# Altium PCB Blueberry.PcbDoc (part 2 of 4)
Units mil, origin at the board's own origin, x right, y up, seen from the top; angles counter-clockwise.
Board outline 2559.06 x 2204.72 mil, 6 copper layers (Top Layer, Mid-Layer 1, Mid-Layer 2, Mid-Layer 3, Mid-Layer 4, Bottom Layer); 211 components, 214 nets, 1171 pads, 598 vias.

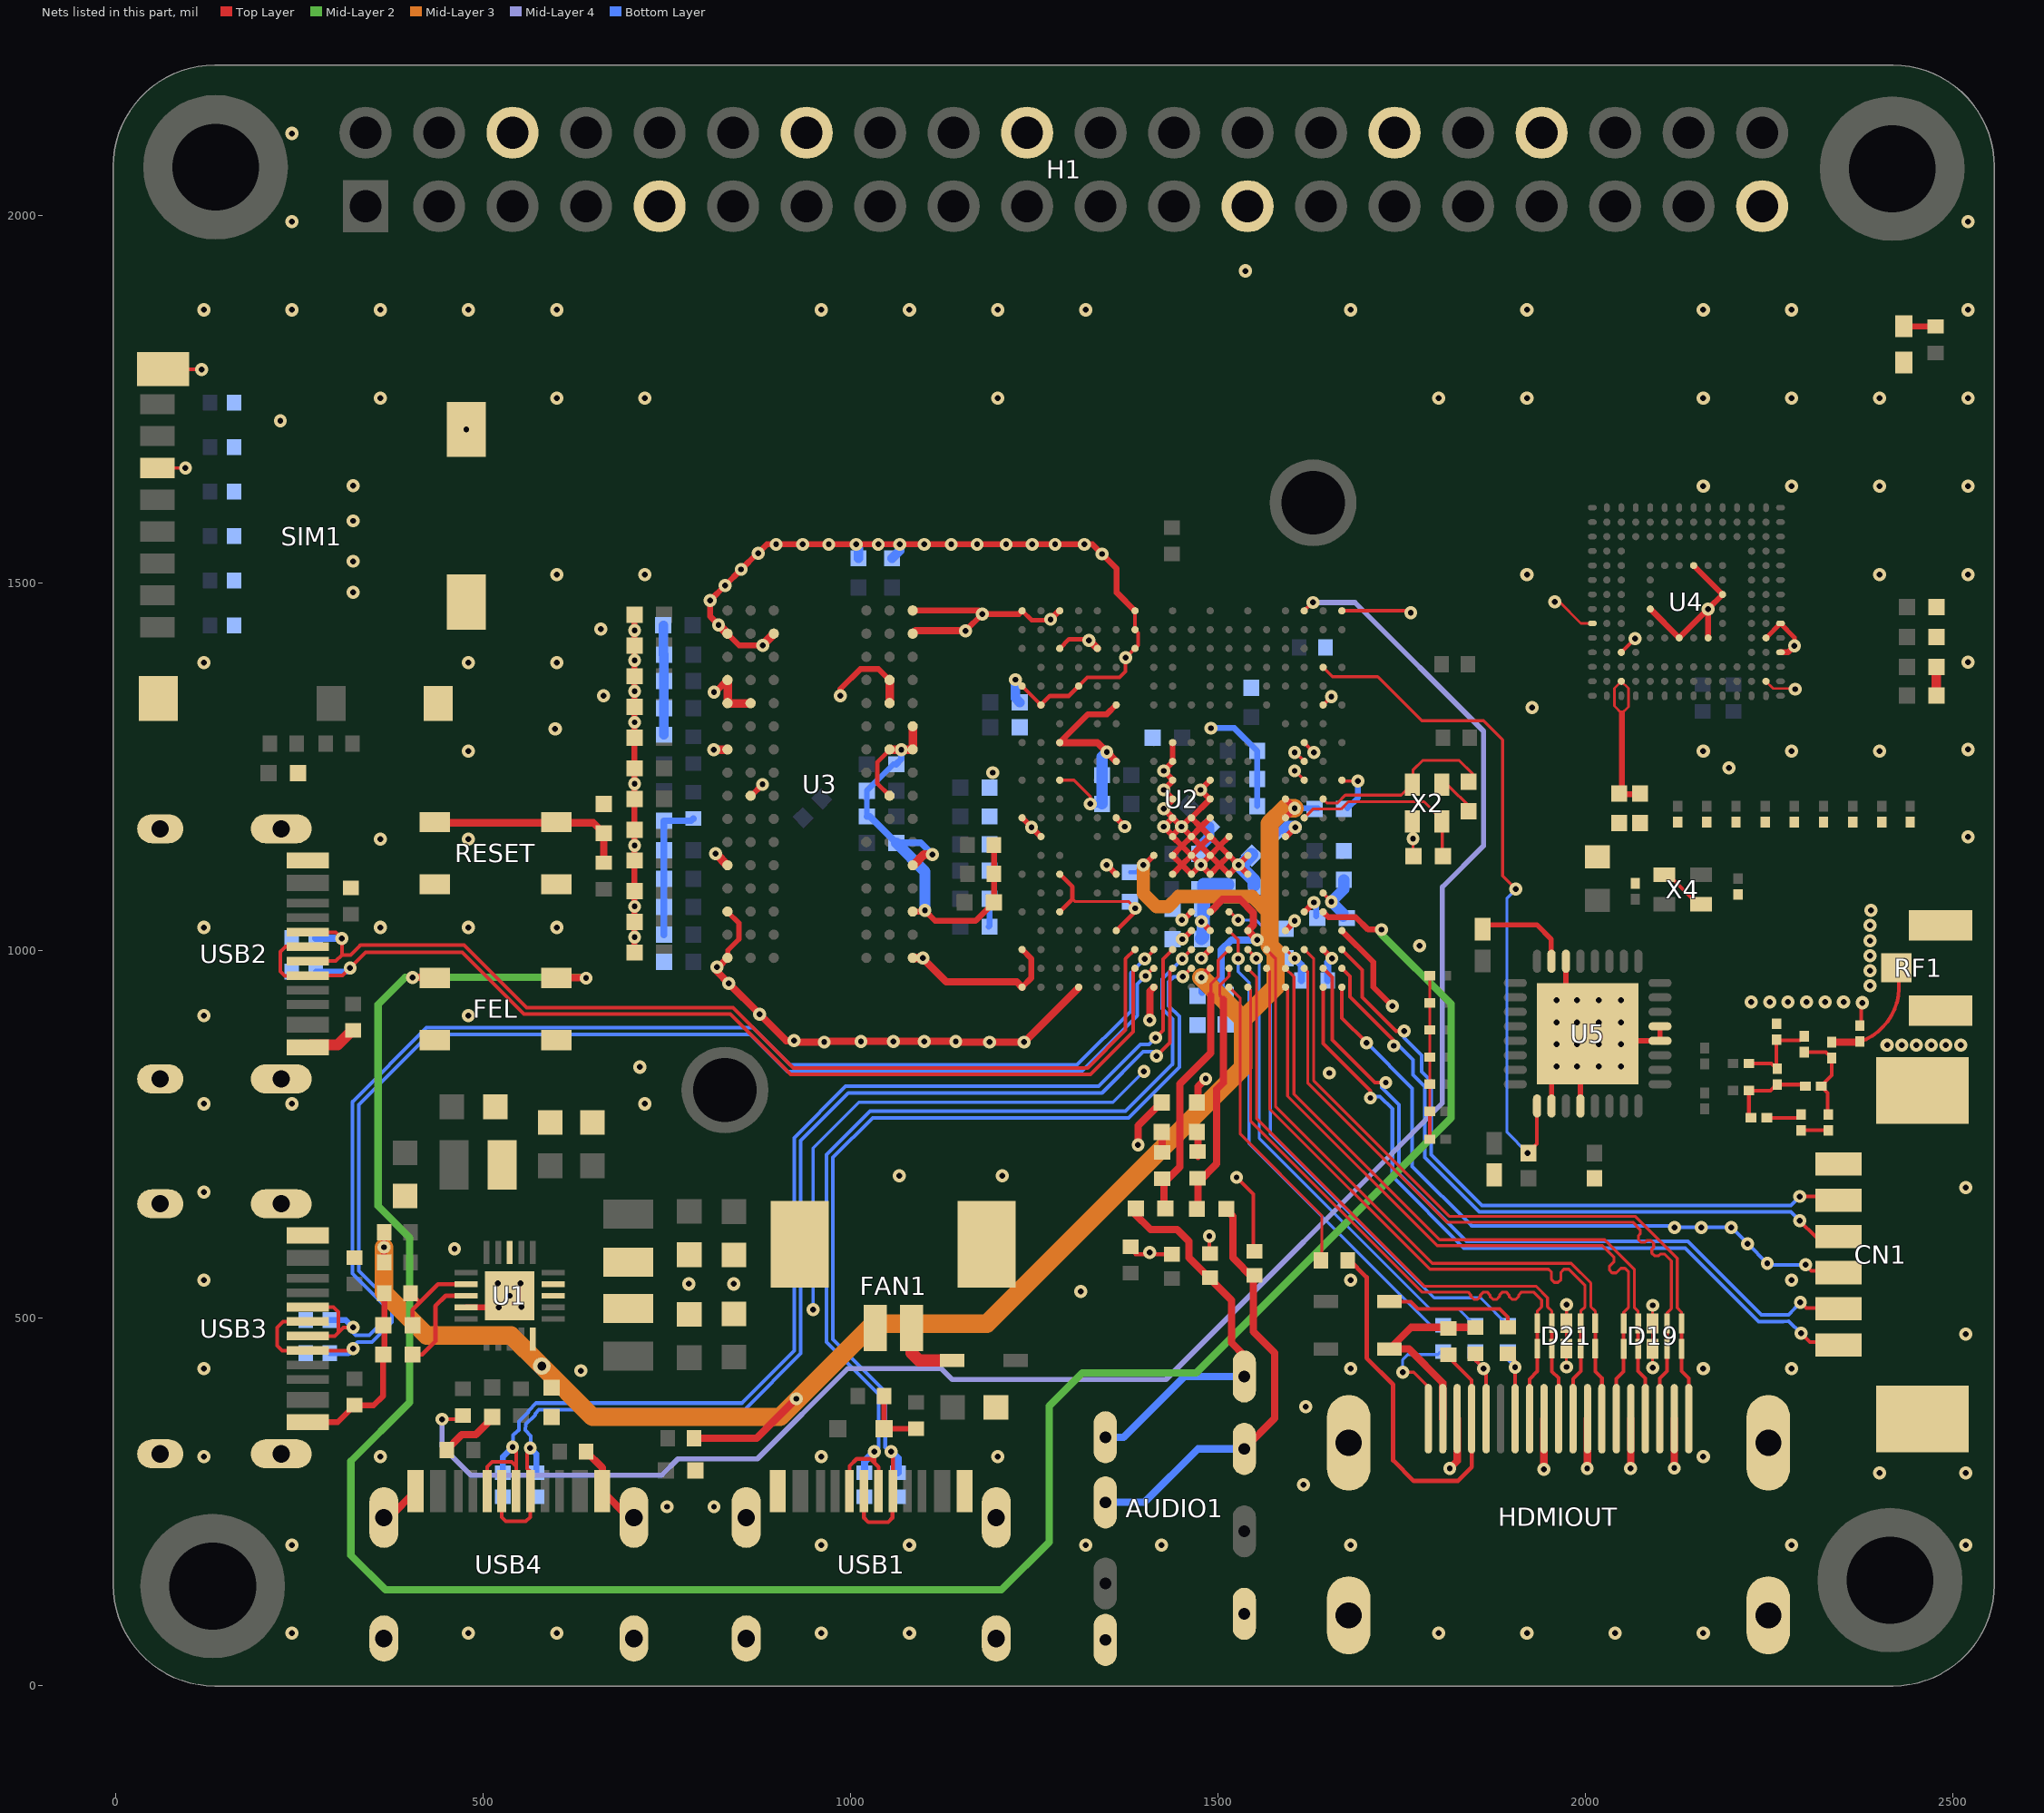
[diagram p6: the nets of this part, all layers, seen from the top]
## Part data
AUDIO1: Current Rating (Max)=500mA, JLCPCB Part Class="Extended Part", LCSC Part Name=3.5mm耳机座, Manufacturer=韩国韩荣, Voltage Rating (Max)=30V
C66 C67 C68 C69 C70 C71 C104 C105 C106 C107 C108 C117 C120: JLCPCB Part Class="Extended Part", LCSC Part Name="100nF ±10% 16V", Manufacturer=SAMSUNG(三星), Temperature Coefficient=X5R, Tolerance=±10%, Voltage Rated=16V
C87: JLCPCB Part Class="Extended Part", LCSC Part Name="100nF ±10% 25V", Manufacturer=PSA(信昌电陶), Temperature Coefficient=X7R, Tolerance=±10%, Voltage Rated=25V
C102: JLCPCB Part Class="Extended Part", LCSC Part Name="100pF ±5% 50V", Manufacturer=FH(风华), Temperature Coefficient=C0G, Tolerance=±5%, Voltage Rated=50V
C109 C123: JLCPCB Part Class="Extended Part", LCSC Part Name="7pF 25V ±0.25pF", Manufacturer=FH(风华), Temperature Coefficient=C0G, Voltage Rated=25V
C110 C113 C114 C115: JLCPCB Part Class=扩展库, LCSC Part Name="1pF 50V ±0.05pF", Manufacturer=muRata(村田), Temperature Coefficient=C0G, Voltage Rated=50V
C112 C119: JLCPCB Part Class=扩展库, LCSC Part Name="1.2pF 50V ±0.1pF", Manufacturer=FH(风华), Temperature Coefficient=C0G, Voltage Rated=50V
C116 C124: JLCPCB Part Class="Extended Part", LCSC Part Name="4.7uF ±20% 6.3V", Manufacturer=muRata(村田), Temperature Coefficient=X5R, Tolerance=±20%, Voltage Rated=6.3V
C118: JLCPCB Part Class=基础库, LCSC Part Name="10uF ±20% 6.3V", Manufacturer=SAMSUNG(三星), Temperature Coefficient=X5R, Tolerance=±20%, Voltage Rated=6.3V
C121 C122: JLCPCB Part Class="Extended Part", LCSC Part Name="22pF ±5% 50V", Manufacturer=YAGEO(国巨), Temperature Coefficient=NP0, Tolerance=±5%, Voltage Rated=50V
CN1: JLCPCB Part Class="Extended Part", Manufacturer=MOLEX
D1 D22 D23: Average Rectified Current (Io)=1A, Forward Voltage (Vf@If)=600mV@1A, JLCPCB Part Class="Extended Part", LCSC Part Name="40V 1A 600mV@1A", Manufacturer=CJ（江苏长电/长晶）, Reverse Voltage (Vr)=40V
D2 D3 D4 D5 D6 D7 D8 D9 D10 D11 D12 D13 D14 D15 D16 D17 D18: Current - Peak Pulse (10/1000μs)=-, JLCPCB Part Class="Extended Part", Manufacturer=BORN伯恩半导体, Voltage - Clamping (Max) @ Ipp=50V, Voltage - Reverse Standoff (Typ)=5V
D19 D21: JLCPCB Part Class="Extended Part", Manufacturer=SEMTECH
D20: JLCPCB Part Class="Extended Part"
FAN1: Current Rating (Max)=-, JLCPCB Part Class="Extended Part", LCSC Part Name=线至板连接器,2触点,针座,1.25mm,贴装,1排, Manufacturer=MOLEX
FEL RESET: Contact Current=50mA, JLCPCB Part Class="Extended Part", LCSC Part Name="4.2*3.2*2.5mm 立贴 轻触开关", Manufacturer=C&K, Operating Force=160gf, Operating Temperature=-40℃~+85℃, Voltage Rating (DC)=16V
H1: Color=黑色, Current Rating (Max)=-, JLCPCB Part Class="Extended Part", LCSC Part Name="2.54mm 2x20P 直插", Manufacturer=Ckmtw(灿科盟), Operating Temperature Range=-40℃~+105℃
HDMIOUT: Current Rating (Max)=500mA, JLCPCB Part Class="Extended Part", LCSC Part Name="HDMI 母 P数:19", Manufacturer=SOFNG(硕方), Operating Temperature Range=-25~+75
L1 L2 L3: DC Resistance (DCR)=264mΩ, JLCPCB On Sale=1, JLCPCB Part Class="Extended Part", LCSC Part Name="2.2uH ±20% 1.1A 264mΩ", Manufacturer=CENKER(岑科), Manufacturer Part=CKCS201610-2.2uH/M, Rated Current=1.1A, Tolerance=±20%
L4 L5: DC Resistance (DCR)=700mΩ, Frequency - Self Resonant=3.2GHz, JLCPCB Part Class=扩展库, LCSC Part Name="10nH ±3%", Manufacturer=muRata(村田), Q @ Freq=14@500MHz, Rated Current=250mA, Ratings=-, Tolerance=±3%
L6 L7 L8: DC Resistance (DCR)=200mΩ, Frequency - Self Resonant=500MHz, JLCPCB Part Class=扩展库, LCSC Part Name="2.7nH ±0.1nH", Manufacturer=Sunlord(顺络), Q @ Freq=13@500MHz, Rated Current=500mA, Ratings=-
L9: DC Resistance (DCR)=-, JLCPCB Part Class=扩展库, LCSC Part Name="4.7uH ±20%", Manufacturer=TDK, Tolerance=±20%
LED1: Color Temperature=6000K~7000K, Emitted Color=红灯, Forward Current=25mA, JLCPCB Part Class="Extended Part", LCSC Part Name="红灯 正贴 色温6000K~7000K", Lens Color=无色透明, Manufacturer=XINGLIGHT(成兴光), Operating Temperature=-30℃~+85℃, Power Dissipation=55mW
R28: JLCPCB Part Class="Extended Part", LCSC Part Name="10kΩ ±0.5%", Manufacturer="EVER OHMS(天二科技)", Operating Temperature Range=-55~+155, Overload Voltage (Max)=25V, Power(Watts)=63mW, Temperature Coefficient=±25ppm/, Tolerance=±0.5%
R53: JLCPCB Part Class="Basic Part", LCSC Part Name="1MΩ ±1% 100mW", Manufacturer=UNI-ROYAL(厚声), Operating Temperature Range=-55℃~+155℃, Overload Voltage (Max)=75V, Power(Watts)=100mW, Temperature Coefficient=±100ppm/℃, Tolerance=±1%
R54: JLCPCB Part Class="Extended Part", LCSC Part Name="100kΩ ±1% 62.5mW", Manufacturer=YAGEO(国巨), Operating Temperature Range=-55℃~+155℃, Overload Voltage (Max)=50V, Power(Watts)=62.5mW, Temperature Coefficient=±100ppm/℃, Tolerance=±1%
R56: JLCPCB Part Class="Extended Part", LCSC Part Name="10kΩ ±1% 62.5mW", Manufacturer=YAGEO(国巨), Operating Temperature Range=-55℃~+155℃, Overload Voltage (Max)=50V, Power(Watts)=62.5mW, Temperature Coefficient=±100ppm/℃, Tolerance=±1%
RF1: Frequency-Max=6GHz, JLCPCB Part Class=ExtendedPart, LCSC Part Name=IPEX内针IPEX内针天线座IPEX-1IPEX11代, Manufacturer=BATWIRELESS(蝙蝠无线), Operating Temperature Range=-
SIM1: JLCPCB Part Class="Extended Part", LCSC Part Name="拔插式 MicroSD卡(TF卡) 卡座", Manufacturer=MOLEX, Operating Temperature Range=-
U3: JLCPCB Part Class="Extended Part", Manufacturer=HYNIX(海力士)
U4: Manufacturer=Kingston(金士顿), Manufacturer Part=EMMC04G-M627-A01
U5: JLCPCB Part Class=扩展库, Manufacturer=REALTEK(瑞昱)
USB1 USB2 USB3 USB4: JLCPCB Part Class="Extended Part", Manufacturer=XUNPU
X2 X4: library part SX32Y024000BC1T, Frequency Stability=-, JLCPCB Part Class="Extended Part", LCSC Part Name="3225 24M 12PF  10ppm  -20 -75", Manufacturer=TKD(泰晶)

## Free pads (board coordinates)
  round 196.85 hole 118.11: 1(132.19,135.58) 1(136.19,2065.58) 1(2414.19,143.58) 1(2417.19,2063.58)
  round 118.11 hole 86.61: 1(829.13,810.39) 1(1629.31,1609.17)

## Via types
v1: diameter 17.7, hole 7.9, Top Layer to Bottom Layer, 439 vias
v2: diameter 18, hole 8, Top Layer to Bottom Layer, 138 vias
v3: diameter 24, hole 15, Top Layer to Bottom Layer, 19 vias
v4: diameter 24, hole 12, Top Layer to Bottom Layer, 2 vias

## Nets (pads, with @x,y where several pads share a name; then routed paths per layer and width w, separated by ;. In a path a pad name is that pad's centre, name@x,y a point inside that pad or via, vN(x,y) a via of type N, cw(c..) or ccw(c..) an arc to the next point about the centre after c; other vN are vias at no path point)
1V8: C1.2 C14.2 C15.2 C16.2 C98.1 R2.1 R3.1 R49.2 U1.15 U2.D11 U2.D12 U2.F18 U2.H17 U2.H20 U2.L14 | length 2795.3
  Top Layer w8: R3.1@365.63,575.86 365.19,576.3 v1(365.19,596.58) 365.19,616.42 R2.1@365.63,616.86 ; v1(1398.19,1116.58) 1399.66,1116.58 U2.L14@1412.57,1129.49 ; v1(1477.19,963.58) 1477.19,963.79 U2.H20@1489.35,975.95 ; U2.D12@1591.71,1180.67 1604.19,1193.15 v1(1604.19,1193.58) 1604.19,1193.77 U2.D11@1591.71,1206.26
  Top Layer w10: R49.2@787.19,336.58 872.19,336.58 v1(926.07,390.46) ; U2.H17@1489.35,1052.72 1506.21,1069.58 1530.19,1069.58 1548.19,1051.58 1548.19,1034.79 U2.F18@1540.53,1027.13 1553.07,1014.58 v1(1553.19,1014.58)
  Mid-Layer 3 w18: v1(1398.19,1116.58) 1398.19,1077.58 1416.19,1059.58 1432.19,1059.58 1446.19,1073.58 1546.66,1073.58 1570.19,1050.05
  Mid-Layer 3 w25: v1(365.19,596.58) 365.19,534.58 423.19,476.58 538.19,476.58 v4(579.91,434.86) 649.19,365.58 904.19,365.58 1031.19,492.58 1185.33,492.58 1534.19,841.44 1534.19,906.58 ; v1(1477.19,963.58) 1534.19,906.58 ; v1(1604.19,1193.58) 1591.19,1193.58 1570.19,1172.58 1570.19,1050.05 1570.19,1006.72 1578.19,998.72 1578.19,950.58 1534.19,906.58
  Bottom Layer w5: C16.2@1380.19,1106.59 1388.2,1106.59 v1(1398.19,1116.58)
  Bottom Layer w8: v1(1604.19,1193.58) C98.1@1636.2,1193.58
  Bottom Layer w10: v1(1477.19,963.58) 1478.19,962.58 C15.2@1478.19,943.59 ; C14.2@1510.19,939.59 1504.19,945.59 1504.19,1000.58 1518.19,1014.58 v1(1553.19,1014.58)
AGND: C92.1 C93.1 R31.1 R32.2 U2.H18 | length 129.9
  Top Layer w8: v1(1477.19,1039.58) 1489.35,1027.42 U2.H18@1489.35,1027.13
  Bottom Layer w8: C92.1@1477.19,1016.57 C92.1@1479.18,1014.58
  Bottom Layer w18: C92.1@1477.19,1016.57 1479.18,1018.57 C93.1@1480.4,1054.58 ; C93.1@1480.4,1051.67 C93.1@1480.4,1054.58 ; R32.2@1513.19,1089.58 1480.4,1089.58 C93.1@1480.4,1054.58
ANT: C115.2 L8.1 RF1.1 | length 164.1
  Top Layer w5: C115.2@2372.62,875.75 ccw(c2347.48,950.5) RF1.1@2421.9,976.58
  Top Layer w10: L8.1@2334.84,875.43 2372.3,875.43 C115.2@2372.62,875.75 ; C115.2@2372.19,875.58 ccw(c2341.7,953.31) C115.2@2372.62,875.75 ; C115.2@2373.19,876.32 C115.2@2372.62,875.75
AP_REG_ON: U2.C9 | length 18.1
  Top Layer w4.5: v1(1604.19,1269.58) 1605.15,1269.58 U2.C9@1617.3,1257.44
BT_RSTN: U2.C10 | length 18.4
  Top Layer w4: v1(1604.19,1244.58) 1604.56,1244.58 U2.C10@1617.3,1231.85
CS: R54.1 U2.B4 U5.25 | length 940.8
  Top Layer w4: U2.B4@1642.89,1385.39 1655.69,1372.58 1717.19,1372.58 1777.19,1312.58 1861.19,1312.58 1887.19,1286.58 1887.19,1101.58 v1(1905.19,1083.58)
  Top Layer w5: v1(1921.19,724.58) 1933.95,737.34 U5.25@1933.95,788.69
  Bottom Layer w4: v1(1905.19,1083.58) 1893.04,1071.43 1893.04,752.73 v1(1921.19,724.58)
D0+: D11.1 U2.J20 USB1.A6 USB1.B6 | length 1319.9
  Top Layer w5: v1(1055.19,318.58) 1057.69,316.08 USB1.B6@1057.69,264.88 ; v1(1452.19,964.58) 1452.39,964.58 U2.J20@1463.76,975.95
  Top Layer w5.4: USB1.A6@1018.39,264.88 1018.39,228.38 1024.19,222.58 1051.19,222.58 1057.19,228.58 1057.19,264.38 USB1.B6@1057.69,264.88
  Bottom Layer w5: v1(1055.19,318.58) 1053.19,318.58 1047.19,324.58 1047.19,400.31 976.19,471.31 976.19,718.58 1030.19,772.58 1378.19,772.58 1447.19,841.58 1447.19,910.58 1432.83,924.94 1432.83,957.49 1439.38,964.05 v1(1452.19,964.58)
  Bottom Layer w10: v1(1055.19,318.58) 1064.42,309.35 D11.1@1064.42,289.95
D0-: D9.1 U2.J19 USB1.A7 USB1.B7 | length 1300.2
  Top Layer w5: v1(1451.19,988.58) 1463.76,1001.15 U2.J19@1463.76,1001.54
  Top Layer w5.4: USB1.B7@998.69,264.88 998.69,299.08 1008.19,308.58 1027.19,308.58 1032.19,303.58 ; v1(1032.19,318.58) 1032.19,303.58 ; USB1.A7@1037.99,264.88 1038.19,265.08 1038.19,297.58 1032.19,303.58
  Bottom Layer w5: v1(1032.19,318.58) 1038.19,324.58 1038.19,396.58 967.19,467.58 967.19,722.31 1026.46,781.58 1374.19,781.58 1438.19,845.58 1438.19,906.85 1423.83,921.22 1423.83,961.22 v1(1451.19,988.58)
  Bottom Layer w10: D9.1@1019.05,289.95 1019.05,305.44 v1(1032.19,318.58)
D1+: D14.1 U2.M20 USB2.A6 USB2.B6 | length 1471.8
  Top Layer w5: USB2.A6@261.49,1005.38 230.99,1005.38 224.19,998.58 224.19,971.58 230.19,965.58 260.99,965.58 USB2.B6@261.49,966.08 308.69,966.08 v1(319.19,976.58) 340.19,997.58 471.46,997.58 555.46,913.58 836.46,913.58 918.46,831.58 1326.19,831.58 1384.19,889.58 1384.19,973.16 U2.M20@1386.98,975.95
  Bottom Layer w8: D14.1@272.58,971.68 314.29,971.68 v1(319.19,976.58)
D1-: D13.1 U2.M19 USB2.A7 USB2.B7 | length 1434.8
  Top Layer w5: USB2.A7@261.49,985.78 299.51,985.78 307.95,994.22 ; USB2.B7@261.49,1025.08 299.51,1025.08 v1(307.95,1016.64) 307.95,994.22 ; U2.M19@1386.98,1001.54 1374.19,988.75 1374.19,892.31 1322.46,840.58 922.19,840.58 840.19,922.58 559.19,922.58 474.19,1007.58 333.19,1007.58 319.83,994.22 307.95,994.22
  Bottom Layer w10: D13.1@272.58,1017.05 307.54,1017.05 v1(307.95,1016.64)
D2+: D18.1 U2.L20 USB3.A6 USB3.B6 | length 1819.5
  Top Layer w5: USB3.A6@261.49,495.38 227.99,495.38 220.19,487.58 220.19,462.58 226.69,456.08 USB3.B6@261.49,456.08 320.69,456.08 v1(323.19,458.58) ; v1(1401.19,965.58) 1411.56,975.95 U2.L20@1412.57,975.95
  Bottom Layer w5: v1(323.19,458.58) 323.19,461.33 329.44,467.58 348.92,467.58 375.83,494.49 375.83,519.94 331.19,564.58 331.19,790.58 426.83,886.22 863.83,886.22 914.46,835.58 1314.19,835.58 1390.19,911.58 1390.19,954.58 v1(1401.19,965.58)
  Bottom Layer w8: D18.1@291.58,452.2 316.81,452.2 v1(323.19,458.58)
D2-: D17.1 U2.L19 USB3.A7 USB3.B7 | length 1799.8
  Top Layer w5: USB3.A7@261.49,475.78 261.69,475.58 298.19,475.58 303.19,480.58 ; USB3.B7@261.49,515.08 296.69,515.08 303.19,508.58 303.19,480.58 ; v1(323.19,487.58) 310.19,487.58 303.19,480.58 ; v1(1400.19,988.58) 1412.57,1000.96 U2.L19@1412.57,1001.54
  Bottom Layer w5: v1(323.19,487.58) 323.19,480.33 326.94,476.58 345.19,476.58 366.83,498.22 366.83,516.22 322.19,560.85 322.19,794.31 423.1,895.22 867.55,895.22 918.19,844.58 1308.19,844.58 1381.19,917.58 1381.19,969.58 v1(1400.19,988.58)
  Bottom Layer w8: D17.1@291.58,497.57 313.2,497.57 v1(323.19,487.58)
D3+: D16.1 U2.K20 USB4.A6 USB4.B6 | length 1618.7
  Top Layer w5: USB4.A6@525.39,264.88 525.39,229.38 531.19,223.58 558.19,223.58 564.19,229.58 564.19,264.38 USB4.B6@564.69,264.88 564.69,291.08 560.19,295.58 560.19,319.58 v1(564.19,323.58) ; v1(1416.19,856.58) 1434.19,874.58 1434.19,971.98 U2.K20@1438.16,975.95
  Bottom Layer w5: v1(564.19,323.58) 564.87,339.92 557.68,347.73 558,355.41 558,355.6 570.89,368.49 570.89,370.28 576.19,375.58 855.92,375.58 932.19,451.85 932.19,741.58 997.19,806.58 1342.19,806.58 1398.19,862.58 1410.19,862.58 v1(1416.19,856.58)
  Bottom Layer w8: v1(564.19,323.58) 572.42,315.35 572.42,295.47 D16.1@572.42,289.95
D3-: D15.1 U2.K19 USB4.A7 USB4.B7 | length 1600.8
  Top Layer w5: USB4.B7@505.69,264.88 505.69,298.08 512.19,304.58 539.19,304.58 545.19,298.58 ; v1(540.19,324.58) 545.19,319.58 545.19,298.58 ; USB4.A7@544.99,264.88 545.19,265.08 545.19,298.58 ; v1(1415.19,881.58) 1425.19,891.58 1425.19,988.57 U2.K19@1438.16,1001.54
  Bottom Layer w5: v1(540.19,324.58) 540.87,340.92 548.69,348.11 549,355.6 549,359.33 561.89,372.22 561.89,374 572.46,384.58 852.19,384.58 923.19,455.58 923.19,745.31 993.46,815.58 1337.46,815.58 1394.46,872.58 1406.19,872.58 v1(1415.19,881.58)
  Bottom Layer w8: D15.1@527.05,289.95 527.05,295.47 527.05,311.44 v1(540.19,324.58)
EPHY_RTX: R26.1 U2.B19 | length 49.6
  Top Layer w8: U2.B19@1642.89,1001.54 v1(1654.84,989.58) v1@1655.19,989.58
  Bottom Layer w10: R26.1@1649.19,959.58 1649.19,983.92 v1(1654.84,989.58)
EPHY_RXN: CN1.6 U2.B21 | length 1008.8
  Top Layer w5: U2.B21@1642.89,950.35 1642.89,873.88 1707.19,809.58 v1(1707.19,799.58) ; v1(2293.19,479.58) 2305.19,467.58 2340.07,467.58 CN1.6@2344.07,463.58
  Bottom Layer w5: v1(1707.19,799.58) 1709.26,801.65 1720.12,801.65 1737.19,784.58 1737.19,692.85 1834.46,595.58 2135.46,595.58 2235.53,495.51 2268.69,495.51 2276.3,495.69 v1(2293.19,479.58)
EPHY_RXP: CN1.5 U2.B20 | length 1027.6
  Top Layer w5: U2.B20@1642.89,975.95 1655.19,963.64 1655.19,878.58 1713.19,820.58 v1(1728.19,820.58) ; v1(2292.19,521.58) 2300.19,513.58 2347.29,513.58 CN1.5@2348.09,512.78
  Bottom Layer w5: v1(1728.19,820.58) 1722.94,815.33 1722.94,813.83 1746.19,790.58 1746.19,696.58 1838.19,604.58 2139.19,604.58 2239.26,504.51 2268.58,504.51 2276.08,504.69 v1(2292.19,521.58)
EPHY_TXN: CN1.3 U2.A20 | length 915.9
  Top Layer w5: U2.A20@1668.48,975.95 1679.48,964.95 1679.48,937.29 1739.19,877.58 v1(1739.19,870.58) ; v1(2291.19,632.58) 2313.19,610.58 2343.47,610.58 CN1.3@2344.07,611.18
  Bottom Layer w5: v1(1739.19,870.58) 1746.19,870.58 1765.19,851.58 1765.19,830.89 1781.19,814.89 1781.19,718.85 1855.46,644.58 2279.19,644.58 v1(2291.19,632.58)
EPHY_TXP: CN1.2 U2.A19 | length 930.8
  Top Layer w5: U2.A19@1668.48,1001.54 1696.19,973.82 1696.19,936.58 1742.19,890.58 v1(1753.19,890.58) ; v1(2291.19,665.58) 2345.29,665.58 2348.09,662.78 CN1.2@2348.09,660.38
  Bottom Layer w5: v1(1753.19,890.58) 1753.19,881.58 1777.19,857.58 1777.19,835.58 1790.19,822.58 1790.19,722.58 1859.19,653.58 2279.19,653.58 v1(2291.19,665.58)
FEL: FEL.1 FEL.2 U2.B17 | length 3453.7
  Top Layer w8: U2.B17@1642.89,1052.72 1650.02,1045.58 1687.19,1045.58 1704.19,1028.58 v1(1722.19,1028.58)
  Top Layer w10: v1(404.19,963.58) 438.79,963.58 438.09,962.88 FEL.1@434.51,962.9 ; FEL.2@599.87,962.9 639.89,962.88 v1(640.19,962.58)
  Mid-Layer 2 w10: v1(640.19,962.58) 639.19,963.58 v1(404.19,963.58) 394.19,963.58 357.19,926.58 357.19,652.58 400.19,609.58 400.19,385.58 320.19,305.58 320.19,177.58 367.19,130.58 1205.19,130.58 1270.19,195.58 1270.19,380.58 1315.19,425.58 1470.19,425.58 1817.19,772.58 1817.19,927.58 1722.19,1022.58 v1(1722.19,1028.58)
GND: AUDIO1.1 AUDIO1.8 C1.1 C2.2 C3.1 C4.2 C5.1 C6.2 C7.2 C8.2 C9.2 C10.2 C11.2 C12.1 C13.2 C14.1 C15.1 C16.1 C17.1 C18.1 C19.1 C20.1 C21.1 C22.1 C23.1 C24.1 C25.1 C26.1 C27.1 C28.1 C29.1 C30.1 C31.1 C32.1 C33.1 C34.1 C35.1 C36.1 C37.1 C38.1 C39.1 C40.1 C41.1 C42.1 C43.1 C44.1 C45.1 C46.1 C47.1 C48.1 C49.1 C50.1 C51.1 C52.1 C53.1 C54.1 C55.1 C56.1 C57.1 C58.1 C59.1 C60.1 C61.1 C62.1 C63.1 C64.1 C65.1 C66.2 C67.2 C68.1 C69.1 C70.1 C71.1 C75.1 C76.1 C77.1 C81.1 C82.1 C83.1 C87.2 C88.1 C90.1 C94.2 C95.1 C96.1 C97.2 C98.2 C99.2 C100.1 C102.1 C104.2 C105.2 C106.2 C107.1 C108.2 C114.1 C115.1 C116.1 C117.1 C118.1 C119.2 C120.2 C121.2 C122.2 C124.2 CN1.1 CN1.4 CN1.7 CN1.8 D2.1 D3.1 D4.1 D5.1 D6.1 D7.1 D8.1 D9.2 D10.1 D11.2 D12.1 D13.2 D14.2 D15.2 D16.2 D17.2 D18.2 D19.3 D19.8 D21.3 D21.8 FAN1.2 FAN1.3 FAN1.4 FEL.3 FEL.4 H1.6 H1.9 H1.14 H1.20 H1.25 H1.30 H1.34 H1.39 HDMIOUT.2 HDMIOUT.5 HDMIOUT.8 HDMIOUT.11 HDMIOUT.17 HDMIOUT.20 HDMIOUT.21 HDMIOUT.22 HDMIOUT.23 L6.1 LED1.2 R1.1 R6.2 R8.1 R9.1 R11.1 R26.2 R30.1 R32.1 R35.1 R36.2 R40.1 R43.2 R44.1 R46.2 R52.2 R53.1 R56.2 RESET.3 RESET.4 RF1.2 RF1.3 SIM1.6 SIM1.9 SIM1.10 SIM1.12 SIM1.13 SIM1.14 U1.9 U1.21 U2.A1 U2.A10 U2.A18 U2.A21 U2.B6 U2.B16 U2.D19 U2.F14 U2.F15 U2.G13 U2.G14 U2.G15 U2.H10 U2.H11 U2.H12 U2.H13 U2.H14 U2.H15 U2.H19 U2.J12 U2.J13 U2.J14 U2.J15 U2.K8 U2.K9 U2.K10 U2.K11 U2.K12 U2.K13 U2.K14 U2.K15 U2.L21 U2.M1 U2.M2 U2.M3 U2.N6 U2.N9 U2.N12 U2.N15 U2.N18 U2.P3 U2.R5 U2.R21 U2.T1 U2.T3 U2.T8 U2.T10 U2.T15 U2.T17 U2.U6 U2.U13 U2.V1 U2.V5 U2.V12 U2.V19 U2.V21 U3.A9 U3.B1 U3.B3 U3.B9 U3.D1 U3.D8 U3.E1 U3.E2 U3.E8 U3.F9 U3.G1 U3.G8 U3.G9 U3.J2 U3.J8 U3.M1 U3.M9 U3.P1 U3.P9 U3.T1 U3.T9 U4.A6 U4.C4 U4.E7 U4.G5 U4.H10 U4.J5 U4.K8 U4.N2 U4.N5 U4.P4 U4.P6 U5.4 U5.5 U5.14 U5.26 U5.28 U5.33 USB1.12 USB1.13 USB1.14 USB1.15 USB1.A1B12 USB1.B1A12 USB2.12 USB2.13 USB2.14 USB2.15 USB2.A1B12 USB2.B1A12 USB3.12 USB3.13 USB3.14 USB3.15 USB3.A1B12 USB3.B1A12 USB4.12 USB4.13 USB4.14 USB4.15 USB4.A1B12 USB4.B1A12 X2.2 X2.4 X4.2 X4.4 | length 11353.8
  Top Layer w3.5: v1(1958.19,1474.58) 1964.19,1474.58 1993.71,1445.05 U4.A6@2009.24,1445.05 ; U4.N2@2245.46,1366.32 2255.19,1356.58 2284.19,1356.58 v1(2285.19,1355.58)
  Top Layer w4: SIM1.6@57.05,1656.59 v1(95.18,1656.59) ; U2.T10@1284.62,1231.85 1303.92,1231.85 1326.19,1209.58 v1(1326.19,1199.58) ; 1301.96,1070.1 1305.12,1066.93 1377.84,1066.93 v1(1387.19,1057.58) ; U2.D19@1591.71,1001.54 1592.23,1001.54 v1(1604.19,989.58) ; U2.A10@1668.48,1231.85 1669.74,1230.58 v1(1690.19,1230.58) v1@1689.19,1231.58 ; C99.2@1765.19,1131.59 v1(1765.19,1152.4) X2.2@1765.19,1177.58 ; C66.2@1788.04,781.38 C105.2@1788.04,818.28 C67.2@1788.04,855.18 C106.2@1788.04,892.08 C120.2@1788.04,928.98 C102.1@1788.04,965.89 ; X2.4@1805.19,1227.58 1810.18,1227.58 C94.2@1846.19,1191.57 ; v1(1974.19,433.58) 1973.79,433.98 D21.8@1973.79,458.58 D21.3@1973.79,493.18 1974.19,493.58 v1(1974.19,518.58) ; U5.33@1988.25,872.52 1993,877.26 U5.33@2002.85,887.11 ; v1(2091.19,432.58) D19.8@2091.19,458.28 D19.3@2091.19,492.88 v1(2091.19,517.58)
  Top Layer w5: SIM1.9@64.93,1790.84 116.93,1790.84 v1(117.19,1790.58) ; v1(1224.19,1368.58) 1224.65,1368.58 U2.V5@1233.44,1359.8 U2.U6@1259.03,1334.21 ; U2.R5@1310.21,1359.8 1321.99,1371.58 1366.19,1371.58 1374.19,1379.58 v1(1374.19,1398.58) 1374.58,1398.58 U2.M3@1386.98,1410.98 1391.19,1415.19 1391.19,1432.35 U2.M2@1386.98,1436.57 U2.M1@1386.98,1462.17 ; R30.1@1384.19,590.58 1387.79,586.98 D12.1@1430.19,586.98 ; D8.1@1488.19,586.98 v1(1488.19,611.58) ; v1(1525.19,691.58) 1548.19,668.58 D10.1@1548.19,586.98 ; U2.B16@1642.89,1078.31 1642.89,1077.88 v1(1654.19,1066.58) ; U2.B6@1642.89,1334.28 v1(1654.19,1345.58) ; U2.A21@1668.48,950.35 1668.48,908.29 v1(1702.19,874.58) ; U2.A1@1668.48,1462.17 1759.6,1462.17 v1(1762.19,1459.58) ; C71.1@1788.04,743.48 C66.2@1788.04,781.38 ; U4.C4@2048.61,1405.68 2067.19,1424.27 v1(2067.19,1424.58) ; X4.2@2107.19,1103.12 2112.85,1103.12 2152.85,1063.12 X4.4@2157.19,1063.12 ; L6.1@2246.61,772.58 2288.19,772.58 2292.19,776.58 C114.1@2292.19,777.2 ; v1(2299.19,572.58) 2307.19,564.58 2346.67,564.58 CN1.4@2344.07,561.98 ; C115.1@2373.19,897.92 2374.84,899.57 2374.84,927.51 v2(2376.5,929.16)
  Top Layer w6: U3.J8@1053.06,1210.66 1036.19,1227.52 1036.19,1256.1 U3.G8@1053.38,1273.29 ; U2.V1@1233.5,1462.27 1246.18,1449.58 1271.19,1449.58 v1(1272.19,1450.58) ; U2.U6@1259.03,1334.21 1271.4,1346.58 1296.99,1346.58 U2.R5@1310.21,1359.8 ; U2.T3@1284.62,1410.98 1297.22,1423.58 1322.67,1423.58 v1(1324.46,1421.8) ; U2.T17@1284.68,1052.82 1301.96,1070.1 1301.96,1086.72 U2.T15@1284.68,1104 ; U2.N18@1361.45,1027.23 1387.19,1052.97 v1(1387.19,1057.58) ; U4.N5@2245.46,1425.36 U4.P6@2265.14,1445.05 2284.19,1426.01 v1(2284.19,1414.58)
  Top Layer w7: U3.T1@832.91,989.82 832.91,1000.3 848.19,1015.58 848.19,1037.53 U3.P1@832.91,1052.81 ; U5.26@1953.63,788.69 1953.63,837.89 U5.33@1988.25,872.52 ; U5.14@1973.32,985.54 1973.32,916.64 U5.33@2002.85,887.11 2012.69,877.27 2018.19,877.27 U5.4@2101.27,877.27 U5.5@2101.27,896.96 ; U5.28@1993,788.69 U5.33@1993,877.26
  Top Layer w8: USB3.B1A12@261.49,358.58 302.2,358.58 R43.2@325.19,381.58 351.19,381.58 364.2,394.59 C12.1@364.2,450.58 365.63,452.02 R1.1@365.63,533.86 ; U1.9@477.21,514.8 520.97,514.8 v1(521.19,514.58) ; C48.1@706.2,997.35 v1(706.2,1018.46) C54.1@706.2,1039.12 v1(706.2,1060.11) C50.1@706.2,1080.89 C57.1@706.2,1122.66 v1(706.2,1143.21) C56.1@706.2,1164.43 C55.1@706.2,1206.2 v1(706.2,1226.86) C49.1@706.2,1247.96 C35.1@706.2,1289.73 v1(706.2,1310.62) C42.1@706.2,1331.5 v1(706.2,1352.97) C36.1@706.2,1373.27 v1(706.2,1394.66) C43.1@706.2,1415.04 v1(706.2,1435.6) C53.1@706.2,1456.81 ; v1(820.46,1443.11) 809.19,1454.38 v1(809.19,1476.37) 809.19,1476.58 v1(829.19,1496.58) v1(851.19,1518.58) 873.19,1540.58 v1(874.19,1540.58) 886.19,1552.58 v1(898.8,1552.58) v1(934.7,1552.58) v1(970.37,1552.58) v1(1007.59,1552.58) v1(1037.73,1552.58) v1(1066.98,1552.58) v1(1100.43,1552.58) v1(1136.99,1552.58) v1(1172.22,1552.58) v1(1211.66,1552.58) v1(1247.19,1552.58) v1(1278.36,1552.58) v1(1318.19,1552.58) 1329.19,1552.58 v1(1342.19,1539.58) 1362.19,1519.58 1362.19,1486.95 U2.M1@1386.98,1462.17 ; U3.B1@832.91,1430.77 848.35,1415.33 v1(880.46,1415.33) ; U3.J2@864.4,1210.29 v1(880.22,1226.11) ; v1(986.19,1346.58) 986.19,1355.85 1013.46,1383.11 1038.04,1383.11 U3.D8@1053.38,1367.77 ; U3.A9@1084.56,1462.66 1174.28,1462.66 v1(1179.14,1457.8) ; U3.P9@1084.87,1052.81 1099.42,1052.81 v1(1101.19,1054.58) 1115.19,1040.58 1170.18,1040.58 C32.1@1195.18,1065.58 R9.1@1195.19,1104.58 R8.1@1195.19,1143.58 ; v1(1156.46,1435.11) v1(1179.14,1457.8) ; U2.V21@1233.44,950.35 1246.19,963.1 1246.19,988.78 U2.V19@1233.44,1001.54 ; U2.V12@1233.44,1180.67 U2.U13@1259.03,1155.08 ; U2.V1@1233.5,1462.27 1229.03,1457.8 v1(1179.14,1457.8) ; v1(1272.19,1450.58) 1283.88,1462.27 U2.T1@1284.68,1462.27 ; U2.T8@1284.62,1283.03 1323.17,1321.58 1348.76,1321.58 U2.N6@1361.39,1334.21 ; v1(1348.19,1116.58) 1348.7,1116.58 U2.N15@1361.39,1103.9 ; U2.N12@1361.39,1180.67 1373.19,1168.86 v1(1373.19,1168.58) ; v1@1425.19,1244.58 v1(1426.19,1244.58) ; U2.K15@1438.16,1103.9 1450.95,1116.69 ; U2.K14@1438.16,1129.49 1450.95,1116.69 ; U2.K8@1438.16,1283.03 U2.K9@1438.16,1257.44 1438.16,1256.55 v1(1426.19,1244.58) ; U2.K14@1438.16,1129.49 1450.96,1142.28 ; v1@1477.19,989.58 v1(1477.39,989.58) U2.H19@1489.35,1001.54 ; U2.H12@1489.35,1180.67 1476.55,1167.87 ; U2.H10@1489.35,1231.85 1489.35,1231.74 v1(1476.19,1218.58) 1488.51,1206.26 U2.H11@1489.35,1206.26 U2.J12@1463.76,1180.67 ; U2.G13@1514.94,1155.08 1502.14,1142.28 ; U2.F15@1540.53,1103.9 v1(1527.73,1116.69) ; U2.F14@1540.53,1129.49 v1(1527.73,1116.69) ; U2.A18@1668.48,1027.13 1711.19,984.41 1711.19,950.58 v1(1737.19,924.58) ; U4.E7@2087.97,1464.74 U4.G5@2127.34,1425.36 v1(2166.71,1464.74) ; U4.H10@2147.04,1523.8 U4.K8@2186.41,1484.42 v1(2166.71,1464.74) ; U4.J5@2166.71,1425.36 v1(2166.71,1464.74) ; U4.P4@2265.14,1405.68 2275.29,1405.68 v1(2284.19,1414.58) ; v1(1426.19,1244.58) 1438.16,1232.61 U2.K10@1438.16,1231.85 1438.16,1230.55 v1(1426.19,1218.58) 1438.16,1206.61 U2.K11@1438.16,1206.26 1438.16,1204.95 v1(1426.19,1192.98) 1438.16,1181.01 U2.K12@1438.16,1180.67 ; U2.K13@1438.16,1156.61 v1(1450.18,1168.64) ; U2.K13@1438.16,1156.61 v1(1426.19,1168.58) 1438.16,1180.55 U2.K12@1438.16,1180.67 ; U2.K13@1438.16,1156.61 U2.K13@1438.16,1155.08 1450.96,1142.28 ; U2.K12@1438.16,1180.67 v1(1450.18,1168.64) ; v1(1450.18,1168.64) 1462.21,1180.67 U2.J12@1463.76,1180.67 ; v1(1450.18,1168.64) U2.J13@1463.76,1155.08 ; 1450.95,1116.69 U2.J15@1463.76,1103.9 v1(1476.55,1116.69) ; 1450.95,1116.69 U2.J14@1463.76,1129.49 ; 1450.96,1142.28 U2.J14@1463.76,1129.49 ; 1450.96,1142.28 U2.J13@1463.76,1155.08 ; U2.J14@1463.76,1129.49 1476.55,1142.28 ; U2.J14@1463.76,1129.49 v1(1476.55,1116.69) ; U2.J13@1463.76,1155.08 1476.55,1142.28 ; U2.J13@1463.76,1155.08 1476.55,1167.87 ; U2.J12@1463.76,1180.67 1476.55,1167.87 ; v1(1476.55,1116.69) U2.H15@1489.35,1103.9 1502.14,1116.69 ; v1(1476.55,1116.69) U2.H14@1489.35,1129.49 ; 1476.55,1142.28 U2.H13@1489.35,1155.08 ; 1476.55,1142.28 U2.H14@1489.35,1129.49 ; 1476.55,1167.87 U2.H13@1489.35,1155.08 ; U2.H14@1489.35,1129.49 1502.14,1142.28 ; U2.H14@1489.35,1129.49 1502.14,1116.69 ; U2.H13@1489.35,1155.08 1502.14,1142.28 ; 1502.14,1116.69 U2.G15@1514.94,1103.9 v1(1527.73,1116.69) ; 1502.14,1116.69 U2.G14@1514.94,1129.49 ; 1502.14,1142.28 U2.G14@1514.94,1129.49 ; U2.G14@1514.94,1129.49 v1(1527.73,1116.69)
  Top Layer w9: v1(814.19,1351.58) 815.98,1351.58 U3.D1@832.56,1368.16 ; v1(818.19,977.58) 819.98,977.58 U3.T1@832.56,990.16
  Top Layer w10: USB4.12@365.09,228.88 372.19,228.88 USB4.A1B12@408.19,264.88 ; R44.1@448.19,318.58 471.19,341.58 490.19,341.58 512.63,364.02 C3.1@512.63,365.86 ; R46.2@640.19,318.58 662.19,296.59 USB4.B1A12@662.19,264.88 698.19,228.88 USB4.13@705.29,228.88 ; v1(818.19,977.58) 818.19,971.58 v1(834.19,955.58) v1(876.19,913.58) 912.19,877.58 v1(923.19,877.58) 925.19,875.58 v1(964.19,875.58) 965.19,876.58 v1(1014.19,876.58) v1(1058.19,876.58) v1(1100.19,876.58) v1(1143.19,876.58) 1144.19,875.58 v1(1189.19,875.58) v1(1236.19,875.58) 1310.21,949.6 U2.R21@1310.21,950.35 ; U3.B9@1084.56,1431.16 1088.51,1435.11 v1(1156.46,1435.11) ; v1@1098.17,989.82 1130.41,957.58 1226.2,957.58 U2.V21@1233.44,950.35 ; U2.U6@1258.56,1334.21 U2.U6@1259.03,1334.21 ; U2.T8@1284.62,1283.03 1335.96,1283.03 v1(1348.64,1270.35) 1361.39,1257.6 U2.N9@1361.39,1257.44 ; v1(1324.46,1421.8) 1325.13,1421.8 U2.P3@1335.86,1411.08 ; v1(1391.19,735.58) 1391.19,761.86 C88.1@1426.55,797.22 ; v1(1407.19,905.58) 1407.19,944.97 U2.L21@1412.57,950.35 ; C90.1@1472.55,797.22 1472.55,814.94 v1(1483.19,825.58) ; v1(1815.19,295.58) 1825.37,305.76 HDMIOUT.17@1825.37,363.29 ; v1(2002.19,295.58) 2002.57,295.96 HDMIOUT.8@2002.57,363.29 ; v1(2061.19,295.58) 2061.63,296.02 HDMIOUT.5@2061.63,363.29 ; HDMIOUT.2@2120.7,363.29 v1(2120.7,296.07) v1@2121.19,295.58 ; v1(1943.19,294.58) 1943.19,362.98 HDMIOUT.11@1943.5,363.29 1943.5,294.89 v1(1943.19,294.58)
  Top Layer w12: v1(813.94,1273.29) U3.G1@832.91,1273.29 ; v1(816.6,1132.11) U3.M1@832.91,1115.81 ; v1(820.46,1443.11) 820.56,1443.11 U3.B1@832.91,1430.77 ; U3.D1@832.91,1367.77 832.91,1336.28 U3.E2@864.4,1336.28 ; v1(880.46,1415.33) U3.B3@895.9,1430.77 ; U3.G8@1053.38,1273.29 v1(1069.13,1273.29) 1084.87,1273.29 U3.F9@1084.87,1304.78 ; U3.E8@1053.38,1336.28 U3.D8@1053.38,1367.77 ; U3.T9@1084.87,989.82 1098.17,989.82 v1(1098.46,990.11) ; U3.M9@1084.87,1115.81 1099.87,1130.8 v1(1111.46,1130.8)
  Top Layer w13: v2(2018.19,902.58) v2(2018.19,932.58) ; C75.1@2477.34,1347.16 C76.1@2477.34,1385.85 ; U1.21@521.19,515.39 521.19,546.58 v1(520.19,547.58) v1(551.19,547.58) ; U1.21@521.19,515.39 v1(521.19,514.58) 522.19,515.58 v1(552.19,515.58) 551.19,516.58 v1(551.19,547.58) ; U1.21@521.19,515.39 v1(536.31,530.5) 536.31,532.7 v1(551.19,547.58)
  Top Layer w15: USB2.B1A12@261.49,868.58 264.84,871.93 302.39,871.93 322.04,891.58 R36.2@323.19,891.58
  Bottom Layer w4: v1(949.19,511.58) 949.19,731.58 1011.19,793.58 1357.19,793.58 v1(1399.19,835.58)
  Bottom Layer w5: v1(1702.19,874.58) 1764.19,812.58 1764.19,706.58 1845.19,625.58 2119.19,625.58 v1(2121.19,623.58) v1(2157.34,623.58) v1(2198.19,623.58) v1(2220.45,601.32) v1(2247.19,574.58) 2249.19,572.58 v1(2299.19,572.58)
  Bottom Layer w8: C62.1@1022.2,1182.58 C63.1@1022.2,1217.58 1058.2,1253.58 C41.1@1062.18,1253.58 ; C30.1@1188.18,1032.58 1189.18,1033.58 C39.1@1189.18,1070.58 ; v1(1490.19,1302.58) 1522.18,1302.58 C23.1@1553.18,1271.58 C21.1@1553.18,1233.58 C22.1@1553.18,1196.58 ; v1(1527.73,1116.69) v1@1532.3,1116.69 ; C98.2@1676.2,1193.58 1690.19,1207.57 v1(1690.19,1230.58)
  Bottom Layer w9: C61.1@746.18,1021.58 C60.1@746.19,1176.59 783.2,1176.59 R11.1@786.19,1179.58 ; C62.1@1022.2,1182.58 1026.18,1182.58 C58.1@1062.18,1146.58 1095.67,1146.58 v1(1111.46,1130.8) ; C41.1@1062.18,1253.58 1069.13,1260.52 v1(1069.13,1273.29)
  Bottom Layer w10: v1(1326.19,1199.58) C18.1@1342.16,1199.59 ; v1(1604.19,989.58) 1613.19,980.58 R26.2@1613.19,959.58
  Bottom Layer w13: C46.1@745.18,1442.58 745.68,1442.08 745.68,1403.08 C40.1@746.18,1402.58 C64.1@746.2,1366.58 C34.1@746.2,1329.58 C59.1@746.19,1293.57 ; v1(1007.59,1552.58) 1010.77,1549.4 C44.1@1010.77,1533.73 ; C51.1@1056.46,1533.73 1066.98,1544.25 v1(1066.98,1552.58) ; v1(1224.19,1368.58) 1224.19,1343.57 C65.1@1230.18,1337.58
  Bottom Layer w15: C58.1@1062.18,1146.58 1101.19,1107.57 v1(1101.19,1054.58) ; C18.1@1342.16,1199.59 C20.1@1342.16,1238.59 1342.16,1263.87 v1(1348.64,1270.35) ; R6.2@1476.55,1142.28 1487.33,1153.06 C24.1@1487.33,1168.44 ; C96.1@1670.18,1046.58 1670.18,1050.59 v1(1654.19,1066.58) 1671.18,1083.57 C26.1@1671.18,1096.58
  Bottom Layer w18: v1(1527.73,1116.69) 1549.19,1095.24 R32.1@1549.19,1089.58 ; v1@1532.3,1116.69 C97.2@1546.04,1130.43
  other v1: 750.19,243.58 814.19,243.58 633.19,428.58 1407.19,589.58 461.19,594.58 1651.19,833.58 1774.19,1006.58 1246.19,1167.58 1193.46,1242.11 2195.19,1248.58 1927.19,1330.58 323.19,1487.33 323.19,1529.58 323.19,1584.58 323.19,1632.58 477.33,1709.14 224.19,1720.58
  other v2: 240.19,71.58 480.19,71.58 600.19,71.58 960.19,71.58 1080.19,71.58 1800.19,71.58 1920.19,71.58 2040.19,71.58 2160.19,71.58 240.19,191.58 960.19,191.58 1080.19,191.58 1320.19,191.58 1423.19,191.58 1680.19,191.58 2280.19,191.58 2517.19,191.58 1616.19,273.58 2400.19,289.58 2517.19,289.58 120.19,311.58 360.19,311.58 960.19,311.58 1200.19,311.58 2160.19,311.58 1619.19,379.58 120.19,431.58 1680.19,431.58 2160.19,431.58 2280.19,431.58 2517.19,478.58 1313.19,536.58 780.19,546.58 841.19,546.58 120.19,551.58 1680.19,551.58 2280.19,551.58 120.19,671.58 2517.19,677.58 1066.19,693.58 1206.19,693.58 120.19,791.58 240.19,791.58 720.19,791.58 713.19,841.58 1960.78,842.58 1988.19,842.58 2018.19,842.58 2048.19,842.58 2410.19,871.58 2430.19,871.58 2450.19,871.58 2470.19,871.58 2490.19,871.58 2510.19,871.58 1960.78,872.58 1988.19,872.58 2018.19,872.58 2048.19,872.58 1960.78,902.58 1988.19,902.58 2048.19,902.58 120.19,911.58 480.19,911.58 2225.26,929.95 2250.4,929.95 2275.54,929.95 2300.68,929.95 2325.81,929.95 2350.95,929.95 1960.78,932.58 1988.19,932.58 2048.19,932.58 2387.19,952.08 2387.19,972.58 2387.19,993.08 2387.19,1013.58 120.19,1031.58 360.19,1031.58 480.19,1031.58 600.19,1031.58 2387.19,1034.58 2388.19,1054.58 360.19,1151.58 480.19,1151.58 2520.19,1154.58 480.19,1271.58 2160.19,1271.58 2280.19,1271.58 2400.19,1271.58 2520.19,1273.58 598.19,1301.58 664.19,1346.58 120.19,1391.58 480.19,1391.58 600.19,1391.58 2520.19,1392.58 660.19,1437.58 600.19,1511.58 720.19,1511.58 1920.19,1511.58 2400.19,1511.58 2520.19,1511.58 2160.19,1631.58 2280.19,1631.58 2400.19,1631.58 2520.19,1631.58 360.19,1751.58 600.19,1751.58 720.19,1751.58 1200.19,1751.58 1800.19,1751.58 1920.19,1751.58 2160.19,1751.58 2280.19,1751.58 2400.19,1751.58 2520.19,1751.58 120.19,1871.58 240.19,1871.58 360.19,1871.58 480.19,1871.58 600.19,1871.58 960.19,1871.58 1080.19,1871.58 1200.19,1871.58 1320.19,1871.58 1680.19,1871.58 1920.19,1871.58 2160.19,1871.58 2280.19,1871.58 2520.19,1871.58 1537.19,1924.58 240.19,1991.58 2520.19,1991.58 240.19,2111.58
H5V: D22.1 HDMIOUT.18 R41.1 R47.1 | length 269.2
  Top Layer w10: HDMIOUT.18@1805.68,363.29 1805.68,412.09 1759.69,458.08 D22.1@1733.39,458.08 1762.89,487.58 R41.1@1850.19,487.58
HCEC: R38.1 U2.G17 | length 774
  Top Layer w4: U2.G17@1514.94,1052.72 U2.G17@1516.05,1052.72 ; U2.G17@1515.55,1053.22 U2.G17@1516.05,1052.72 ; v1@1526.19,1041.58 v1(1527.19,1041.58) U2.G17@1516.05,1052.72
  Bottom Layer w4: v1(1527.19,1041.58) 1551.19,1041.58 1571.19,1021.58 1571.19,750.58 1794.19,527.58 1857.18,527.58 R38.1@1895.19,489.58
HDCEC: HDMIOUT.13 R37.2 R38.2 | length 116.3
  Top Layer w5: R37.2@1894.19,451.58 1904.12,441.65 HDMIOUT.13@1904.12,363.29
  Bottom Layer w4: R38.2@1895.19,453.58 1895.19,442.29 v1(1904.12,433.36)
HDHPD: HDMIOUT.19 R39.2 | length 158.6
  Top Layer w4: v1(1751.19,426.58) 1766.19,426.58 1785.99,406.78 HDMIOUT.19@1785.99,363.29
  Bottom Layer w4: v1(1751.19,426.58) 1751.19,443.58 1758.19,450.58 1799.19,450.58 R39.2@1802.19,453.58
HDMI_0N: D21.2 D21.9 HDMIOUT.9 U2.E20 | length 936.1
  Top Layer w4: U2.E20@1566.12,975.95 1570.19,971.87 1570.19,784.58 1788.19,566.58 1949.58,566.58 1953.58,562.58 1953.58,552.58 1957.58,548.58 1962.58,548.58 1966.58,552.58 1966.58,562.58 1970.58,566.58 1977.19,566.58 1999.19,544.58 1999.19,515.58 1993.49,509.88 D21.2@1993.49,493.18
  Top Layer w5: HDMIOUT.9@1982.88,363.29 1982.88,417.27 1993.49,427.88 D21.9@1993.49,458.58 D21.2@1993.49,493.18
HDMI_0P: D21.1 D21.10 HDMIOUT.7 U2.E19 | length 937.9
  Top Layer w4: U2.E19@1566.12,1001.54 1578.19,989.46 1578.19,787.89 1791.5,574.58 1980.5,574.58 2007.19,547.89 2007.19,515.58 2013.19,509.58 D21.1@2013.19,493.18
  Top Layer w5: D21.1@2013.19,493.18 D21.10@2013.19,458.58 2013.19,427.58 2022.26,418.51 HDMIOUT.7@2022.26,363.29
HDMI_1N: D19.5 D19.6 HDMIOUT.6 U2.D21 | length 943
  Top Layer w4: U2.D21@1591.71,950.35 1594.69,947.36 1594.69,802.08 1798.19,598.58 2022.88,598.58 2038.69,582.77 2038.69,577.11 2032.5,570.92 2032.5,565.27 2036.04,561.73 2041.7,561.73 2047.88,567.92 2053.54,567.92 2058.53,562.92 2058.53,514.92 2051.79,508.18 D19.5@2051.79,492.88
  Top Layer w5: HDMIOUT.6@2041.94,363.29 2041.94,417.33 2051.79,427.18 D19.6@2051.79,458.28 D19.5@2051.79,492.88
HDMI_1P: D19.4 D19.7 HDMIOUT.4 U2.D20 | length 947.1
  Top Layer w4: U2.D20@1591.71,975.95 1603.19,964.46 1603.19,804.89 1801.5,606.58 2026.19,606.58 2066.53,566.24 2066.53,514.24 2071.49,509.28 D19.4@2071.49,492.88
  Top Layer w5: D19.4@2071.49,492.88 D19.7@2071.49,458.28 2071.49,428.28 2081.32,418.45 HDMIOUT.4@2081.32,363.29
HDMI_2N: D19.2 D19.9 HDMIOUT.3 U2.C20 | length 1000.8
  Top Layer w4: U2.C20@1617.3,975.95 1622.19,971.05 1622.19,819.58 1811.19,630.58 2064.19,630.58 2074.27,620.5 2074.27,614.84 2071.93,612.5 2071.93,606.84 2075.46,603.31 2081.12,603.31 2083.46,605.65 2089.12,605.65 2092.66,602.11 2092.66,596.46 2090.31,594.11 2090.31,588.46 2093.85,584.92 2099.5,584.92 2101.85,587.27 2107.5,587.27 2116.74,578.03 2116.74,513.13 2110.89,507.28 D19.2@2110.89,492.88
  Top Layer w5: HDMIOUT.3@2101.01,363.29 2101.01,418.4 2110.89,428.28 D19.9@2110.89,458.28 D19.2@2110.89,492.88
HDMI_2P: D19.1 D19.10 HDMIOUT.1 U2.C19 | length 1003.1
  Top Layer w4: U2.C19@1617.3,1001.54 1630.19,988.64 1630.19,822.89 1814.5,638.58 2067.5,638.58 2124.74,581.34 2124.74,514.03 2130.59,508.18 D19.1@2130.59,492.88
  Top Layer w5: D19.1@2130.59,492.88 D19.10@2130.59,458.28 2130.59,428.18 2140.39,418.38 HDMIOUT.1@2140.39,363.29
HDMI_CN: D21.5 D21.6 HDMIOUT.12 U2.F21 | length 880.3
  Top Layer w4: U2.F21@1540.53,950.35 1544.19,946.68 1544.19,768.58 1777.19,535.58 1840,535.58 1844,531.58 1844,529.58 1848,525.58 1853,525.58 1857,529.58 1857,531.58 1861,535.58 1866,535.58 1870,531.58 1870,529.58 1874,525.58 1879,525.58 1883,529.58 1883,531.58 1887,535.58 1892,535.58 1896,531.58 1896,529.58 1900,525.58 1905,525.58 1909,529.58 1909,531.58 1913,535.58 1929.19,535.58 1940.19,524.58 1940.19,515.58 1934.39,509.78 D21.5@1934.39,493.18
  Top Layer w5: HDMIOUT.12@1923.81,363.29 1923.81,417.2 1934.39,427.78 D21.6@1934.39,458.58 D21.5@1934.39,493.18
HDMI_CP: D21.4 D21.7 HDMIOUT.10 U2.F20 | length 876.8
  Top Layer w4: U2.F20@1540.53,975.95 1552.19,964.28 1552.19,771.89 1780.5,543.58 1932.5,543.58 1948.19,527.89 1948.19,515.58 1954.09,509.68 D21.4@1954.09,493.18
  Top Layer w5: D21.4@1954.09,493.18 D21.7@1954.09,458.58 1954.09,427.68 1963.19,418.58 HDMIOUT.10@1963.19,363.29
HDSCL: HDMIOUT.15 R41.2 R42.2 | length 121
  Top Layer w5: R41.2@1850.19,451.58 1850.19,442.58 1864.75,428.02 HDMIOUT.15@1864.75,363.29
  Bottom Layer w4: R42.2@1850.19,453.58 1850.19,442.58 v1(1861.27,431.5)
HDSDA: HDMIOUT.16 R45.2 R47.2 | length 597.6
  Top Layer w5: R47.2@1806.19,451.58 1809.19,451.58 1845.06,415.71 HDMIOUT.16@1845.06,363.29
  Top Layer w6: R45.2@1677.19,580.58 1702.19,555.59 1702.19,445.58 1738.19,409.58 1738.19,306.58 1766.19,278.58 1826.19,278.58 1845.19,297.58 1845.19,363.16 HDMIOUT.16@1845.06,363.29
HHPD: R39.1 U2.G18 | length 663.6
  Top Layer w4: U2.G18@1514.94,1027.13 1527.36,1014.7 v1(1527.36,989)
  Bottom Layer w4: v1(1527.36,989) 1527.36,971.41 1542.19,956.58 1542.19,737.58 1790.19,489.58 R39.1@1802.19,489.58
HSCL: R42.1 U2.F19 | length 679.9
  Top Layer w4: U2.F19@1540.53,1001.24 U2.F19@1540.53,1001.54 1552.19,989.87 v1(1552.19,989.58) U2.F19@1540.53,1001.24
  Bottom Layer w4: v1(1552.19,989.58) 1556.19,985.58 1556.19,744.58 1788.19,512.58 1827.18,512.58 R42.1@1850.19,489.58
HSDA: R45.1 U2.G21 | length 422.1
  Top Layer w4: U2.G21@1514.94,950.35 1530.19,935.09 1530.19,750.58 1641.19,639.58 R45.1@1641.19,580.58
HXIN: C94.1 U2.B11 X2.1 | length 256.7
  Top Layer w4: U2.B11@1642.89,1206.26 1648.56,1200.58 1662.19,1200.58 1673.19,1211.58 1749.19,1211.58 1765.19,1227.58 1765.19,1245.58 1778.19,1258.58 1828.19,1258.58 1846.19,1240.58 C94.1@1846.19,1231.57
HXOUT: C99.1 U2.C12 X2.3 | length 253.3
  Top Layer w4: U2.C12@1617.3,1180.67 1629.21,1192.58 1667.19,1192.58 1677.19,1202.58 1780.19,1202.58 1805.19,1177.58 C99.1@1805.19,1131.59
IRQ: R4.1 U2.C1 | length 2517.1
  Top Layer w5: v1(444.19,362.58) 467.35,362.58 R4.1@472.63,367.86 ; U2.C1@1617.3,1462.17 1628.71,1473.58 v1(1629.19,1473.58)
  Mid-Layer 4 w7: v1(444.19,362.58) 444.19,325.58 483.19,286.58 743.19,286.58 765.19,308.58 873.19,308.58 996.19,431.58 1123.19,431.58 1138.19,416.58 1429.19,416.58 1805.19,792.58 1805.19,1086.58 1861.19,1142.58 1861.19,1298.58 1686.19,1473.58 v1(1629.19,1473.58)
LL: C89.1 R27.2 U2.G19 | length 392.5
  Top Layer w4: 1490.19,939.58 1490.19,954.58 1500.19,964.58 1500.19,986.79 U2.G19@1514.94,1001.54
  Top Layer w10: R27.2@1423.76,689.58 1431.91,689.58 1448.19,705.86 1448.19,818.58 1490.19,860.58 1490.19,939.58 ; C89.1@1426.55,646.23 R27.2@1426.55,684.22
LPCLK: U2.C8 | length 18.8
  Top Layer w5: U2.C8@1617.3,1283.03 1630.19,1270.13 v1(1630.19,1269.58)
LR: C91.1 R29.2 U2.G20 | length 351.9
  Top Layer w4: 1508.37,933.4 1502.19,939.58 1502.19,952.58 1514.94,965.33 U2.G20@1514.94,975.95
  Top Layer w10: C91.1@1472.55,646.23 1472.55,684.22 1498.19,709.86 1498.19,811.58 1507.19,820.58 1507.19,933.4
NetAUDIO1_2: AUDIO1.2 AUDIO1.5 C89.2 D8.2 | length 531.6
  Top Layer w10: C89.2@1386.55,646.23 1386.55,642.22 1408.19,620.58 1444.19,620.58 1460.19,604.58 1460.19,582.18 1518.19,524.18 1518.19,466.58 1535.69,449.08 AUDIO1.5@1535.69,420.68
  Bottom Layer w10: AUDIO1.2@1346.69,338.08 1371.69,338.08 1454.29,420.68 AUDIO1.5@1535.69,420.68
NetAUDIO1_3: AUDIO1.3 AUDIO1.6 C91.2 D10.2 | length 587.1
  Top Layer w10: C91.2@1512.56,646.23 1520.19,638.59 1520.19,582.18 1548.19,554.18 1548.19,481.58 1577.19,452.58 1577.19,363.78 AUDIO1.3@1535.69,322.28
  Bottom Layer w10: AUDIO1.6@1346.69,249.48 1400.09,249.48 1472.89,322.28 AUDIO1.3@1535.69,322.28
NetC5_2: C5.2 R1.2 U1.7 | length 125.9
  Top Layer w6: R1.2@401.63,533.86 414.05,521.44 ; C5.2@404.2,490.58 404.2,511.59 414.05,521.44 ; U1.7@477.21,546.2 438.81,546.2 414.05,521.44
NetC12_2: C12.2 U1.8 | length 134.2
  Top Layer w6: C12.2@404.2,450.58 417.19,450.58 435.19,468.58 435.19,516.58 449.11,530.5 U1.8@477.21,530.5
NetC82_2: C82.2 C83.2 U4.C2 | length 238.1
  Top Layer w3.5: 2039.19,1332.58 2049.19,1322.58 2058.19,1331.58 2058.19,1356.73 U4.C2@2048.61,1366.32 2039.19,1356.9 2039.19,1332.58
  Top Layer w8: 2049.19,1322.58 2049.19,1212.59 C83.2@2074.06,1212.59
NetC87_1: C87.1 R28.2 RESET.1 RESET.2 | length 276
  Top Layer w10: RESET.1@434.51,1174.9 435.49,1173.88 649.89,1173.88 C87.1@664.19,1159.59 R28.2@664.19,1119.58
NetC88_2: C88.2 R27.1 | length 28
  Top Layer w10: C88.2@1423.19,753.33 1423.76,752.76 R27.1@1423.76,725.58
NetC90_2: C90.2 R29.1 | length 37
  Top Layer w10: R29.1@1472.55,720.23 C90.2@1472.55,757.22
NetC92_2: C92.2 U2.J18 | length 17.3
  Top Layer w8: v1(1451.2,1015.58) 1452.21,1015.58 U2.J18@1463.76,1027.13
NetC93_2: C93.2 U2.J17 | length 17.3
  Top Layer w8: v1(1450.96,1041.88) 1452.92,1041.88 U2.J17@1463.76,1052.72
NetC95_2: C95.2 U2.D18 | length 18.6
  Top Layer w8: U2.D18@1591.71,1027.13 1604.19,1039.61 v1(1604.19,1040.58)
NetC96_2: C96.2 U2.C17 | length 38.4
  Top Layer w8: U2.C17@1617.3,1052.72 v1(1630.19,1065.58)
  Bottom Layer w8: v1(1630.19,1065.58) 1633.18,1062.59 C96.2@1633.18,1046.58
NetC97_1: C97.1 U2.D13 | length 53.2
  Top Layer w8: U2.D13@1591.71,1155.08 1592.69,1155.08 v1(1605.19,1167.58)
  Bottom Layer w18: C97.1@1574.33,1158.72 1583.19,1167.58 v1(1605.19,1167.58)
NetC109_1: C109.1 C110.1 C119.1 L7.2 | length 118.8
  Top Layer w5: C109.1@2222.2,846.58 2252.64,846.58 2259.84,839.38 2259.84,877.78 2291.75,877.78 L7.2@2297.35,883.38
NetC110_2: C110.2 C112.1 C123.1 L6.2 | length 117.3
  Top Layer w5: L6.2@2222.2,772.58 C123.1@2222.2,809.58 2251.64,809.58 2259.84,817.78 2296.02,817.78 C112.1@2298.22,815.58
NetC112_2: C112.2 C113.2 L7.1 L8.2 | length 127.9
  Top Layer w5: L7.1@2297.35,861.78 2326.89,861.78 L8.2@2334.84,853.83 2334.84,830.6 2319.82,815.58 2329.19,806.21 2329.19,778.2 C113.2@2330.19,777.2
NetC113_1: C113.1 C114.2 | length 37
  Top Layer w5: C114.2@2292.19,755.6 C113.1@2329.19,755.6
NetD1_1: D1.1 FAN1.1 | length 92.9
  Top Layer w17: FAN1.1@1082.99,486.48 1082.99,452.78 1093.19,442.58 D1.1@1137.99,442.58
NetD20_1: D20.1 R33.1 R34.2 | length 88.3
  Top Layer w7: R33.1@1045.82,394.28 1045.69,394.15 D20.1@1045.69,349.58 R34.2@1089.19,349.58
NetD23_1: D23.1 R37.1 | length 183.5
  Top Layer w5: D23.1@1733.39,522.58 1762.19,522.58 1772.19,512.58 1883.19,512.58 1894.19,501.58 R37.1@1894.19,487.58
NetL1_1: L1.1 U1.18
NetL2_1: L2.1 U1.19
NetL3_1: L3.1 U1.3
NetL9_2: L9.2 U5.15 | length 131.6
  Top Layer w7: L9.2@1859.92,1035.13 1933.63,1035.13 1953.19,1015.58 1953.19,985.98 U5.15@1953.63,985.54
NetLED1_1: LED1.1 R48.1 | length 43
  Top Layer w8: LED1.1@2433.19,1849.11 2433.27,1849.03 R48.1@2476.19,1849.03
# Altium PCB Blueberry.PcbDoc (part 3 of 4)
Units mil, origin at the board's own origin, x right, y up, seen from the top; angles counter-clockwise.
Board outline 2559.06 x 2204.72 mil, 6 copper layers (Top Layer, Mid-Layer 1, Mid-Layer 2, Mid-Layer 3, Mid-Layer 4, Bottom Layer); 211 components, 214 nets, 1171 pads, 598 vias.

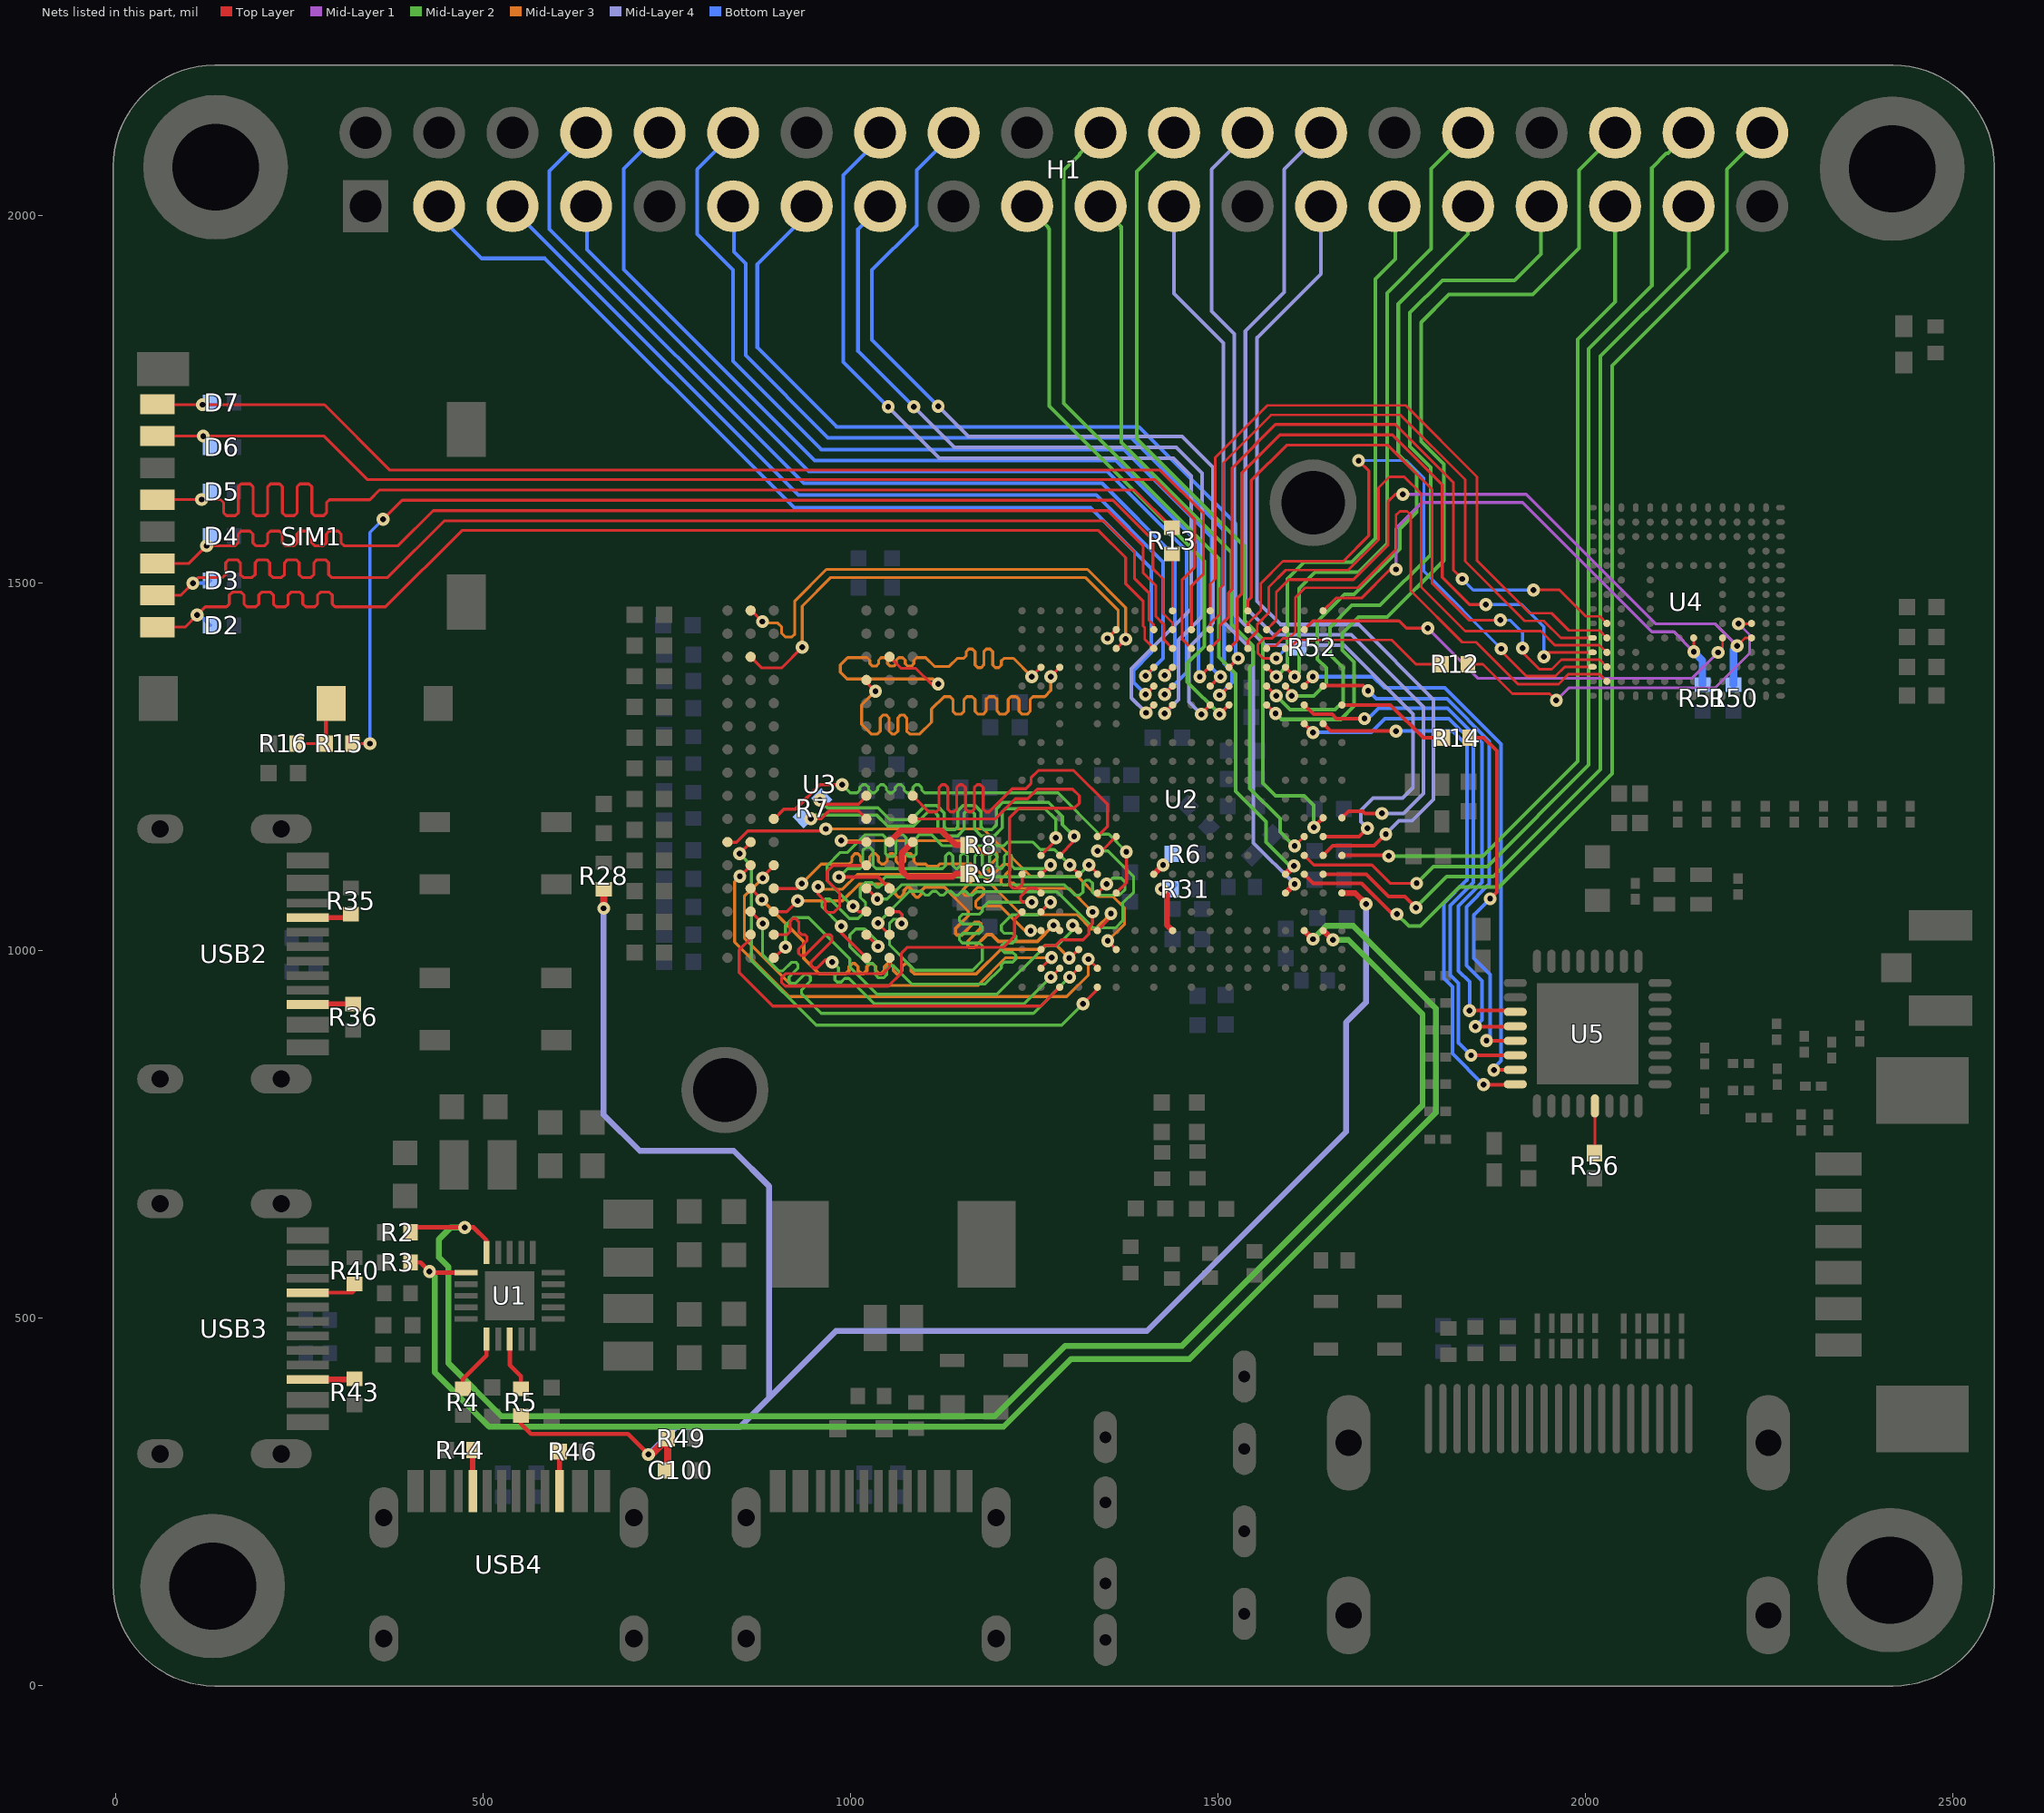
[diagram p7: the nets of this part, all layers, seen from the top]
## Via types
v1: diameter 17.7, hole 7.9, Top Layer to Bottom Layer, 439 vias
v2: diameter 18, hole 8, Top Layer to Bottom Layer, 138 vias
v3: diameter 24, hole 15, Top Layer to Bottom Layer, 19 vias
v4: diameter 24, hole 12, Top Layer to Bottom Layer, 2 vias

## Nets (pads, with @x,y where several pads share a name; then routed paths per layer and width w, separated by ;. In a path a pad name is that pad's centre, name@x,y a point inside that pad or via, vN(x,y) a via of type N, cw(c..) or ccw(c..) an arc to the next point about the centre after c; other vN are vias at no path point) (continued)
NetR4_2: R4.2 U1.11 | length 80.9
  Top Layer w6: R4.2@472.63,403.86 472.63,417.02 504.81,449.2 U1.11@504.81,471.4
NetR5_2: R5.2 U1.13 | length 73.9
  Top Layer w6: U1.13@536.31,471.4 536.31,436.46 551.63,421.14 R5.2@551.63,403.86
NetR6_1: R6.1 U2.L15 | length 17.9
  Top Layer w8: U2.L15@1412.57,1103.9 v1@1425.19,1116.52
  other v1: 1425.19,1116.58
NetR8_2: R8.2 U3.L8 | length 121
  Top Layer w8: U3.L8@1053.06,1147.66 1068.98,1163.58 1123.18,1163.58 1143.19,1143.58 R8.2@1159.19,1143.58
NetR9_2: R9.2 U3.L9 | length 139.8
  Top Layer w8: U3.L9@1084.56,1147.66 1069.19,1132.29 1069.19,1109.58 1078.19,1100.58 1139.19,1100.58 1143.19,1104.58 R9.2@1159.19,1104.58
NetR12_2: R12.2 U2.D3 | length 231
  Top Layer w3.5: U2.D3@1591.71,1410.98 1596.31,1415.58 1601.19,1415.58 1608.19,1422.58 1736.19,1422.58 1769.19,1389.58 R12.2@1804.19,1389.58
NetR13_2: R13.2 U2.K1 | length 77.8
  Top Layer w4: R13.2@1437.19,1539.58 1438.16,1538.61 U2.K1@1438.16,1462.17
NetR14_2: R14.2 U2.A6 | length 156.2
  Top Layer w5: U2.A6@1668.48,1334.21 1734.56,1334.21 1779.19,1289.58 R14.2@1806.19,1289.58
NetR15_2: R15.2 R16.2 SIM1.11 | length 97.7
  Top Layer w4: R16.2@246.19,1281.58 R15.2@286.19,1281.58
  Top Layer w6: R15.2@286.19,1281.58 286.19,1329.23 SIM1.11@293.28,1336.32
NetR31_2: R31.2 U2.K18 | length 82.1
  Top Layer w8: v1(1423.19,1083.58) 1430.19,1076.58 1430.19,1035.09 U2.K18@1438.16,1027.13
  Bottom Layer w8: v1(1423.19,1083.58) 1434.18,1083.58 R31.2@1440.19,1089.58
NetR35_2: R35.2 USB2.A5 | length 60.7
  Top Layer w7: USB2.A5@261.49,1044.78 315.39,1044.78 R35.2@320.19,1049.58
NetR36_1: R36.1 USB2.B5 | length 62.1
  Top Layer w7: USB2.B5@261.49,926.68 262.39,927.58 R36.1@323.19,927.58
NetR40_2: R40.2 USB3.A5 | length 67.7
  Top Layer w5: USB3.A5@261.49,534.78 322.39,534.78 R40.2@327.19,539.58
NetR43_1: R43.1 USB3.B5 | length 64.1
  Top Layer w8: USB3.B5@261.49,416.68 318.28,416.68 319.18,417.58 R43.1@325.19,417.58
NetR44_2: R44.2 USB4.A5 | length 54.4
  Top Layer w7: R44.2@484.19,318.58 485.99,316.78 USB4.A5@485.99,264.88
NetR46_1: R46.1 USB4.B5 | length 53.7
  Top Layer w7: USB4.B5@604.09,264.88 604.19,264.98 R46.1@604.19,318.58
NetR52_1: R52.1 U2.D2 | length 122.9
  Top Layer w4: v1(1579.19,1397.58) 1561.19,1397.58 1554.19,1404.58 1554.19,1416.58 1562.19,1424.58 1573.19,1424.58 1585.18,1436.57 U2.D2@1591.71,1436.57
  Bottom Layer w4: v1(1579.19,1397.58) 1594.19,1412.58 R52.1@1610.19,1412.58
NetR56_1: R56.1 U5.29 | length 64.3
  Top Layer w4: R56.1@2012.19,724.62 2012.69,725.12 U5.29@2012.69,788.69
PH0: H1.23 U2.D16 | length 1007.5
  Top Layer w8: U2.D16@1591.71,1078.31 1603.98,1090.58 v1(1604.19,1090.58)
  Mid-Layer 4 w5: H1.23@1440.19,2012.58 1440.19,1893.58 1507.19,1826.58 1507.19,1447.58 1548.19,1406.58 1548.19,1146.58 v1(1604.19,1090.58)
PH1: H1.22 U2.D15 | length 1167.4
  Top Layer w8: U2.D15@1591.71,1103.9 v1(1603.19,1115.38) v1@1603.19,1115.58
  Mid-Layer 2 w5: H1.22@1340.19,2112.58 1311.38,2083.77 1311.38,2082.77 1290.19,2061.58 1290.19,1744.58 1501.19,1533.58 1501.19,1399.58 1524.19,1376.58 1524.19,1216.58 1565.19,1175.58 1565.19,1147.58 1597.39,1115.38 v1(1603.19,1115.38)
PH2: H1.37 U2.B15 | length 1289.7
  Top Layer w5: U2.B15@1642.89,1103.9 1701.87,1103.9 1732.19,1073.58 1754.19,1073.58 v1(1769.19,1058.58)
  Mid-Layer 2 w5: v1(1769.19,1058.58) 1811.19,1100.58 1874.19,1100.58 2020.19,1246.58 2020.19,1808.58 2140.19,1928.58 H1.37@2140.19,2012.58
PH3: H1.40 U2.C15 | length 1490.6
  Top Layer w5: U2.C15@1617.3,1103.9 1629.61,1091.58 1695.19,1091.58 1737.19,1049.58 v1(1743.19,1049.58)
  Mid-Layer 2 w5: v1(1743.19,1049.58) 1759.54,1033.23 1774.84,1033.23 1828.19,1086.58 1882.19,1086.58 2036.19,1240.58 2036.19,1795.58 2192.19,1951.58 2192.19,2062.58 2240.19,2110.58 H1.40@2240.19,2112.58
PH4: H1.35 U2.A14 | length 1150.6
  Top Layer w5: U2.A14@1668.48,1129.49 1731.28,1129.49 v1(1732.19,1128.58)
  Mid-Layer 2 w5: v1(1732.19,1128.58) 1860.19,1128.58 1989.19,1257.58 1989.19,1831.58 2040.19,1882.58 H1.35@2040.19,2012.58
PH5: H1.27 U2.B14 | length 1186.4
  Top Layer w5: U2.B14@1642.89,1129.49 1655.98,1142.58 1712.19,1142.58 v1(1728.19,1158.58)
  Mid-Layer 4 w5: H1.27@1640.19,2012.58 1640.19,1920.58 1553.19,1833.58 1553.19,1475.58 1585.19,1443.58 1691.19,1443.58 1793.19,1341.58 1793.19,1205.58 1764.19,1176.58 1746.19,1176.58 v1(1728.19,1158.58)
PH6: H1.38 U2.C14 | length 1386.8
  Top Layer w4: U2.C14@1617.3,1129.49 1630.2,1116.58 1709.19,1116.58 1734.19,1091.58 v1(1770.19,1091.58)
  Mid-Layer 2 w5: v1(1770.19,1091.58) 1793.19,1114.58 1866.19,1114.58 2004.19,1252.58 2004.19,1818.58 2090.19,1904.58 2090.19,2064.58 2109.9,2084.29 2111.9,2084.29 H1.38@2140.19,2112.58
PH7: H1.24 U2.B12 | length 1107.1
  Top Layer w5: v1(1630.19,1167.58) 1630.19,1167.97 U2.B12@1642.89,1180.67
  Mid-Layer 2 w5: H1.24@1440.19,2112.58 1440.19,2110.58 1389.19,2059.58 1389.19,1696.58 1536.19,1549.58 1536.19,1448.58 1561.19,1423.58 1561.19,1227.58 1578.19,1210.58 1617.19,1210.58 1630.19,1197.58 v1(1630.19,1167.58)
PH8: H1.21 U2.C13 | length 1001.9
  Top Layer w4: v1(1604.19,1142.58) 1616.69,1155.08 U2.C13@1617.3,1155.08
  Mid-Layer 2 w5: H1.21@1340.19,2012.58 1368.19,1984.58 1368.19,1981.58 ; 1367.96,1981.81 1368.19,1981.58 ; v1(1604.19,1142.58) 1603.19,1142.58 1584.19,1161.58 1584.19,1179.58 1543.19,1220.58 1543.19,1385.58 1547.19,1389.58 1547.19,1414.58 1518.19,1443.58 1518.19,1541.58 1368.19,1691.58 1368.19,1981.58
PH9: H1.28 U2.A12 | length 1230.8
  Top Layer w5: U2.A12@1668.48,1180.67 1677.39,1189.58 1696.94,1189.58 1699.91,1186.61 v1(1722.89,1186.61)
  Mid-Layer 4 w5: H1.28@1640.19,2112.58 1590.19,2062.58 1590.19,1895.58 1537.19,1842.58 1537.19,1467.58 1575.19,1429.58 1681.19,1429.58 1779.19,1331.58 1779.19,1213.58 1752.22,1186.61 v1(1722.89,1186.61)
PH10: H1.26 U2.B13 | length 1264.1
  Top Layer w5: U2.B13@1642.89,1155.08 1691.69,1155.08 v1(1703.19,1166.58)
  Mid-Layer 4 w5: H1.26@1540.19,2112.58 1540.19,2111.58 1491.19,2062.58 1491.19,1869.58 1522.19,1838.58 1522.19,1457.58 1564.19,1415.58 1671.19,1415.58 1765.19,1321.58 1765.19,1221.58 1751.19,1207.58 1711.19,1207.58 1694.19,1190.58 1694.19,1175.58 v1(1703.19,1166.58)
PI0: H1.18 U2.H6 | length 1238
  Top Layer w4.5: v1(1477.19,1321.58) 1477.19,1322.05 U2.H6@1489.35,1334.21
  Mid-Layer 4 w5: v1(1119.19,1740.58) 1160.19,1699.58 1451.19,1699.58 1493.19,1657.58 1493.19,1445.58 1460.19,1412.58 1460.19,1338.58 v1(1477.19,1321.58)
  Bottom Layer w5: v1(1119.19,1740.58) 1029.19,1830.58 1029.19,1925.58 1090.19,1986.58 1090.19,2061.58 1140.19,2111.58 H1.18@1140.19,2112.58
PI1: H1.32 U2.D4 | length 890.9
  Top Layer w4.5: U2.D4@1591.71,1385.39 1591.71,1385.06 v1(1604.19,1372.58)
  Mid-Layer 2 w5: v1(1604.19,1372.58) 1610.19,1378.58 1610.19,1492.58 1632.19,1514.58 1691.19,1514.58 1730.19,1553.58 1730.19,1894.58 1790.19,1954.58 1790.19,2063.58 1839.19,2112.58 H1.32@1840.19,2112.58
PI2: H1.19 U2.G6 | length 836.6
  Top Layer w4.5: v1(1502.19,1321.58) 1514.82,1334.21 U2.G6@1514.94,1334.21
  Mid-Layer 2 w5: H1.19@1240.19,2012.58 1269,1983.77 1269,1982.77 1270.19,1981.58 1270.19,1740.58 1481.19,1529.58 1481.19,1413.58 1458.19,1390.58 1458.19,1365.58 v1(1502.19,1321.58)
PI3: H1.29 U2.E4 | length 764
  Top Layer w4.5: U2.E4@1566.12,1385.39 1566.38,1385.39 v1(1579.19,1372.58)
  Mid-Layer 2 w5: v1(1579.19,1372.58) 1594.19,1387.58 1594.19,1505.58 1617.19,1528.58 1682.19,1528.58 1714.19,1560.58 1714.19,1913.58 1741.19,1940.58 1741.19,2011.58 H1.29@1740.19,2012.58
PI4: H1.11 U2.G5 | length 1214.4
  Top Layer w4.5: v1(1502.19,1347.58) 1502.72,1347.58 U2.G5@1514.94,1359.8
  Bottom Layer w5: H1.11@839.19,2013.58 841.19,2011.58 841.19,1950.58 857.19,1934.58 857.19,1809.58 969.19,1697.58 1382.19,1697.58 1508.19,1571.58 1508.19,1390.58 1519.19,1379.58 1519.19,1364.58 v1(1502.19,1347.58)
PI5: H1.10 U2.H4 | length 1344.7
  Top Layer w4.5: v1(1475.19,1372.58) 1488,1385.39 U2.H4@1489.35,1385.39
  Bottom Layer w5: H1.10@740.19,2112.58 691.19,2063.58 691.19,1926.58 951.19,1666.58 1361.19,1666.58 1473.19,1554.58 1473.19,1374.58 v1(1475.19,1372.58)
PI6: H1.12 U2.H5 | length 1315.7
  Top Layer w4.5: U2.H5@1489.35,1359.8 1502.13,1372.58 v1(1503.19,1372.58)
  Bottom Layer w5: H1.12@840.19,2112.58 840.19,2111.58 791.19,2062.58 791.19,1974.58 840.19,1925.58 840.19,1801.58 960.19,1681.58 1372.19,1681.58 1491.19,1562.58 1491.19,1384.58 v1(1503.19,1372.58)
PI7: H1.13 U2.G4 | length 1171.7
  Top Layer w4.5: U2.G4@1514.94,1385.33 v1(1527.19,1397.58)
  Bottom Layer w5: H1.13@940.19,2012.58 940.19,2000.58 873.19,1933.58 873.19,1820.58 981.19,1712.58 1392.19,1712.58 1524.19,1580.58 1524.19,1400.58 v1(1527.19,1397.58)
PI8: H1.36 U2.E6 | length 1190.3
  Top Layer w4.5: U2.E6@1566.12,1334.21 1577.74,1322.58 v1(1578.19,1322.58)
  Mid-Layer 2 w5: v1(1578.19,1322.58) 1586.19,1314.58 1667.19,1314.58 1685.19,1332.58 1685.19,1392.58 1669.19,1408.58 1669.19,1431.58 1691.19,1453.58 1730.19,1453.58 1807.19,1530.58 1807.19,1661.58 1776.19,1692.58 1776.19,1854.58 1814.19,1892.58 1928.19,1892.58 1991.19,1955.58 1991.19,2061.58 2040.19,2110.58 H1.36@2040.19,2112.58
PI9: H1.31 U2.D5 | length 837.9
  Top Layer w4.5: U2.D5@1591.71,1359.8 1591.71,1358.31 1600.39,1349.63 v1(1600.39,1346.58)
  Mid-Layer 2 w5: v1(1600.39,1346.58) 1630.19,1346.58 1647.19,1363.58 1647.19,1384.58 1635.19,1396.58 1635.19,1447.58 1672.19,1484.58 1685.19,1484.58 1747.19,1546.58 1747.19,1573.58 1770.19,1596.58 1770.19,1649.58 1745.19,1674.58 1745.19,1879.58 1840.19,1974.58 H1.31@1840.19,2012.58
PI10: H1.3 U2.L5 | length 1384.7
  Top Layer w4: v1(1401.19,1348.58) 1401.35,1348.58 U2.L5@1412.57,1359.8
  Bottom Layer w5: H1.3@440.19,2012.58 440.19,1999.58 498.19,1941.58 584.19,1941.58 923.19,1602.58 1326.19,1602.58 1409.19,1519.58 1409.19,1405.58 1384.84,1381.23 1384.84,1364.93 v1(1401.19,1348.58)
PI11: H1.8 U2.K4 | length 1370.3
  Top Layer w4.5: v1(1427.19,1374.58) 1427.35,1374.58 U2.K4@1438.16,1385.39
  Bottom Layer w5: H1.8@640.19,2112.58 640.19,2110.58 590.19,2060.58 590.19,1981.58 936.19,1635.58 1342.19,1635.58 1441.19,1536.58 1441.19,1388.58 v1(1427.19,1374.58)
PI12: H1.7 U2.K5 | length 1268.4
  Top Layer w4.5: v1(1427.19,1348.58) 1427.19,1348.83 U2.K5@1438.16,1359.8
  Bottom Layer w5: H1.7@640.19,2012.58 641.19,2011.58 641.19,1953.58 943.19,1651.58 1349.19,1651.58 1457.19,1543.58 1457.19,1378.58 v1(1427.19,1348.58)
PI13: H1.33 U2.E5 | length 1025.7
  Top Layer w4.5: U2.E5@1566.12,1359.8 1579.19,1346.72 v1(1579.19,1346.58)
  Mid-Layer 2 w5: v1(1579.19,1346.58) 1598.19,1327.58 1659.19,1327.58 1670.19,1338.58 1670.19,1384.58 1652.19,1402.58 1652.19,1439.58 1682.19,1469.58 1720.19,1469.58 1789.19,1538.58 1789.19,1657.58 1761.19,1685.58 1761.19,1867.58 1805.19,1911.58 1903.19,1911.58 1939.19,1947.58 1939.19,2011.58 H1.33@1940.19,2012.58
PI14: H1.16 U2.L6 | length 1248.7
  Top Layer w4.5: v1(1402.19,1323.58) 1402.19,1323.83 U2.L6@1412.57,1334.21
  Mid-Layer 4 w5: v1(1051.19,1739.58) 1121.19,1669.58 1439.19,1669.58 1463.19,1645.58 1463.19,1464.58 1382.19,1383.58 1382.19,1343.58 v1(1402.19,1323.58)
  Bottom Layer w5: H1.16@1040.19,2112.58 1040.19,2104.58 990.19,2054.58 990.19,1800.58 v1(1051.19,1739.58)
PI15: H1.5 U2.L4 | length 1269.3
  Top Layer w4: v1(1401.19,1373.58) 1401.19,1374.01 U2.L4@1412.57,1385.39
  Bottom Layer w5: H1.5@540.19,2012.58 540.19,2008.58 929.19,1619.58 1334.19,1619.58 1425.19,1528.58 1425.19,1397.58 v1(1401.19,1373.58)
PI16: H1.15 U2.K6 | length 1110.5
  Top Layer w4.5: v1(1427.19,1322.58) 1427.19,1323.24 U2.K6@1438.16,1334.21
  Mid-Layer 4 w5: v1(1086.19,1739.58) 1141.19,1684.58 1443.19,1684.58 1478.19,1649.58 1478.19,1454.58 1446.19,1422.58 1446.19,1341.58 v1(1427.19,1322.58)
  Bottom Layer w5: H1.15@1040.19,2012.58 1040.19,2011.58 1010.19,1981.58 1010.19,1815.58 v1(1086.19,1739.58)
PMU_SCK: R3.2 U1.6 U2.C18 | length 2170.3
  Top Layer w6: R3.2@401.63,575.86 414.91,575.86 v1(427.19,563.58) 428.77,562 U1.6@477.21,562
  Top Layer w8: U2.C18@1617.3,1027.13 1628.84,1015.58 v1(1629.19,1015.58)
  Mid-Layer 2 w8: v1(427.19,563.58) 434.19,556.58 434.19,426.58 508.19,352.58 1208.19,352.58 1300.19,444.58 1461.19,444.58 1796.19,779.58 1796.19,921.58 1684.19,1033.58 1647.19,1033.58 v1(1629.19,1015.58)
PMU_SDA: R2.2 U1.5 U2.B18 | length 2181.8
  Top Layer w6: R2.2@401.63,616.86 408.35,623.58 v1(475.03,623.58) 487.19,623.58 504.81,605.96 U1.5@504.81,589.6
  Top Layer w8: U2.B18@1642.89,1027.13 1643.64,1027.13 v1(1656.19,1014.58)
  Mid-Layer 2 w8: v1(475.03,623.58) 456.19,623.58 440.19,607.58 440.19,582.58 453.19,569.58 453.19,438.58 525.19,366.58 1196.19,366.58 1292.19,462.58 1451.19,462.58 1778.19,789.58 1778.19,913.58 1677.19,1014.58 v1(1656.19,1014.58)
RESET: C100.2 R5.1 R28.1 R49.1 U2.A16 | length 2633.3
  Top Layer w6: R5.1@551.63,367.86 551.63,356.14 565.19,342.58 697.19,342.58 v1(725.19,314.58)
  Top Layer w8: U2.A16@1668.48,1078.31 1686.46,1078.31 v1(1701.19,1063.58)
  Top Layer w10: v1(664.19,1057.58) R28.1@664.19,1083.58 ; v1(725.19,314.58) 729.19,314.58 R49.1@751.19,336.58 751.19,295.14 C100.2@748.99,292.94
  Mid-Layer 4 w8: v1(664.19,1057.58) 664.19,776.58 713.19,727.58 841.19,727.58 889.04,679.73 889.04,391.43 ; v1(725.19,314.58) 762.19,351.58 849.19,351.58 889.04,391.43 ; v1(1701.19,1063.58) 1701.19,929.58 1674.19,902.58 1674.19,753.58 1403.19,482.58 980.19,482.58 889.04,391.43
SA0: U2.P18 U3.N3 | length 627.4
  Top Layer w4: U3.N3@895.9,1084.31 926.65,1084.31 v1(933.46,1091.11) ; U2.P18@1335.86,1027.23 1354.19,1045.56 v1(1354.19,1050.58)
  Mid-Layer 3 w4: v1(933.46,1091.11) 959.92,1117.58 997.93,1117.58 1001.93,1121.58 1001.93,1127.8 1005.93,1131.8 1009.93,1131.8 1013.93,1127.8 1013.93,1121.58 1017.93,1117.58 1021.93,1117.58 1025.93,1121.58 1025.93,1127.8 1029.93,1131.8 1033.93,1131.8 1037.93,1127.8 1037.93,1121.58 1041.93,1117.58 1045.93,1117.58 1049.93,1121.58 1049.93,1127.8 1053.93,1131.8 1057.93,1131.8 1061.93,1127.8 1061.93,1121.58 1065.93,1117.58 1069.93,1117.58 1073.93,1121.58 1073.93,1127.8 1077.93,1131.8 1081.93,1131.8 1085.93,1127.8 1085.93,1121.58 1089.93,1117.58 1102.19,1117.58 1105.19,1114.58 1118.19,1114.58 1121.72,1118.11 1163.14,1118.11 1232.32,1048.93 1308.13,1048.93 1327.48,1029.58 1333.19,1029.58 v1(1354.19,1050.58)
  other v1: 1354.19,1050.58
SA1: U2.R15 U3.P7 | length 578.5
  Top Layer w4: v1(1003.46,1060.11) 1010.76,1052.81 U3.P7@1021.88,1052.81 ; v1(1298.19,1116.58) 1310.27,1104.5 U2.R15@1310.27,1104
  Mid-Layer 2 w4: v1(1003.46,1060.11) 1002.66,1060.11 968.19,1094.58 968.19,1115.58 986.19,1133.58 996.19,1133.58 1020.19,1157.58 1043.55,1157.58 1047.55,1153.58 1047.55,1131.8 1051.55,1127.8 1057.55,1127.8 1061.55,1131.8 1061.55,1153.58 1065.55,1157.58 1071.55,1157.58 1075.55,1153.58 1075.55,1131.8 1079.55,1127.8 1085.55,1127.8 1089.55,1131.8 1089.55,1153.58 1093.55,1157.58 1110.19,1157.58 1125.19,1142.58 1208.19,1142.58 1213.19,1147.58 1248.19,1147.58 1258.19,1137.58 1277.19,1137.58 v1(1298.19,1116.58)
  other v1: 1298.19,1116.58
SA2: U2.T18 U3.P3 | length 595.5
  Top Layer w4.5: U3.P3@895.9,1052.81 913.42,1052.81 v1(928.19,1067.58) ; v1(1276.19,1034.58) 1283.54,1027.23 U2.T18@1284.68,1027.23
  Mid-Layer 3 w4.5: v1(928.19,1067.58) 988.92,1067.58 1011.92,1090.58 1051.77,1090.58 1060.74,1081.61 1060.74,1077.21 1065.24,1072.71 1068.24,1072.71 1072.74,1077.21 1072.74,1081.61 1077.24,1086.11 1080.24,1086.11 1084.74,1081.61 1084.74,1077.21 1089.24,1072.71 1092.24,1072.71 1096.74,1077.21 1096.74,1081.61 1101.24,1086.11 1127.66,1086.11 1160.18,1053.59 1160.18,1047.23 1142.64,1029.69 1142.64,1023.32 1144.76,1021.2 1151.13,1021.2 1168.67,1038.74 1175.03,1038.74 1177.15,1036.62 1177.15,1030.26 1159.61,1012.71 1159.61,1006.35 1161.73,1004.23 1168.1,1004.23 1185.64,1021.77 1192,1021.77 1201.19,1012.58 1254.19,1012.58 v1(1276.19,1034.58)
SA3: U2.R19 U3.N2 | length 605.8
  Top Layer w4.5: U3.N2@864.4,1084.31 v1(879.46,1069.25) ; v1@1296.46,989.8 1298.43,989.8 U2.R19@1310.27,1001.64
  Mid-Layer 3 w4.5: v1(879.46,1069.25) 936.46,1012.25 936.46,989.31 957.19,968.58 993.66,968.58 998.16,973.08 998.16,978.08 1002.66,982.58 1005.66,982.58 1010.16,978.08 1010.16,973.08 1014.66,968.58 1017.66,968.58 1022.16,973.08 1022.16,978.08 1026.66,982.58 1029.66,982.58 1034.16,978.08 1034.16,973.08 1038.66,968.58 1041.66,968.58 1046.16,973.08 1046.16,978.08 1050.66,982.58 1053.66,982.58 1058.16,978.08 1058.16,973.08 1062.66,968.58 1065.66,968.58 1070.16,973.08 1070.16,978.08 1074.66,982.58 1077.66,982.58 1082.16,978.08 1082.16,973.08 1086.66,968.58 1171.19,968.58 1204.41,1001.8 1259.41,1001.8 1264.41,1006.8 1280.44,1006.8 v1(1297.44,989.8)
  other v1: 1297.44,989.8
SA4: U2.U16 U3.P8 | length 530.8
  Top Layer w4: U3.P8@1053.38,1052.81 1066.26,1052.81 1069.96,1049.11 1069.96,1037.36 v1(1069.39,1036.8) ; v1(1246.48,1065.8) 1233.77,1065.8 1231.46,1068.11 1231.46,1074.11 1242.46,1085.11 1250.71,1085.11 1251.31,1084.51 1252.98,1084.51 U2.U16@1259.09,1078.41
  Mid-Layer 2 w4: v1(1069.39,1036.8) 1063.61,1042.58 1058.19,1042.58 1053.19,1037.58 1053.19,1007.58 1087.32,973.45 1166.06,973.45 1179.19,986.58 1179.19,1006.37 1175.19,1010.37 1152.18,1010.37 1148.18,1014.37 1148.18,1019.37 1152.18,1023.37 1175.19,1023.37 1179.19,1027.37 1179.19,1032.37 1175.19,1036.37 1152.18,1036.37 1148.18,1040.37 1148.18,1045.37 1152.18,1049.37 1175.19,1049.37 1179.19,1053.37 1179.19,1057.58 1187.41,1065.8 v1(1246.48,1065.8)
SA5: U2.R20 U3.P2 | length 633.7
  Top Layer w4: U3.P2@864.4,1052.81 v1(880.42,1036.8) ; v1(1298.02,963.8) U2.R20@1310.27,976.05
  Mid-Layer 2 w4: v1(880.42,1036.8) 880.42,994.35 902.35,972.42 908.01,972.42 919.85,984.26 925.51,984.26 928.34,981.43 928.34,975.77 916.5,963.93 916.5,958.27 919.32,955.45 924.98,955.45 936.82,967.29 942.48,967.29 945.31,964.46 945.31,958.8 933.47,946.96 933.47,941.3 960.19,914.58 1248.8,914.58 v1(1298.02,963.8)
  other v1: 1298.02,963.8
SA6: U2.N13 U3.R8 | length 577.7
  Top Layer w4: v1(1037.19,1037.58) 1037.19,1037.16 1053.03,1021.32 U3.R8@1053.38,1021.32 ; v1(1336.19,1135.58) 1341.85,1135.58 U2.N13@1361.45,1155.18
  Mid-Layer 2 w4: v1(1037.19,1037.58) 1080.19,1080.58 1096.59,1080.58 1101.59,1075.58 1106.59,1075.58 1111.59,1080.58 1116.59,1080.58 1121.59,1075.58 1126.59,1075.58 1131.59,1080.58 1136.59,1080.58 1141.59,1075.58 1146.59,1075.58 1151.59,1080.58 1156.59,1080.58 1161.59,1075.58 1166.59,1075.58 1171.16,1080.15 1281.33,1080.15 1330.44,1031.04 1360.65,1031.04 1370.19,1040.58 1370.19,1064.58 1385.19,1079.58 1385.19,1100.58 1350.19,1135.58 v1(1336.19,1135.58)
SA7: U2.T21 U3.R2 | length 523.5
  Top Layer w4: U3.R2@864.4,1021.32 864.4,1016.79 848.46,1000.85 848.46,970.31 894.19,924.58 1258.81,924.58 U2.T21@1284.68,950.45
SA8: U2.V17 U3.T8 | length 572.8
  Top Layer w4: U3.T8@1053.06,990.16 1053.06,977.45 1044.19,968.58 911.19,968.58 906.19,963.58 906.19,956.58 911.19,951.58 1051.19,951.58 1069.19,969.58 1069.19,996.58 1077.19,1004.58 1208.19,1004.58 1223.19,1019.58 1223.19,1042.47 U2.V17@1233.44,1052.72
SA9: U2.T20 U3.R3 | length 628.2
  Top Layer w4: U3.R3@895.56,1021.66 913.56,1021.66 917.56,1025.66 917.56,1039.58 921.56,1043.58 925.56,1043.58 929.56,1039.58 929.56,1025.66 933.56,1021.66 938.11,1021.66 940.78,1018.99 940.78,1013.33 929.44,1001.99 929.44,996.33 932.26,993.51 937.92,993.51 966.26,1021.85 971.92,1021.85 974.75,1019.02 974.75,1013.36 946.41,985.02 946.41,979.36 949.24,976.53 954.89,976.53 966.24,987.88 971.89,987.88 v1(975.19,984.58) ; v1(1272.46,963.83) U2.T20@1284.68,976.05
  Mid-Layer 2 w4: v1(975.19,984.58) 983.5,976.27 983.5,970.61 978.74,965.85 978.74,960.19 981.57,957.36 987.23,957.36 991.99,962.12 997.65,962.12 1032.19,927.58 1236.21,927.58 v1(1272.46,963.83)
SA10: U2.U19 U3.L7 | length 596.3
  Top Layer w4: v1(987.19,1149.58) 989.47,1147.3 U3.L7@1021.88,1147.3 ; U2.U19@1259.09,1001.64 1264.25,1006.8 1278.46,1006.8 1286.46,1014.8 1316.46,1014.8 1324.35,1022.69 1324.35,1031.99 1329.19,1036.83 v1(1329.19,1052.58)
  Mid-Layer 3 w4: v1(987.19,1149.58) 1164.19,1149.58 1182.24,1131.53 1187.9,1131.53 1190.73,1134.36 1196.38,1134.36 1199.21,1131.53 1199.21,1125.87 1187.9,1114.56 1187.9,1108.9 1190.73,1106.07 1196.38,1106.07 1207.7,1117.39 1213.36,1117.39 1216.18,1114.56 1216.18,1108.9 1204.87,1097.59 1204.87,1091.93 1207.7,1089.1 1213.36,1089.1 1216.18,1091.93 1221.84,1091.93 1228.97,1084.8 1296.97,1084.8 v1(1329.19,1052.58)
  other v1: 1329.19,1052.58
SA11: U2.U17 U3.R7 | length 570.5
  Top Layer w4: U3.R7@1021.88,1021.32 v1(1037.46,1005.74) ; U2.U17@1259.09,1052.82 v1(1272.07,1065.8)
  Mid-Layer 2 w4: v1(1037.46,1005.74) 1037.46,1011.31 1019.19,1029.58 1007.19,1029.58 999.19,1021.58 999.19,1005.58 1022.19,982.58 1030.05,982.58 1034.05,978.58 1034.05,967.04 1038.05,963.04 1045.05,963.04 1049.05,967.04 1049.05,975.44 1053.19,979.58 1058.19,979.58 1083.19,954.58 1183.19,954.58 1205.19,976.58 1205.19,980.47 1209.19,984.47 1220.86,984.47 1224.86,988.47 1224.86,993.47 1220.86,997.47 1209.19,997.47 1205.19,1001.47 1205.19,1006.47 1209.19,1010.47 1220.86,1010.47 1224.86,1014.47 1224.86,1019.47 1220.86,1023.47 1209.19,1023.47 1205.19,1027.47 1205.19,1034.58 1219.19,1048.58 1254.85,1048.58 v1(1272.07,1065.8)
  other v1: 1272.07,1065.8 1272.07,1065.8 1272.07,1065.8 1272.07,1065.8
SA12: U2.P16 U3.N7 | length 463.6
  Top Layer w4: U3.N7@1021.88,1084.31 1022.26,1084.31 v1(1036.46,1070.11) ; U2.P16@1335.86,1078.41 1348.03,1090.58 v1(1348.19,1090.58)
  Mid-Layer 2 w4: v1(1036.46,1070.11) 1049.72,1070.11 1069.19,1089.58 1291.19,1089.58 1305.19,1075.58 1312.2,1075.58 1316.2,1079.58 1316.2,1091.75 1320.2,1095.75 1325.2,1095.75 1329.2,1091.75 1329.2,1079.58 1333.2,1075.58 1365.92,1075.58 1373.46,1083.11 1373.46,1093.11 1367.99,1098.58 1356.19,1098.58 v1(1348.19,1090.58)
SA13: U2.R18 U3.T3 | length 550.2
  Top Layer w4: U3.T3@895.9,989.82 910.87,1004.8 v1(911.46,1004.8) ; v1(1302.19,1034.58) 1309.54,1027.23 U2.R18@1310.27,1027.23
  Mid-Layer 2 w4: v1(911.46,1004.8) 911.46,1034.46 921.96,1044.96 942.81,1044.96 999.19,988.58 999.19,977.58 1036.19,940.58 1199.19,940.58 1265.41,1006.8 1281.14,1006.8 1302.19,1027.85 v1(1302.19,1034.58)
SA14: U2.P15 U3.T7 | length 561.8
  Top Layer w4.5: v1(987.46,1033.11) 987.46,1024.25 U3.T7@1021.88,989.82 ; v1(1324.19,1116.58) 1335.86,1104.91 U2.P15@1335.86,1104
  Mid-Layer 2 w4: v1(987.46,1033.11) 961.19,1059.38 961.19,1065.58 965.72,1070.11 971.66,1070.11 998.19,1043.58 1010.19,1043.58 1020.46,1053.85 1020.46,1065.11 1013.19,1072.38 1013.19,1085.58 1020.19,1092.58 1029.19,1092.58 1035.66,1086.11 1038.88,1086.11 1043.38,1090.61 1043.38,1096.08 1047.88,1100.58 1308.19,1100.58 v1(1324.19,1116.58)
SA15: U2.U18 U3.M7 | length 589
  Top Layer w4: v1(955.81,1086.66) 955.81,1076.76 965.46,1067.11 965.46,1055.11 968.46,1052.11 977.72,1052.11 985.19,1059.58 985.19,1078.58 968.19,1095.58 968.19,1107.58 976.42,1115.81 U3.M7@1021.88,1115.81 ; v1(1245.03,1027.23) U2.U18@1259.09,1027.23
  Mid-Layer 3 w4: v1(955.81,1086.66) 958.89,1083.58 989.19,1083.58 1009.41,1103.8 1143.97,1103.8 1147.59,1100.18 1153.25,1100.18 1156.07,1103.01 1161.73,1103.01 1164.56,1100.18 1164.56,1094.52 1153.25,1083.21 1153.25,1077.55 1156.07,1074.72 1161.73,1074.72 1173.05,1086.04 1178.7,1086.04 1181.53,1083.21 1181.53,1077.55 1170.22,1066.24 1170.22,1060.58 1173.05,1057.75 1178.7,1057.75 1181.53,1060.58 1204.19,1060.58 1237.54,1027.23 v1(1245.03,1027.23)
SBA0: U2.P20 U3.M2 | length 676.1
  Top Layer w4: v1(849.46,1100.86) U3.M2@864.4,1115.81 ; v1(1323.46,988.45) U2.P20@1335.86,976.05
  Mid-Layer 3 w4: v1(849.46,1100.86) 842.46,1093.86 842.46,1011.8 916.67,937.58 1294.19,937.58 1323.46,966.85 v1(1323.46,988.45)
SBA1: U2.U15 U3.N8 | length 599.6
  Top Layer w4.5: v1(984.46,1100.11) 1037.57,1100.11 U3.N8@1053.38,1084.31 ; U2.U15@1259.03,1103.9 1259.51,1103.9 v1(1272.19,1116.58)
  Mid-Layer 2 w4: v1(984.46,1100.11) 995.92,1111.58 1012.59,1111.58 1016.59,1115.58 1016.59,1135.98 1021.19,1140.58 1026.19,1140.58 1030.59,1136.18 1030.59,1115.58 1034.59,1111.58 1125.19,1111.58 1129.19,1115.58 1129.19,1128.58 1133.19,1132.58 1135.19,1132.58 1139.19,1128.58 1139.19,1115.58 1143.19,1111.58 1145.19,1111.58 1149.19,1115.58 1149.19,1128.58 1153.19,1132.58 1155.19,1132.58 1159.19,1128.58 1159.19,1115.58 1163.19,1111.58 1165.19,1111.58 1169.19,1115.58 1169.19,1128.58 1173.19,1132.58 1175.19,1132.58 1179.19,1128.58 1179.19,1115.58 1183.19,1111.58 1185.19,1111.58 1189.19,1115.58 1189.19,1128.58 1193.19,1132.58 1195.19,1132.58 1199.19,1128.58 1199.19,1115.58 1203.19,1111.58 1205.19,1111.58 1209.19,1115.58 1209.19,1128.58 1213.19,1132.58 1215.19,1132.58 1219.19,1128.58 1219.19,1115.58 1223.19,1111.58 1267.19,1111.58 v1(1272.19,1116.58)
  other v1: 984.46,1100.11
SBA2: U2.U20 U3.M3 | length 596.1
  Top Layer w4: v1(880.46,1098.8) 880.46,1100.36 U3.M3@895.9,1115.81 ; U2.U20@1259.09,976.05 v1(1273.46,990.42)
  Mid-Layer 3 w4: v1(880.46,1098.8) 855.46,1073.8 855.46,1017.31 920.19,952.58 1173.24,952.58 1211.08,990.42 v1(1273.46,990.42)
SCAS: U2.N16 U3.K3 | length 650.5
  Top Layer w4.5: U3.K3@895.9,1178.8 909.68,1192.58 925.19,1192.58 958.41,1225.8 v1(988.46,1225.8) ; U2.N16@1361.45,1078.41 1375.46,1092.42 1375.46,1134.31 v1(1375.19,1134.58)
  Mid-Layer 2 w4: v1(988.46,1225.8) 999.67,1214.58 1008.72,1214.58 1012.72,1218.58 1012.72,1221.76 1016.72,1225.76 1020.72,1225.76 1024.72,1221.76 1024.72,1218.58 1028.72,1214.58 1032.72,1214.58 1036.72,1218.58 1036.72,1221.76 1040.72,1225.76 1044.72,1225.76 1048.72,1221.76 1048.72,1218.58 1052.72,1214.58 1056.72,1214.58 1060.72,1218.58 1060.72,1221.76 1064.72,1225.76 1068.72,1225.76 1072.72,1221.76 1072.72,1218.58 1076.72,1214.58 1080.72,1214.58 1084.72,1218.58 1084.72,1221.76 1088.72,1225.76 1092.72,1225.76 1096.72,1221.76 1096.72,1218.58 1100.72,1214.58 1282.19,1214.58 1338.19,1158.58 1351.19,1158.58 v1(1375.19,1134.58)
SCKE0: U2.V15 U3.K9 | length 489.9
  Top Layer w4: U3.K9@1081.62,1179.04 1196.65,1179.04 1224.19,1206.58 1241.19,1206.58 1254.19,1219.58 1302.19,1219.58 1311.19,1210.58 1311.19,1200.58 1304.19,1193.58 1229.19,1193.58 1216.19,1180.58 1216.19,1089.58 1221.19,1084.58 1227.92,1084.58 1233.5,1090.15 U2.V15@1233.5,1104
SCKE1: U2.P13 U3.J9 | length 566.3
  Top Layer w4: U3.J9@1084.56,1210.66 1106.63,1188.58 1116.43,1188.58 1120.37,1192.52 1120.37,1221.82 1124.31,1225.75 1128.43,1225.75 1132.37,1221.82 1132.37,1192.52 1136.31,1188.58 1140.43,1188.58 1144.37,1192.52 1144.37,1221.82 1148.31,1225.75 1152.43,1225.75 1156.37,1221.82 1156.37,1192.52 1160.31,1188.58 1164.43,1188.58 1168.37,1192.52 1168.37,1221.82 1172.31,1225.75 1176.43,1225.75 1180.37,1221.82 1180.37,1192.52 1184.31,1188.58 1188.59,1188.58 1220.13,1220.11 1238.46,1220.11 1245.46,1227.11 1245.46,1235.11 1255.46,1245.11 1303.66,1245.11 1349.46,1199.31 1349.46,1168.78 U2.P13@1335.86,1155.18
SCKN: R7.2 U2.U14 U3.K7 | length 602.8
  Top Layer w4: U2.U14@1259.03,1129.49 1279.19,1149.65 v1(1279.19,1153.58)
  Top Layer w4.4: v1(946.19,1179.58) 960.19,1179.58 970.46,1189.85 1010.83,1189.85 U3.K7@1021.88,1178.8
  Mid-Layer 2 w4.4: v1(946.19,1179.58) 951.19,1184.58 1035.22,1184.58 1050.08,1169.71 1086.2,1169.71 1105.67,1189.18 1113.71,1189.18 1118.79,1184.1 1118.79,1165.1 1127.71,1156.18 1145.67,1156.18 1154.59,1165.1 1154.59,1187.1 1156.67,1189.18 1165.71,1189.18 1168.79,1186.1 1168.79,1165.1 1177.71,1156.18 1195.67,1156.18 1206.59,1167.1 1206.59,1189.1 1210.67,1193.18 1264.59,1193.18 1279.19,1178.58 v1(1279.19,1153.58)
SCKP: R7.1 U2.T14 U3.J7 | length 609.4
  Top Layer w4: U2.T14@1284.62,1129.49 1304.19,1149.06 v1(1304.19,1155.58)
  Top Layer w4.4: v1(958.19,1204.58) 958.19,1203.14 954.3,1199.25 1010.83,1199.25 U3.J7@1021.88,1210.29
  Mid-Layer 2 w4.4: v1(958.19,1204.58) 968.46,1194.31 1037.36,1194.31 1053.56,1178.11 1082.72,1178.11 1102.19,1197.58 1117.19,1197.58 1127.19,1187.58 1127.19,1168.58 1131.19,1164.58 1142.19,1164.58 1146.19,1168.58 1146.19,1190.58 1153.19,1197.58 1169.19,1197.58 1177.19,1189.58 1177.19,1168.58 1181.19,1164.58 1192.19,1164.58 1198.19,1170.58 1198.19,1192.58 1207.19,1201.58 1269.19,1201.58 1288.19,1182.58 1288.19,1171.58 v1(1304.19,1155.58)
SCS0: U2.P21 U3.L2 | length 704.3
  Top Layer w4.5: v1(848.9,1131.8) U3.L2@864.4,1147.3 ; v1(1316.19,927.58) 1335.86,947.25 U2.P21@1335.86,950.4
  Mid-Layer 2 w4.3: v1(848.9,1131.8) 864.86,1115.84 864.86,986.91 953.19,898.58 1287.19,898.58 v1(1316.19,927.58)
SCS1: U2.N19 U3.L1 | length 662.6
  Top Layer w4: U3.L1@832.91,1147.3 844.65,1147.3 860.14,1162.8 963.41,1162.8 v1(966.19,1165.58) ; v1(1349.87,1013.21) U2.N19@1361.45,1001.64
  Mid-Layer 3 w4: v1(966.19,1165.58) 1180.19,1165.58 1244.97,1100.8 1308.97,1100.8 1336.19,1073.58 1356.99,1073.58 1372.84,1057.73 1372.84,1036.18 v1(1349.87,1013.21)
SD_CLK: R14.1 U5.21 | length 501.8
  Top Layer w5: R14.1@1842.19,1289.58 1861.19,1289.58 1879.19,1271.58 1879.19,1079.58 v1(1870.19,1070.58) ; v1(1865.19,877.58) 1904.11,877.58 U5.21@1904.42,877.27
  Bottom Layer w5: v1(1865.19,877.58) 1870.19,882.58 1870.19,967.69 1848.19,989.69 1848.19,1048.58 v1(1870.19,1070.58)
SD_CMD: U2.C7 U5.22 | length 767.5
  Top Layer w4: U5.22@1912.43,857.58 U5.22@1913.42,857.58
  Top Layer w5: U2.C7@1617.3,1308.62 v1(1629.19,1296.72) v1@1629.19,1296.58 ; v1(1844.19,857.58) U5.22@1904.42,857.59
  Bottom Layer w5: v1(1629.19,1296.72) 1708.33,1296.72 1727.19,1315.58 1814.21,1315.58 1847.19,1282.6 1847.19,1092.62 1815.69,1061.12 1815.69,967.08 1827.19,955.58 1827.19,874.58 v1(1844.19,857.58)
SD_D0: U2.C6 U5.19 | length 721.4
  Top Layer w5: U2.C6@1617.3,1334.21 1629.92,1321.58 1655.19,1321.58 1661.19,1315.58 v1(1699.19,1315.58) ; v1(1842.19,918.58) 1902.48,918.58 U5.19@1904.42,916.64
  Bottom Layer w5: v1(1699.19,1315.58) 1704.19,1315.58 1718.19,1329.58 1812.23,1329.58 1859.19,1282.62 1859.19,1092.6 1827.19,1060.6 1827.19,972.58 1842.19,957.58 v1(1842.19,918.58)
SD_D1: U2.B5 U5.20 | length 725.8
  Top Layer w5: U2.B5@1642.89,1359.8 1643.67,1360.58 1697.19,1360.58 v1(1704.19,1353.58) ; v1(1850.19,896.58) 1904.04,896.58 U5.20@1904.42,896.96
  Bottom Layer w5: v1(1704.19,1353.58) 1715.19,1342.58 1811.25,1342.58 1869.19,1284.64 1869.19,1090.58 1838.19,1059.58 1838.19,979.58 1859.19,958.58 1859.19,905.58 v1(1850.19,896.58)
SD_D2: U2.C5 U5.23 | length 788.4
  Top Layer w5: U2.C5@1617.3,1359.8 1617.3,1360.34 1628.88,1371.92 v1(1628.88,1372.47) ; v1(1875.19,837.58) 1904.1,837.58 U5.23@1904.42,837.9
  Bottom Layer w5: v1(1628.88,1372.47) 1628.99,1372.58 1711.19,1372.58 1726.19,1357.58 1808.27,1357.58 1885.04,1280.81 1885.04,850.43 1875.19,840.58 v1(1875.19,837.58)
SD_D3: U2.B7 U5.24 | length 748.4
  Top Layer w5: U2.B7@1642.89,1308.62 1652.92,1298.58 v1(1742.19,1298.58) ; v1(1861.19,817.58) 1903.78,817.58 U5.24@1904.42,818.22
  Bottom Layer w5: v1(1742.19,1298.58) 1819.19,1298.58 1838.69,1279.08 1838.69,1096.14 1807.19,1064.64 1807.19,962.26 1818.69,950.76 1818.69,860.08 v1(1861.19,817.58)
SDC0_CLK: D5.2 R13.1 SIM1.5 | length 1673.4
  Top Layer w4: SIM1.5@57.05,1613.28 57.35,1613.58 v1(117.19,1613.58) 142.77,1613.58 147.07,1609.28 147.07,1595.58 151.07,1591.58 163.07,1591.58 167.07,1595.58 167.07,1630.99 171.07,1634.99 183.07,1634.99 187.07,1630.99 187.07,1595.58 191.07,1591.58 203.07,1591.58 207.07,1595.58 207.07,1630.99 211.07,1634.99 223.07,1634.99 227.07,1630.99 227.07,1595.58 231.07,1591.58 243.07,1591.58 247.07,1595.58 247.07,1630.99 251.07,1634.99 263.07,1634.99 267.07,1630.99 267.07,1595.58 271.07,1591.58 283.07,1591.58 287.07,1595.58 287.07,1609.28 291.07,1613.28 345.89,1613.28 359.19,1626.58 1386.19,1626.58 R13.1@1437.19,1575.58
SDC0_CMD: D4.2 SIM1.3 U2.K3 | length 1669.5
  Top Layer w3.5: 1414.19,1497.58 1415.19,1496.58 1415.19,1454.58 1426.19,1443.58
  Top Layer w4: SIM1.3@57.05,1526.66 99.92,1526.66 v1(123.96,1550.7) 162.83,1550.7 166.83,1554.7 166.83,1566.7 170.83,1570.7 182.83,1570.7 186.83,1566.7 186.83,1554.7 190.83,1550.7 202.83,1550.7 206.83,1554.7 206.83,1566.7 210.83,1570.7 222.83,1570.7 226.83,1566.7 226.83,1554.7 230.83,1550.7 242.83,1550.7 246.83,1554.7 246.83,1566.7 250.83,1570.7 262.83,1570.7 266.83,1566.7 266.83,1554.7 270.83,1550.7 282.83,1550.7 286.83,1554.7 286.83,1566.7 290.83,1570.7 302.83,1570.7 306.83,1566.7 306.83,1554.7 310.83,1550.7 384.31,1550.7 432.19,1598.58 1350.19,1598.58 1398.19,1550.58 1398.19,1513.58 1414.19,1497.58 ; 1426.19,1443.58 1426.19,1422.94 U2.K3@1438.16,1410.98
SDC0_D0: D6.2 SIM1.7 U2.J3 | length 1645.9
  Top Layer w4: SIM1.7@57.05,1699.89 v1(119.32,1699.89) 283.88,1699.89 343.19,1640.58 1414.19,1640.58 1468.19,1586.58 1468.19,1521.58 1451.19,1504.58 1451.19,1423.54 U2.J3@1463.76,1410.98
SDC0_D1: D7.2 SIM1.8 U2.J2 | length 1649.5
  Top Layer w4: SIM1.8@57.05,1743.2 57.68,1742.58 v1(118.19,1742.58) 284.19,1742.58 373.19,1653.58 1421.19,1653.58 1480.19,1594.58 1480.19,1512.58 1463.76,1496.15 U2.J2@1463.76,1436.57
SDC0_D2: D2.2 SIM1.1 U2.L3 | length 1672.1
  Top Layer w3.5: 1397.69,1475.58 1398.19,1475.08 1398.19,1441.34 1400.19,1439.34 1400.19,1423.35 U2.L3@1412.57,1410.98
  Top Layer w4: SIM1.1@57.05,1440.05 94.66,1440.05 v1(111.19,1456.58) 122.19,1467.58 150.87,1467.58 154.87,1471.58 154.87,1483.58 158.87,1487.58 170.87,1487.58 174.87,1483.58 174.87,1471.58 178.87,1467.58 190.87,1467.58 194.87,1471.58 194.87,1483.58 198.87,1487.58 210.87,1487.58 214.87,1483.58 214.87,1471.58 218.87,1467.58 230.87,1467.58 234.87,1471.58 234.87,1483.58 238.87,1487.58 250.87,1487.58 254.87,1483.58 254.87,1471.58 258.87,1467.58 270.87,1467.58 274.87,1471.58 274.87,1483.58 278.87,1487.58 290.87,1487.58 294.87,1483.58 294.87,1471.58 298.87,1467.58 367.19,1467.58 471.19,1571.58 1337.19,1571.58 1374.19,1534.58 1374.19,1499.08 1397.69,1475.58
  Bottom Layer w5: v1(111.19,1456.58) 114.58,1456.58 D2.2@128.58,1442.58
SDC0_D3: D3.2 SIM1.2 U2.L2 | length 1684.6
  Top Layer w3.5: 1405.19,1487.58 1406.19,1486.58 1406.19,1449.58 1412.57,1443.2 U2.L2@1412.57,1436.57
  Top Layer w4: SIM1.2@57.05,1483.36 88.68,1483.36 v1(105.2,1499.89) 112.89,1507.58 145.88,1507.58 149.88,1511.58 149.88,1527.58 153.88,1531.58 165.88,1531.58 169.88,1527.58 169.88,1511.58 173.88,1507.58 185.88,1507.58 189.88,1511.58 189.88,1527.58 193.88,1531.58 205.88,1531.58 209.88,1527.58 209.88,1511.58 213.88,1507.58 225.88,1507.58 229.88,1511.58 229.88,1527.58 233.88,1531.58 245.88,1531.58 249.88,1527.58 249.88,1511.58 253.88,1507.58 265.88,1507.58 269.88,1511.58 269.88,1527.58 273.88,1531.58 285.88,1531.58 289.88,1527.58 289.88,1511.58 293.88,1507.58 370.19,1507.58 447.19,1584.58 1344.19,1584.58 1386.19,1542.58 1386.19,1506.58 1405.19,1487.58
  Bottom Layer w5: v1(105.2,1499.89) 125.29,1499.89 D3.2@128.58,1503.18
SDC0_DET: R15.1 U2.K2 | length 1549.8
  Top Layer w3.5: 1425.19,1505.58 1425.19,1458.58 1438.16,1445.61 U2.K2@1438.16,1436.57
  Top Layer w4: R15.1@322.19,1281.58 v1(346.19,1281.58) ; v1(364.19,1586.58) 390.19,1612.58 1357.19,1612.58 1411.19,1558.58 1411.19,1519.58 1425.19,1505.58
  Bottom Layer w4: v1(346.19,1281.58) 346.19,1568.58 v1(364.19,1586.58)
SDC2_CLK: R12.1 U4.M6 | length 493.8
  Top Layer w3.5: R12.1@1840.19,1389.58 1860.19,1389.58 1900.19,1349.58 1951.19,1349.58 v1(1960.19,1340.58) ; v1(2208.19,1444.58) 2225.3,1444.58 U4.M6@2225.78,1445.05
  Mid-Layer 1 w3.5: v1(1960.19,1340.58) 1977.19,1357.58 2176.19,1357.58 2223.19,1404.58 2223.19,1429.58 v1(2208.19,1444.58)
SDC2_CMD: R50.2 U2.E2 U4.M5 | length 937.5
  Top Layer w3.5: U2.E2@1566.12,1436.57 1579.19,1449.64 1579.19,1487.58 1596.19,1504.58 ; v1(2206.19,1414.58) 2216.97,1425.36 U4.M5@2225.78,1425.36
  Top Layer w4: 1596.19,1504.58 1684.19,1504.58 1731.19,1551.58 1731.19,1610.58 1741.19,1620.58 v1(1751.19,1620.58)
  Mid-Layer 1 w4: v1(1751.19,1620.58) 1919.19,1620.58 2095.19,1444.58 2176.19,1444.58 v1(2206.19,1414.58)
  Bottom Layer w10: R50.2@2201.19,1361.58 2201.19,1409.58 v1(2206.19,1414.58)
SDC2_D0: U2.F2 U4.A3 | length 872.8
  Top Layer w3.5: 1540.53,1444.92 1558.19,1462.58 1558.19,1499.58 1588.19,1529.58 ; v1(1885.19,1410.58) 1885.19,1407.58 1919.19,1373.58 1959.19,1373.58 1971.61,1385.99 U4.A3@2009.24,1385.99
  Top Layer w4: U2.F2@1540.53,1436.57 1540.53,1444.92 ; 1588.19,1529.58 1670.19,1529.58 1705.19,1564.58 1705.19,1652.58 v1(1691.19,1666.58)
  Bottom Layer w4: v1(1691.19,1666.58) 1756.19,1666.58 1780.19,1642.58 1780.19,1515.58 v1(1885.19,1410.58)
SDC2_D1: U2.G3 U4.A4 | length 969.8
  Top Layer w3.5: v1(1943.19,1399.58) 1949.19,1405.58 2009.13,1405.58 U4.A4@2009.24,1405.68
  Top Layer w4: U2.G3@1514.94,1410.98 1526.19,1422.23 1526.19,1479.58 1532.19,1485.58 1532.19,1649.58 1584.19,1701.58 1737.19,1701.58 1805.19,1633.58 1805.19,1507.58 1842.19,1470.58 v1(1864.19,1470.58)
  Bottom Layer w4: v1(1864.19,1470.58) 1913.19,1470.58 1943.19,1440.58 v1(1943.19,1399.58)
SDC2_D2: U2.H2 U4.A5 | length 954
  Top Layer w3.5: U2.H2@1489.35,1436.57 1489.35,1444.74 1502.19,1457.58 1502.19,1492.58 1507.19,1497.58 1507.19,1663.58 1572.19,1728.58 1748.19,1728.58 1836.19,1640.58 1836.19,1529.58 1917.19,1448.58 1943.19,1448.58 1966.41,1425.36 U4.A5@2009.24,1425.36
SDC2_D3: U2.E3 U4.B2 | length 762.4
  Top Layer w3.5: U2.E3@1566.12,1410.98 1569.72,1414.58 1578.19,1414.58 1588.19,1424.58 1596.19,1424.58 1605.19,1433.58 1605.19,1480.58 1618.19,1493.58 1690.19,1493.58 1742.19,1545.58 1742.19,1592.58 1747.19,1597.58 1757.19,1597.58 1762.19,1592.58 1762.19,1489.58 1832.19,1419.58 1851.19,1419.58 1908.19,1362.58 1963.19,1362.58 1976.65,1376.04 2019.2,1376.04 U4.B2@2028.92,1366.32
SDC2_D4: U2.F1 U4.B3 | length 909.4
  Top Layer w3.5: v1(1914.19,1411.58) 1914.19,1405.58 1937.19,1382.58 1954.19,1382.58 1967.19,1395.58 2019.34,1395.58 U4.B3@2028.92,1385.99
  Top Layer w4: U2.F1@1540.53,1462.17 1540.53,1475.92 1545.19,1480.58 1545.19,1639.58 1593.19,1687.58 1731.19,1687.58 1791.19,1627.58 1791.19,1499.58 1841.19,1449.58 v1(1884.19,1449.58)
  Bottom Layer w4: v1(1884.19,1449.58) 1897.19,1449.58 1914.19,1432.58 v1(1914.19,1411.58)
SDC2_D5: U2.F3 U4.B4 | length 832.3
  Top Layer w3.5: U2.F3@1540.53,1410.98 1540.53,1421.72 1553.19,1434.38 1553.19,1443.58 1569.19,1459.58 1569.19,1494.58 1592.19,1517.58 1677.19,1517.58 1718.19,1558.58 1718.19,1629.58 1733.19,1644.58 1753.19,1644.58 1776.19,1621.58 1776.19,1494.58 1836.19,1434.58 1939.19,1434.58 1958.19,1415.58 2019.03,1415.58 U4.B4@2028.92,1405.68
SDC2_D6: U2.H1 U4.B5 | length 971.2
  Top Layer w3.5: U2.H1@1489.35,1462.17 1489.35,1498.74 1496.19,1505.58 1496.19,1670.58 1567.19,1741.58 1755.19,1741.58 1852.19,1644.58 1852.19,1530.58 1923.69,1459.08 1953.69,1459.08 1977.19,1435.58 2018.71,1435.58 U4.B5@2028.92,1425.36
SDC2_D7: U2.H3 U4.B6 | length 973.9
  Top Layer w3.5: v1(1929.19,1490.58) 1964.19,1490.58 2000.19,1454.58 2019.4,1454.58 U4.B6@2028.92,1445.05
  Top Layer w4: U2.H3@1489.35,1410.98 1502.19,1423.82 1502.19,1441.58 1514.19,1453.58 1514.19,1486.58 1519.19,1491.58 1519.19,1656.58 1578.19,1715.58 1741.19,1715.58 1820.19,1636.58 1820.19,1517.58 v1(1832.19,1505.58)
  Bottom Layer w4: v1(1832.19,1505.58) 1847.19,1490.58 v1(1929.19,1490.58)
SDC2_DS: R51.2 U2.B1 U4.H5 | length 751.1
  Top Layer w3.5: U4.H5@2147.04,1425.36 2147.19,1425.21 v1(2147.19,1406.58)
  Top Layer w4: U2.B1@1642.89,1462.17 1660.3,1479.58 1695.19,1479.58 1734.19,1518.58 v1(1742.19,1518.58)
  Mid-Layer 1 w4: v1(1742.19,1518.58) 1742.19,1574.58 1777.19,1609.58 1914.19,1609.58 2090.19,1433.58 2120.19,1433.58 v1(2147.19,1406.58)
  Bottom Layer w10: v1(2147.19,1406.58) 2159.19,1394.58 R51.2@2159.19,1361.58
SDC2_RST: U2.C2 U4.K5 | length 637
  Top Layer w3.5: v1(2180.19,1405.58) 2186.41,1411.8 U4.K5@2186.41,1425.36
  Top Layer w4: U2.C2@1617.3,1436.57 1629.31,1448.58 1746.19,1448.58 1756.19,1438.58 v1(1785.19,1438.58)
  Mid-Layer 1 w4: v1(1785.19,1438.58) 1853.19,1370.58 2145.19,1370.58 v1(2180.19,1405.58)
SDQ0: U2.N3 U3.A2 | length 676.8
  Top Layer w4: U3.A2@864.4,1462.26 865.51,1462.26 v1(880.19,1447.58) ; U2.N3@1361.45,1411.08 1361.69,1411.08 v1(1374.19,1423.58)
  Mid-Layer 3 w4: v1(880.19,1447.58) 882.19,1445.58 901.19,1445.58 906.19,1440.58 906.19,1431.58 911.19,1426.58 920.19,1426.58 924.19,1430.58 924.19,1475.58 967.19,1518.58 1322.19,1518.58 1374.19,1466.58 v1(1374.19,1423.58)
SDQ1: U2.U4 U3.C8 | length 657.5
  Top Layer w4: U3.C8@1053.38,1399.27 1068.61,1384.04 1088.47,1384.04 1109.94,1362.58 v1(1119.19,1362.58) ; v1@1246.46,1372.86 U2.U4@1259.09,1385.49
  Mid-Layer 3 w4: v1(1119.19,1362.58) 1112.19,1369.58 995.19,1369.58 986.19,1378.58 986.19,1388.58 996.19,1398.58 1022.72,1398.58 1026.22,1395.08 1026.22,1390.46 1029.72,1386.96 1034.72,1386.96 1038.22,1390.46 1038.22,1395.08 1041.72,1398.58 1046.72,1398.58 1050.22,1395.08 1050.22,1390.46 1053.72,1386.96 1058.72,1386.96 1062.22,1390.46 1062.22,1395.08 1065.72,1398.58 1070.72,1398.58 1074.22,1395.08 1074.22,1390.46 1077.72,1386.96 1082.72,1386.96 1086.22,1390.46 1086.22,1395.08 1089.72,1398.58 1102.19,1398.58 1114.19,1386.58 1134.19,1386.58 1145.19,1397.58 1153.83,1397.58 1157.33,1401.08 1157.33,1406.6 1160.83,1410.1 1165.83,1410.1 1169.33,1406.6 1169.33,1388.56 1172.83,1385.06 1177.83,1385.06 1181.33,1388.56 1181.33,1406.6 1184.83,1410.1 1189.83,1410.1 1193.33,1406.6 1193.33,1388.56 1196.83,1385.06 1201.83,1385.06 1205.33,1388.56 1205.33,1394.08 1208.83,1397.58 1221.67,1397.58 v1(1246.46,1372.8)
  other v1: 1246.46,1372.8
SDQ2: U2.N2 U3.C2 | length 668.9
  Top Layer w4: U3.C2@864.4,1399.27 879.09,1384.58 906.19,1384.58 v1(934.19,1412.58) ; v1(1349.58,1424.8) U2.N2@1361.45,1436.67
  Mid-Layer 3 w4: v1(934.19,1412.58) 934.19,1468.58 973.19,1507.58 1319.19,1507.58 1364.19,1462.58 1364.19,1439.41 v1(1349.58,1424.8)
SDQ3: U2.T4 U3.D7 | length 647.1
  Top Layer w4: U3.D7@1021.88,1367.77 1021.88,1364.77 v1(1033.89,1352.76) ; v1(1272.46,1372.8) 1272.46,1373.27 U2.T4@1284.68,1385.49
  Mid-Layer 3 w4: v1(1033.89,1352.76) 1015.19,1334.06 1015.19,1307.58 1028.19,1294.58 1036.44,1294.58 1040.44,1298.58 1040.44,1316.58 1044.44,1320.58 1048.44,1320.58 1052.44,1316.58 1052.44,1298.58 1056.44,1294.58 1060.44,1294.58 1064.44,1298.58 1064.44,1316.58 1068.44,1320.58 1072.44,1320.58 1076.44,1316.58 1076.44,1298.58 1080.44,1294.58 1094.19,1294.58 1110.19,1310.58 1110.19,1328.58 1127.19,1345.58 1135.38,1345.58 1139.38,1341.58 1139.38,1325.58 1143.38,1321.58 1150.38,1321.58 1154.38,1325.58 1154.38,1341.58 1158.38,1345.58 1165.38,1345.58 1169.38,1341.58 1169.38,1325.58 1173.38,1321.58 1180.38,1321.58 1184.38,1325.58 1184.38,1341.58 1188.38,1345.58 1195.38,1345.58 1199.38,1341.58 1199.38,1325.58 1203.38,1321.58 1210.38,1321.58 1214.38,1325.58 1214.38,1341.58 1218.38,1345.58 1225.38,1345.58 1229.38,1341.58 1229.38,1325.58 1233.38,1321.58 1240.38,1321.58 1244.38,1325.58 1244.38,1341.58 1248.38,1345.58 1264.19,1345.58 1272.46,1353.85 v1(1272.46,1372.8)
  other v1: 1272.46,1372.8 1272.46,1372.8 1272.46,1372.8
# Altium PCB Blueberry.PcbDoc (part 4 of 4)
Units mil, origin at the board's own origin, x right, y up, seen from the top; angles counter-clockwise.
Board outline 2559.06 x 2204.72 mil, 6 copper layers (Top Layer, Mid-Layer 1, Mid-Layer 2, Mid-Layer 3, Mid-Layer 4, Bottom Layer); 211 components, 214 nets, 1171 pads, 598 vias.

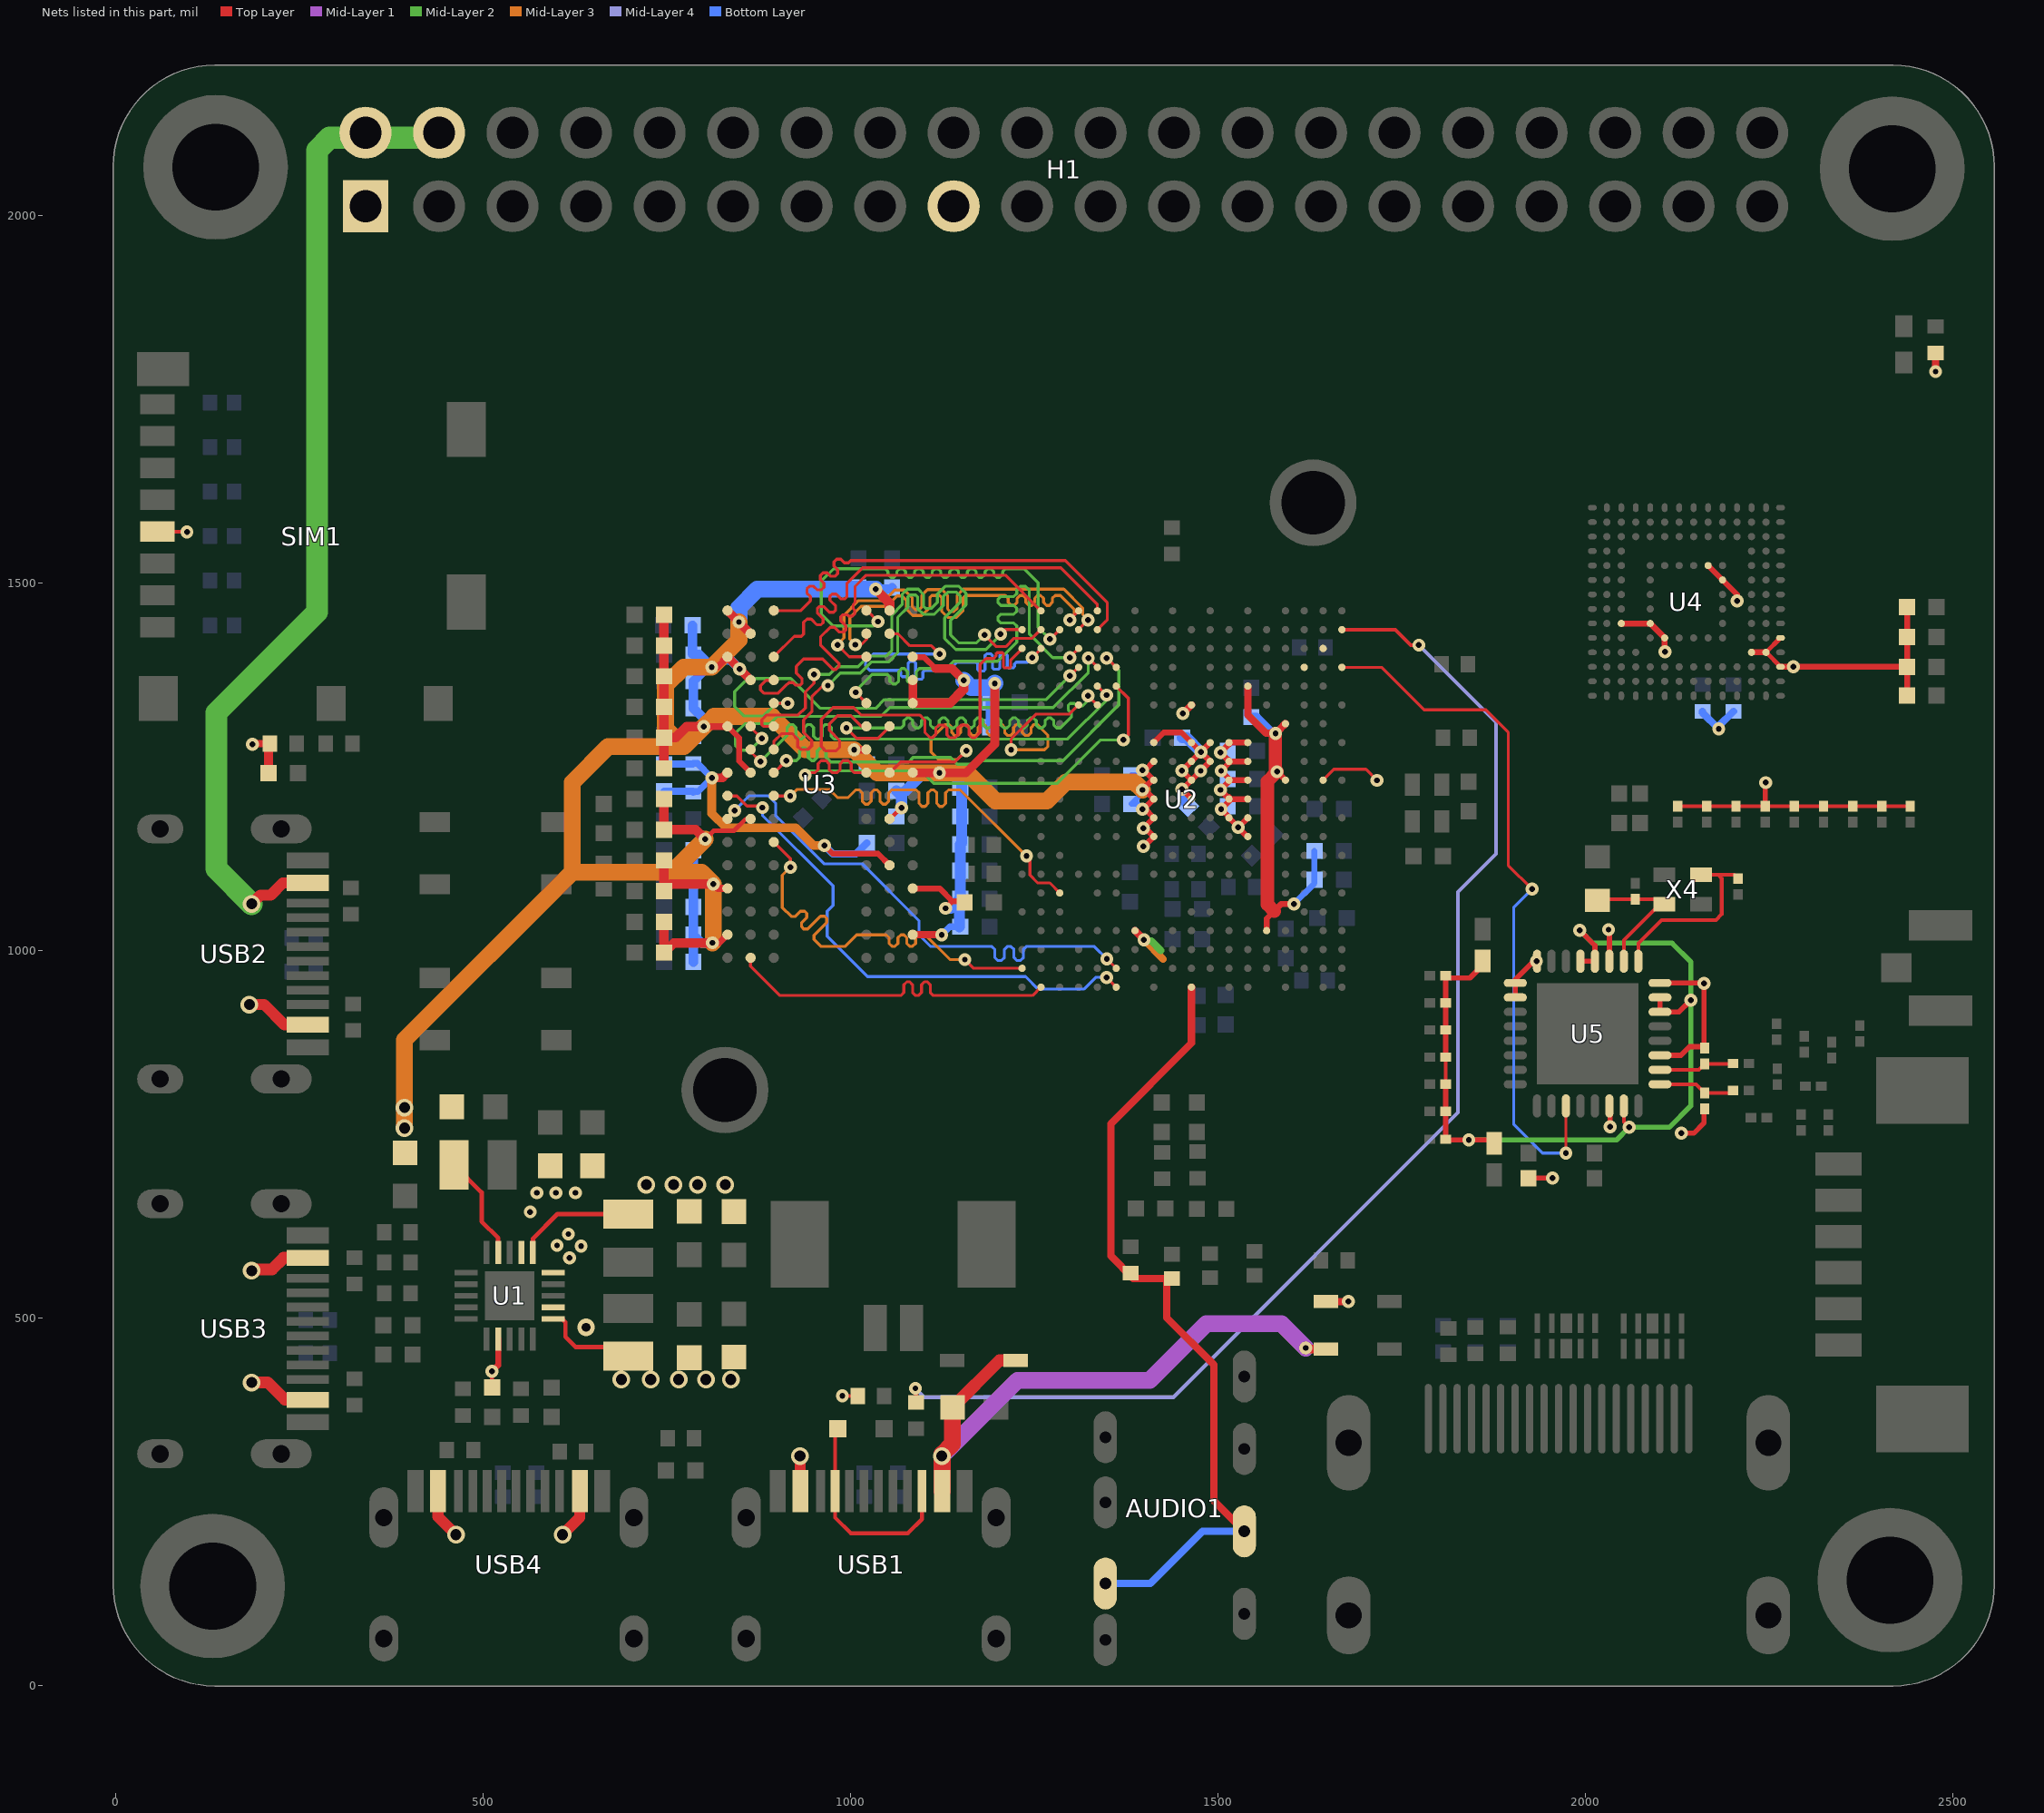
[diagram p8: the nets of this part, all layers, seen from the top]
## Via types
v1: diameter 17.7, hole 7.9, Top Layer to Bottom Layer, 439 vias
v2: diameter 18, hole 8, Top Layer to Bottom Layer, 138 vias
v3: diameter 24, hole 15, Top Layer to Bottom Layer, 19 vias
v4: diameter 24, hole 12, Top Layer to Bottom Layer, 2 vias

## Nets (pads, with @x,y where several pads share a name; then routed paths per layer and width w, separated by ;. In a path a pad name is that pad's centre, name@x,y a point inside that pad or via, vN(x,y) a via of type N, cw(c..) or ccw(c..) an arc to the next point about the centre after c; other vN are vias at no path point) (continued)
SDQ4: U2.U3 U3.B8 | length 588.5
  Top Layer w4: U3.B8@1053.38,1430.77 1064.8,1430.77 1080.77,1414.8 1109.97,1414.8 v1(1121.19,1403.58) ; v1(1247.19,1398.58) 1259.09,1410.48 U2.U3@1259.09,1411.08
  Bottom Layer w4: v1(1121.19,1403.58) 1031.24,1403.58 1020.46,1392.8 1020.46,1386.96 1026.3,1381.11 1066.13,1381.11 1068.47,1378.77 1068.47,1374.68 1070.47,1372.68 1076.47,1372.68 1078.47,1374.68 1078.47,1391.11 1080.47,1393.11 1086.47,1393.11 1088.47,1391.11 1088.47,1371.11 1090.47,1369.11 1096.47,1369.11 1098.47,1371.11 1098.47,1378.77 1100.82,1381.11 1133.96,1381.11 1145.05,1392.2 1170.77,1392.2 1173.11,1389.85 1173.11,1382.2 1175.11,1380.2 1181.11,1380.2 1183.11,1382.2 1183.11,1401.61 1185.11,1403.61 1191.11,1403.61 1193.11,1401.61 1193.11,1384.71 1195.11,1382.71 1201.11,1382.71 1203.11,1384.71 1203.11,1401.61 1205.11,1403.61 1211.11,1403.61 1213.11,1401.61 1213.11,1386.54 1215.11,1384.54 1221.11,1384.54 1223.11,1386.54 1223.11,1389.85 1225.46,1392.2 1240.81,1392.2 v1(1247.19,1398.58)
SDQ5: U2.P1 U3.C3 | length 602.6
  Top Layer w4: U3.C3@895.56,1399.66 923.48,1427.58 933.19,1427.58 936.19,1430.58 936.19,1446.58 940.71,1451.1 946.37,1451.1 954.21,1443.26 959.87,1443.26 962.7,1446.09 962.7,1451.75 954.86,1459.59 954.86,1465.25 957.69,1468.08 963.34,1468.08 971.19,1460.23 976.84,1460.23 979.67,1463.06 979.67,1468.72 971.83,1476.56 971.83,1482.22 974.66,1485.05 980.31,1485.05 986.78,1478.58 992.19,1478.58 995.19,1481.58 995.19,1499.58 1016.19,1520.58 1286.19,1520.58 1335.8,1470.97 U2.P1@1335.8,1462.17
SDQ6: U2.T2 U3.A7 | length 668.6
  Top Layer w4: U3.A7@1020.75,1462.51 1022.26,1462.51 v1(1037.19,1447.58) ; v1(1271.19,1423.58) 1271.59,1423.58 U2.T2@1284.68,1436.67
  Mid-Layer 2 w4: v1(1037.19,1447.58) 1031.19,1441.58 976.19,1441.58 960.19,1457.58 960.19,1502.58 977.19,1519.58 1046.94,1519.58 1050.94,1515.58 1050.94,1511.58 1054.94,1507.58 1058.94,1507.58 1062.94,1511.58 1062.94,1515.58 1066.94,1519.58 1070.94,1519.58 1074.94,1515.58 1074.94,1511.58 1078.94,1507.58 1082.94,1507.58 1086.94,1511.58 1086.94,1515.58 1090.94,1519.58 1094.94,1519.58 1098.94,1515.58 1098.94,1511.58 1102.94,1507.58 1106.94,1507.58 1110.94,1511.58 1110.94,1515.58 1114.94,1519.58 1118.94,1519.58 1122.94,1515.58 1122.94,1511.58 1126.94,1507.58 1130.94,1507.58 1134.94,1511.58 1134.94,1515.58 1138.94,1519.58 1142.94,1519.58 1146.94,1515.58 1146.94,1511.58 1150.94,1507.58 1154.94,1507.58 1158.94,1511.58 1158.94,1515.58 1162.94,1519.58 1166.94,1519.58 1170.94,1515.58 1170.94,1511.58 1174.94,1507.58 1178.94,1507.58 1182.94,1511.58 1182.94,1515.58 1186.94,1519.58 1190.94,1519.58 1194.94,1515.58 1194.94,1511.58 1198.94,1507.58 1202.94,1507.58 1206.94,1511.58 1206.94,1515.58 1210.94,1519.58 1236.19,1519.58 1255.19,1500.58 1255.19,1439.58 v1(1271.19,1423.58)
SDQ7: U2.P2 U3.A3 | length 608.7
  Top Layer w4: U3.A3@895.9,1462.26 931.87,1462.26 945.52,1475.91 945.52,1481.56 940.67,1486.41 940.67,1492.06 944.21,1495.6 949.87,1495.6 954.71,1490.76 960.37,1490.76 963.9,1494.29 963.9,1499.95 959.06,1504.79 959.06,1510.45 962.59,1513.98 968.25,1513.98 973.09,1509.14 978.75,1509.14 982.29,1512.68 982.29,1518.33 977.44,1523.18 977.44,1528.83 980.98,1532.37 986.63,1532.37 991.48,1527.52 997.13,1527.52 1000.19,1530.58 1292.19,1530.58 1349.19,1473.58 1349.19,1449.85 1347.46,1448.11 1347.3,1448.11 U2.P2@1335.86,1436.67
SDQ8: U2.P5 U3.G2 | length 642.7
  Top Layer w4: U3.G2@861.15,1273.53 v1(877.64,1257.04) ; U2.P5@1335.87,1359.9 v1(1348.19,1347.58)
  Mid-Layer 2 w4: v1(877.64,1257.04) 913.63,1293.03 913.63,1303.58 917.63,1307.58 921.63,1307.58 925.63,1303.58 925.63,1291.8 929.63,1287.8 933.63,1287.8 937.63,1291.8 937.63,1303.58 941.63,1307.58 945.63,1307.58 949.63,1303.58 949.63,1291.8 953.63,1287.8 957.63,1287.8 961.63,1291.8 961.63,1303.58 965.63,1307.58 969.63,1307.58 973.63,1303.58 973.63,1291.8 977.63,1287.8 1295.41,1287.8 1348.19,1340.58 v1(1348.19,1347.58)
  other v1: 1348.19,1347.58
SDQ9: U2.V3 U3.F7 | length 661.6
  Top Layer w4: U3.F7@1021.56,1305.16 1014.61,1305.16 1000.19,1319.58 982.19,1319.58 971.19,1308.58 971.19,1299.58 985.19,1285.58 985.19,1276.58 980.19,1271.58 966.19,1271.58 960.19,1277.58 960.19,1314.58 976.19,1330.58 1004.19,1330.58 1014.19,1320.58 1093.91,1320.58 1101.19,1313.3 1101.19,1296.58 1108.19,1289.58 1112.04,1289.58 1116.04,1293.58 1116.04,1302.8 1120.04,1306.8 1127.04,1306.8 1131.04,1302.8 1131.04,1293.58 1135.04,1289.58 1142.04,1289.58 1146.04,1293.58 1146.04,1302.8 1150.04,1306.8 1157.04,1306.8 1161.04,1302.8 1161.04,1293.58 1165.04,1289.58 1169.19,1289.58 1176.19,1296.58 1176.19,1389.03 1184.35,1397.19 1194.43,1397.19 1197.94,1400.71 1197.94,1403.92 1199.44,1405.42 1206.44,1405.42 1207.94,1403.92 1207.94,1386.04 1209.44,1384.54 1216.44,1384.54 1217.94,1386.04 1217.94,1395.33 U2.V3@1233.5,1410.89
SDQ10: U2.P4 U3.F2 | length 635.8
  Top Layer w4: U3.F2@864.23,1305.03 864.23,1303.54 v1(879.19,1288.58) ; v1(1323.46,1397.89) U2.P4@1335.86,1385.49
  Mid-Layer 2 w4: v1(879.19,1288.58) 863.19,1272.58 850.19,1272.58 843.19,1279.58 843.19,1295.58 856.19,1308.58 890.19,1308.58 900.19,1318.58 1041.19,1318.58 1053.19,1330.58 1275.65,1330.58 1323.46,1378.38 v1(1323.46,1397.89)
SDQ11: U2.R4 U3.E3 | length 641.4
  Top Layer w4: U3.E3@892.65,1336.52 v1(914.37,1336.52) ; v1(1298.58,1373.8) U2.R4@1310.27,1385.49
  Mid-Layer 2 w4: v1(914.37,1336.52) 898.87,1336.52 881.46,1319.11 855.46,1319.11 842.46,1332.11 842.46,1352.11 860.46,1370.11 918.66,1370.11 959.19,1329.58 1034.19,1329.58 1046.19,1341.58 1266.36,1341.58 v1(1298.58,1373.8)
SDQ12: U2.R6 U3.H8 | length 660.9
  Top Layer w4: U3.H8@1053.38,1241.79 1068.17,1256.58 1141.92,1256.58 v1(1157.46,1272.11) ; v1(1218.46,1273.11) 1218.46,1287.8 1252.46,1321.8 1297.76,1321.8 U2.R6@1310.27,1334.31
  Mid-Layer 3 w4: v1(1157.46,1272.11) 1145.46,1260.11 1119.46,1260.11 1109.46,1270.11 1109.46,1287.8 1129.24,1307.58 1133.72,1307.58 1137.72,1303.58 1137.72,1296.58 1141.72,1292.58 1145.72,1292.58 1149.72,1296.58 1149.72,1303.58 1153.72,1307.58 1157.72,1307.58 1161.72,1303.58 1161.72,1296.58 1165.72,1292.58 1169.72,1292.58 1173.72,1296.58 1173.72,1303.58 1177.72,1307.58 1181.72,1307.58 1185.72,1303.58 1185.72,1296.58 1189.72,1292.58 1193.72,1292.58 1197.72,1296.58 1197.72,1303.58 1201.72,1307.58 1205.72,1307.58 1209.72,1303.58 1209.72,1296.58 1213.72,1292.58 1217.72,1292.58 1221.72,1296.58 1221.72,1303.58 1225.72,1307.58 1229.72,1307.58 1233.72,1303.58 1233.72,1296.58 1237.72,1292.58 1241.72,1292.58 1245.72,1296.58 1245.72,1303.58 1249.72,1307.58 1253.99,1307.58 1268.46,1293.11 1268.46,1277.61 1263.96,1273.11 v1(1218.46,1273.11)
  other v1: 1218.46,1273.11
SDQ13: U2.N4 U3.H3 | length 652.7
  Top Layer w4.5: U3.H3@895.9,1241.79 v1(912.46,1258.35) ; v1(1348.46,1397.8) 1349.13,1397.8 U2.N4@1361.45,1385.49
  Mid-Layer 2 w4.5: v1(912.46,1258.35) 926.1,1258.35 930.6,1262.85 930.6,1271.08 935.1,1275.58 938.1,1275.58 942.6,1271.08 942.6,1262.85 947.1,1258.35 950.1,1258.35 954.6,1262.85 954.6,1271.08 959.1,1275.58 962.1,1275.58 966.6,1271.08 966.6,1262.85 972.87,1256.58 1079.19,1256.58 1085.19,1262.58 1136.19,1262.58 1145.19,1253.58 1166.19,1253.58 1170.96,1258.35 1288.96,1258.35 1365.19,1334.58 1365.19,1381.06 v1(1348.46,1397.8)
  other v1: 1348.46,1397.8
SDQ14: U2.P6 U3.F8 | length 620.7
  Top Layer w4: v1(994.46,1302.8) 1008.46,1288.8 1037.39,1288.8 U3.F8@1053.38,1304.78 ; v1(1322.92,1346.66) 1335.27,1334.31 U2.P6@1335.86,1334.31
  Mid-Layer 2 w4: v1(994.46,1302.8) 1068.61,1302.8 1072.61,1306.8 1072.61,1312.58 1076.61,1316.58 1080.61,1316.58 1084.61,1312.58 1084.61,1306.8 1088.61,1302.8 1092.61,1302.8 1096.61,1306.8 1096.61,1312.58 1100.61,1316.58 1104.61,1316.58 1108.61,1312.58 1108.61,1306.8 1112.61,1302.8 1116.61,1302.8 1120.61,1306.8 1120.61,1312.58 1124.61,1316.58 1128.61,1316.58 1132.61,1312.58 1132.61,1306.8 1136.61,1302.8 1140.61,1302.8 1144.61,1306.8 1144.61,1312.58 1148.61,1316.58 1152.61,1316.58 1156.61,1312.58 1156.61,1306.8 1160.61,1302.8 1164.61,1302.8 1168.61,1306.8 1168.61,1312.58 1172.61,1316.58 1176.61,1316.58 1180.61,1312.58 1180.61,1306.8 1184.61,1302.8 1188.61,1302.8 1192.61,1306.8 1192.61,1312.58 1196.61,1316.58 1200.61,1316.58 1204.61,1312.58 1204.61,1306.8 1208.61,1302.8 1212.61,1302.8 1216.61,1306.8 1216.61,1312.58 1220.61,1316.58 1224.61,1316.58 1228.61,1312.58 1228.61,1306.8 1232.61,1302.8 1236.61,1302.8 1240.61,1306.8 1240.61,1312.58 1244.61,1316.58 1248.61,1316.58 1252.61,1312.58 1252.61,1306.8 1256.61,1302.8 1260.61,1302.8 1264.61,1306.8 1264.61,1312.58 1268.61,1316.58 1272.61,1316.58 1276.61,1312.58 1276.61,1306.8 1280.61,1302.8 1285.41,1302.8 1300.38,1317.77 1300.38,1323.43 1296.09,1327.72 1296.09,1333.37 1298.92,1336.2 1304.57,1336.2 1308.08,1332.7 1315.31,1332.7 1323.81,1341.2 v1@1323.81,1345.4
SDQ15: U2.N5 U3.H7 | length 681
  Top Layer w4: v1(938.19,1238.58) 941.77,1242.16 951.88,1242.16 955.88,1246.16 955.88,1254.35 959.88,1258.35 966.88,1258.35 970.88,1254.35 970.88,1246.16 974.88,1242.16 981.88,1242.16 985.88,1246.16 985.88,1254.35 989.88,1258.35 996.88,1258.35 1000.88,1254.35 1000.88,1246.16 1004.88,1242.16 U3.H7@1021.56,1242.16
  Top Layer w4.5: U2.N5@1361.39,1359.8 1378.19,1342.99 1378.19,1293.58 v1(1371.19,1286.58)
  Mid-Layer 2 w4: v1(938.19,1238.58) 944.19,1244.58 1096.19,1244.58 1113.33,1227.44 1281.05,1227.44 1340.19,1286.58 v1(1371.19,1286.58)
  other v1: 938.19,1238.58
SDQM0: U2.U1 U3.D3 | length 648.5
  Top Layer w4: U3.D3@895.9,1367.77 U3.D3@892.65,1367.77 ; U3.D3@895.9,1368.02 U3.D3@892.65,1367.77 ; U2.U1@1259.09,1462.27 1210.77,1510.58 1021.19,1510.58 1006.19,1495.58 1006.19,1473.58 1003.66,1471.05 1003.66,1465.39 1005.52,1463.53 1005.52,1457.87 1002.69,1455.04 997.04,1455.04 995.17,1456.91 989.52,1456.91 986.69,1454.08 986.69,1448.42 993.39,1441.72 993.39,1436.06 990.56,1433.23 984.9,1433.23 978.2,1439.94 972.55,1439.94 959.19,1426.58 959.19,1415.58 984.19,1390.58 984.19,1386.58 980.19,1382.58 976.19,1382.58 962.19,1396.58 936.19,1396.58 926.19,1386.58 926.19,1377.41 934.02,1369.58 934.02,1363.92 931.19,1361.09 925.53,1361.09 921.95,1364.68 916.29,1364.68 911.59,1359.98 911.46,1360.11 901.46,1350.11 882.06,1350.11 877.46,1354.72 877.46,1360.11 885.12,1367.77 U3.D3@892.65,1367.77
SDQM1: U2.R3 U3.E7 | length 646.4
  Top Layer w4: v1(1006.9,1351.26) U3.E7@1021.88,1336.28 ; v1(1298.19,1398.58) 1310.27,1410.66 U2.R3@1310.27,1411.08
  Mid-Layer 2 w4: v1(1006.9,1351.26) 1006.9,1353.29 1029.19,1375.58 1050.19,1375.58 1053.45,1372.32 1053.45,1366.58 1057.45,1362.58 1061.45,1362.58 1065.45,1366.58 1065.45,1379.58 1069.45,1383.58 1073.45,1383.58 1077.45,1379.58 1077.45,1366.58 1081.45,1362.58 1085.45,1362.58 1089.45,1366.58 1089.45,1379.58 1093.45,1383.58 1130.19,1383.58 1140.19,1393.58 1200.19,1393.58 1226.19,1419.58 1226.19,1441.59 1222.19,1445.59 1204.47,1445.59 1200.47,1449.59 1200.47,1453.59 1204.47,1457.59 1222.19,1457.59 1226.19,1461.59 1226.19,1465.59 1222.19,1469.59 1204.47,1469.59 1200.47,1473.59 1200.47,1477.59 1204.47,1481.59 1222.19,1481.59 1226.19,1485.59 1226.19,1490.58 1231.19,1495.58 1238.19,1495.58 1243.19,1490.58 1243.19,1430.58 1275.19,1398.58 v1(1298.19,1398.58)
  other v1: 1006.9,1351.26 1298.19,1398.58
SDQS0N: U2.R1 U3.B7 | length 562.5
  Top Layer w4: v1(1006.46,1416.11) 1014.46,1416.11 1021.88,1423.54 U3.B7@1021.88,1430.77 ; v1(1298.19,1449.58) 1298.19,1450.19 U2.R1@1310.27,1462.27
  Mid-Layer 3 w4: v1(1006.46,1416.11) 998.96,1423.61 998.96,1452.86 1014.21,1468.11 1048.86,1468.11 1063.33,1482.58 1069.8,1482.58 1076.06,1476.31 1076.06,1464.39 1084.5,1455.96 1096.88,1455.96 1108.12,1467.2 1108.12,1480.77 1110.46,1483.11 1121.01,1483.11 1124.06,1480.06 1124.06,1461.39 1132.34,1453.11 1144.04,1453.11 1153.06,1462.14 1153.06,1480.06 1156.12,1483.11 1210.57,1483.11 1214.57,1479.11 1214.57,1473.59 1218.57,1469.59 1222.57,1469.59 1226.57,1473.59 1226.57,1479.11 1230.57,1483.11 1234.57,1483.11 1238.57,1479.11 1238.57,1473.59 1242.57,1469.59 1246.57,1469.59 1250.57,1473.59 1250.57,1479.11 1254.57,1483.11 1258.57,1483.11 1262.57,1479.11 1262.57,1473.59 1266.57,1469.59 1270.57,1469.59 1274.57,1473.59 1274.57,1479.11 1278.57,1483.11 1285.66,1483.11 1304.19,1464.58 1304.19,1455.58 v1(1298.19,1449.58)
  other v1: 1298.19,1449.58
SDQS0P: U2.R2 U3.C7 | length 562.8
  Top Layer w4: v1(982.19,1415.58) 998.11,1399.66 U3.C7@1021.56,1399.66 ; U2.R2@1310.21,1436.57 v1(1323.19,1449.58)
  Mid-Layer 3 w4: v1(982.19,1415.58) 982.19,1416.58 990.96,1425.35 990.96,1456.17 1010.9,1476.11 1045.55,1476.11 1060.01,1490.58 1073.11,1490.58 1084.06,1479.63 1084.06,1467.71 1087.81,1463.96 1093.57,1463.96 1097.06,1467.45 1097.06,1483.37 1104.81,1491.11 1124.32,1491.11 1132.06,1483.37 1132.06,1464.71 1135.66,1461.11 1140.72,1461.11 1145.06,1465.45 1145.06,1483.37 1153.27,1491.58 1290.19,1491.58 1315.96,1465.81 1315.96,1456.81 v1(1323.19,1449.58)
SDQS1N: U2.V2 U3.G3 | length 686.2
  Top Layer w4: U3.G3@895.56,1273.66 895.56,1284.21 906.46,1295.11 920.66,1295.11 928.19,1287.58 928.19,1277.58 932.19,1273.58 942.19,1273.58 947.19,1278.58 947.19,1285.58 936.19,1296.58 936.19,1313.7 947.46,1324.97 947.46,1325.75 ; 947.46,1326.11 947.46,1345.33 962.71,1360.58 v1(969.19,1360.58) ; v1(1204.19,1430.58) 1210.28,1436.67 U2.V2@1233.5,1436.67
  Mid-Layer 2 w4: v1(969.19,1360.58) 986.19,1377.58 1013.19,1377.58 1028.19,1392.58 1051.5,1392.58 1064.19,1405.27 1064.19,1453.27 1078.19,1467.27 1078.19,1481.27 1080.5,1483.58 1088.88,1483.58 1091.19,1481.27 1091.19,1465.27 1098.88,1457.58 1114.19,1457.58 1126.19,1469.58 1126.19,1481.58 1132.19,1487.58 1144.19,1487.58 1149.19,1482.58 1149.19,1473.58 1128.19,1452.58 1128.19,1424.58 1143.19,1409.58 1184.19,1409.58 1204.19,1429.58 v1(1204.19,1430.58)
SDQS1P: U2.U2 U3.F3 | length 687.6
  Top Layer w4: U3.F3@895.51,1305.11 881.46,1305.11 879.46,1307.11 879.46,1314.11 885.92,1320.58 928.92,1320.58 938.46,1330.11 938.46,1351.89 950.19,1363.62 v1(950.19,1375.58) ; v1(1182.19,1429.58) 1198.19,1413.58 1211.19,1413.58 1222.41,1424.8 1247.22,1424.8 U2.U2@1259.09,1436.67
  Mid-Layer 2 w4: v1(950.19,1375.58) 971.19,1375.58 981.69,1386.08 1010.08,1386.08 1024.58,1400.58 1048.19,1400.58 1056.19,1408.58 1056.19,1456.58 1070.19,1470.58 1070.19,1484.58 1077.19,1491.58 1092.19,1491.58 1099.19,1484.58 1099.19,1468.58 1102.19,1465.58 1110.19,1465.58 1118.19,1473.58 1118.19,1484.89 1128.88,1495.58 1147.5,1495.58 1157.19,1485.89 1157.19,1470.27 1136.19,1449.27 1136.19,1429.58 1147.19,1418.58 1171.19,1418.58 v1(1182.19,1429.58)
SODT0: U2.N20 U3.K1 | length 718.7
  Top Layer w4: U3.K1@832.91,1178.8 842.19,1188.08 v1(842.19,1190.58) ; v1(1348.69,988.8) U2.N20@1361.45,976.05
  Bottom Layer w4: v1(842.19,1190.58) 862.19,1210.58 888.19,1210.58 898.19,1200.58 898.19,1183.58 963.66,1118.11 1015.66,1118.11 1093.19,1040.58 1093.19,1021.58 1109.19,1005.58 1192.27,1005.58 1196.27,1001.58 1196.27,990.58 1200.27,986.58 1205.27,986.58 1209.27,990.58 1209.27,1001.58 1213.27,1005.58 1218.27,1005.58 1222.27,1001.58 1222.27,990.58 1226.27,986.58 1231.27,986.58 1235.27,990.58 1235.27,1001.58 1239.27,1005.58 1331.91,1005.58 v1(1348.69,988.8)
  other v1: 842.19,1190.58
SODT1: U2.N21 U3.J1 | length 707.5
  Top Layer w4: U3.J1@832.91,1210.29 845.48,1210.29 859.19,1196.58 878.19,1196.58 v1(880.19,1194.58) ; v1(1348.19,963.58) 1348.09,963.68 1348.09,963.8 U2.N21@1361.45,950.45
  Bottom Layer w4: v1(880.19,1194.58) 880.19,1184.09 976.19,1088.09 976.19,1061.58 968.19,1053.58 968.19,1019.58 1023.19,964.58 1238.19,964.58 1255.19,947.58 1317.34,947.58 1333.34,963.58 v1(1348.19,963.58)
SRAS: U2.T16 U3.J3 | length 601.8
  Top Layer w4: U3.J3@895.9,1210.29 v1(917.96,1210.29) ; v1(1239.46,1128.8) 1243.94,1124.32 1243.94,1102.63 1254.46,1092.11 1270.97,1092.11 U2.T16@1284.68,1078.41
  Mid-Layer 3 w4: v1(917.96,1210.29) 926.78,1219.11 971.46,1219.11 982.46,1208.11 996.72,1208.11 1007.19,1218.58 1011.96,1218.58 1015.96,1214.58 1015.96,1203.25 1019.96,1199.25 1023.96,1199.25 1027.96,1203.25 1027.96,1214.58 1031.96,1218.58 1035.96,1218.58 1039.96,1214.58 1039.96,1203.25 1043.96,1199.25 1047.96,1199.25 1051.96,1203.25 1051.96,1214.58 1055.96,1218.58 1089.3,1218.58 1093.3,1214.58 1093.3,1200.11 1097.3,1196.11 1101.3,1196.11 1105.3,1200.11 1105.3,1214.58 1109.3,1218.58 1113.3,1218.58 1117.3,1214.58 1117.3,1200.11 1121.3,1196.11 1125.3,1196.11 1129.3,1200.11 1129.3,1214.58 1133.3,1218.58 1149.19,1218.58 1238.97,1128.8 v1(1239.46,1128.8)
  other v1: 917.96,1210.29
SRST: U2.U21 U3.T2 | length 483.5
  Top Layer w4: U3.T2@864.06,990.16 864.06,978.71 903.83,938.94 1068.48,938.94 1072.48,942.94 1072.48,953.58 1076.48,957.58 1080.48,957.58 1084.48,953.58 1084.48,942.94 1088.48,938.94 1092.48,938.94 1096.48,942.94 1096.48,953.58 1100.48,957.58 1104.48,957.58 1108.48,953.58 1108.48,942.94 1112.48,938.94 1247.58,938.94 U2.U21@1259.09,950.45
SVREF: C58.2 C59.2 C60.2 R10.1 R11.2 U3.H1 U3.M8 | length 560.4
  Top Layer w8: v1(964.46,1143.11) 975.77,1131.8 1037.39,1131.8 U3.M8@1053.06,1116.16
  Top Layer w12: v1(811.25,1235.11) 826.23,1235.11 U3.H1@832.91,1241.79
  Mid-Layer 3 w12: v1(811.25,1235.11) 811.25,1186.52 830.66,1167.11 925.46,1167.11 949.46,1143.11 v1(964.46,1143.11)
  Bottom Layer w9: R11.2@785.19,1216.59 792.72,1216.59 v1(811.25,1235.11) 791.78,1254.58 R10.1@786.19,1254.58
  Bottom Layer w10: C60.2@746.19,1216.59 785.19,1216.59 R11.2@786.19,1215.58 ; C59.2@746.19,1253.57 785.19,1253.57 R10.1@786.19,1254.58 ; v1(964.46,1143.11) 975.99,1131.58 1007.18,1131.58 C58.2@1022.18,1146.58
SWE: U2.V20 U3.L3 | length 602.6
  Top Layer w4: U3.L3@895.9,1147.3 918.19,1125.01 v1(918.19,1113.58) ; v1(1155.46,987.8) 1167.31,975.95 U2.V20@1233.44,975.95
  Mid-Layer 3 w4: v1(918.19,1113.58) 907.19,1102.58 907.19,1058.58 919.25,1046.52 924.91,1046.52 931.94,1053.55 937.59,1053.55 940.42,1050.72 940.42,1045.07 933.39,1038.04 933.39,1032.38 936.22,1029.55 941.88,1029.55 959.1,1046.77 964.76,1046.77 967.58,1043.95 967.58,1038.29 950.36,1021.07 950.36,1015.41 ; 950.42,1015.35 960.19,1005.58 992.19,1005.58 1008.19,1021.58 1048.48,1021.58 1052.48,1017.58 1052.48,1009.74 1056.48,1005.74 1060.48,1005.74 1064.48,1009.74 1064.48,1017.58 1068.48,1021.58 1072.48,1021.58 1076.48,1017.58 1076.48,1009.74 1080.48,1005.74 1084.48,1005.74 1088.48,1009.74 1088.48,1017.58 1092.48,1021.58 1101.46,1021.58 1135.24,987.8 v1(1155.46,987.8)
  other v1: 1155.46,987.8
TV_OUT: AUDIO1.4 AUDIO1.7 D12.2 R30.2 U2.J21 | length 1105.9
  Top Layer w10: U2.J21@1463.76,950.35 1463.76,874.15 1354.19,764.58 1354.19,584.58 1384.59,554.18 1430.19,554.18 1430.19,500.58 1494.19,436.58 1494.19,251.58 AUDIO1.4@1535.69,210.08
  Bottom Layer w10: AUDIO1.7@1346.69,139.18 1407.79,139.18 1478.69,210.08 AUDIO1.4@1535.69,210.08
TXPA_ON: C109.2 L5.1 U5.2 | length 102.9
  Top Layer w5: U5.2@2101.27,837.9 2154.12,837.9 L5.1@2162.03,845.81 2199.84,845.81 C109.2@2200.6,846.58
TXPA_OP: C123.2 L4.1 U5.1 | length 105.6
  Top Layer w5: U5.1@2101.27,818.22 2150.19,818.22 L4.1@2162.03,806.38 2197.4,806.38 C123.2@2200.6,809.58
UART1_CTS: U2.B3
UART1_RTS: U2.C4
UART1_TX: U2.A4 U5.27 | length 976.8
  Top Layer w4: U2.A4@1668.48,1385.39 1722.38,1385.39 1780.19,1327.58 1864.19,1327.58 1894.69,1297.08 1894.69,1116.08 v1(1927.19,1083.58) ; v1@1967.66,724.62 v1(1973.19,724.58) 1973.32,724.71 U5.27@1973.32,788.69
  Bottom Layer w4: v1(1927.19,1083.58) 1902.19,1058.58 1902.19,763.87 1941.48,724.58 v1(1973.19,724.58)
USB0_ID: D20.2 USB1.A5 USB1.B5 | length 295.5
  Top Layer w5: USB1.A5@978.99,264.88 978.99,345.88 D20.2@982.69,349.58
  Top Layer w5.4: USB1.A5@978.99,264.88 978.99,228.78 1000.19,207.58 1078.19,207.58 1097.19,226.58 1097.19,264.78 USB1.B5@1097.09,264.88
USB_ID: R34.1 U2.A2 | length 1737.1
  Top Layer w5: v1(1088.19,404.58) 1089.19,403.58 R34.1@1089.19,385.58 ; U2.A2@1668.48,1436.57 1741.2,1436.57 1762.19,1415.58 v1(1773.19,1415.58)
  Mid-Layer 4 w5: v1(1088.19,404.58) 1100.19,392.58 1439.19,392.58 1826.19,779.58 1826.19,1079.58 1878.19,1131.58 1878.19,1310.58 v1(1773.19,1415.58)
VBUS: C2.1 C7.1 C10.1 D1.2 D22.2 H1.2 H1.4 U1.2 U1.17 U1.20 USB1.A4B9 USB1.B4A9 USB2.A4B9 USB2.B4A9 USB3.A4B9 USB3.B4A9 USB4.A4B9 USB4.B4A9 | length 2656.4
  Top Layer w12: v1(1619.19,459.58) 1620.69,458.08 D22.2@1646.99,458.08
  Top Layer w15: v3(182.19,926.58) 202.19,926.58 229.69,899.08 USB2.B4A9@261.49,899.08 ; v3(185.19,1063.58) 197.19,1075.58 211.19,1075.58 227.69,1092.08 USB2.A4B9@261.49,1092.08 ; USB4.A4B9@438.69,264.88 438.69,230.08 v3(463.19,205.58) ; v3(608.19,205.58) 631.69,229.08 USB4.B4A9@631.69,264.88 ; v3(931.19,312.58) 931.69,312.08 USB1.A4B9@931.69,264.88 ; v3(1124.19,312.58) v3@1124.69,312.08
  Top Layer w16: v3(185.19,412.58) 207.19,412.58 230.69,389.08 USB3.B4A9@261.49,389.08 ; v3(185.19,564.58) 187.19,566.58 213.19,566.58 228.69,582.08 USB3.A4B9@261.49,582.08
  Top Layer w17: C2.1@1138.66,378.58 1202.66,442.58 D1.2@1224.39,442.58
  Top Layer w23: USB1.B4A9@1124.69,264.88 1124.69,312.08 1124.69,315.08 1138.66,329.05 C2.1@1138.66,378.58
  Mid-Layer 1 w23: v3(1124.19,312.58) 1227.19,415.58 1407.19,415.58 1484.19,492.58 1586.19,492.58 v1(1619.19,459.58)
  Mid-Layer 2 w30: v3(185.19,1063.58) 137.19,1111.58 137.19,1323.58 274.19,1460.58 274.19,2088.58 291.19,2105.58 433.19,2105.58 H1.4@440.19,2112.58
  other v1: 617.58,582.2 633.35,597.95 600.74,599.03 616.09,614.38 564.19,644.58 573.19,670.58 599.19,670.58 625.72,670.58
  other v4: 640.19,487.58
VCC_DRAM: C11.1 C13.1 C17.2 C18.2 C19.2 C20.2 C30.2 C31.2 C32.2 C33.2 C34.2 C35.2 C36.2 C37.2 C38.2 C39.2 C40.2 C41.2 C42.2 C43.2 C44.2 C45.2 C46.2 C47.2 C48.2 C49.2 C50.2 C51.2 C52.2 C53.2 C54.2 C55.2 C56.2 C57.2 C61.2 C62.2 C63.2 C64.2 C65.2 L3.2 R10.2 U1.4 U2.L9 U2.L10 U2.L11 U2.L12 U2.L13 U3.A1 U3.A8 U3.B2 U3.C1 U3.C9 U3.D2 U3.D9 U3.E9 U3.F1 U3.G7 U3.H2 U3.H9 U3.K2 U3.K8 U3.N1 U3.N9 U3.R1 U3.R9 | length 5269.8
  Top Layer w6: L3.2@460.71,708.5 498.19,671.02 498.19,631.58 520.61,609.16 U1.4@520.61,589.6 ; v1(802.19,1151.58) 813.72,1163.11 841.46,1163.11 857.14,1178.8 U3.K2@864.4,1178.8 ; U3.K8@1053.38,1178.8 1068.69,1194.11 v1(1069.46,1194.11) ; U3.C9@1080.3,1399.27 U3.C9@1084.87,1399.27
  Top Layer w8: U3.F1@832.91,1304.78 848.46,1289.23 848.46,1257.74 U3.H2@864.4,1241.79 ; U3.N9@1084.56,1084.66 1121.11,1084.66 1138.69,1067.08 ; U3.C9@1084.87,1399.27 1099.98,1399.27 1115.65,1383.6 ; v1(1129.19,1057.58) 1138.69,1067.08 ; C32.2@1155.18,1065.58 1153.69,1067.08 1138.69,1067.08 ; v1(1397.19,1192.58) v1@1398.89,1192.58 ; v1(1397.19,1245.58) v1@1398.83,1245.58 ; v1(1398.19,1141.58) 1399.07,1141.58 U2.L13@1412.57,1155.08 1401.06,1166.58 v1@1398.48,1166.58 ; v1(1398.19,1166.58) v1@1398.48,1166.58 ; U2.L9@1412.57,1257.44 1400.71,1245.58 v1@1398.83,1245.58 ; v1@1398.48,1166.58 U2.L12@1412.57,1180.67 1400.65,1192.58 v1@1398.89,1192.58 ; v1@1398.83,1245.58 U2.L10@1412.57,1231.85 1410.46,1231.85 v1(1397.19,1218.58) 1400.24,1218.58 U2.L11@1412.57,1206.26 v1@1398.89,1192.58
  Top Layer w9: v1(800.19,1304.58) 831.98,1304.58 U3.F1@832.56,1305.16 ; v1(811.19,1385.58) 818.48,1385.58 U3.C1@832.56,1399.66 ; v1(812.19,1010.58) 821.48,1010.58 U3.R1@832.56,1021.66
  Top Layer w10: v1(813.19,1090.58) 819.11,1084.66 U3.N1@832.56,1084.66 ; v1(1004.94,1273.29) U3.G7@1021.88,1273.29 ; U3.R9@1084.56,1021.66 1123.64,1021.66 v1(1123.98,1021.32)
  Top Layer w12: U3.C1@832.91,1399.27 v1(848.98,1383.19) U3.D2@864.4,1367.77 ; U3.A1@832.91,1462.26 v1(848.19,1446.98) U3.B2@864.4,1430.77 ; U3.H9@1084.87,1241.79 v1(1121,1241.79) 1157.13,1241.79 1196.19,1280.85 v1(1196.19,1363.58) ; U3.E9@1084.87,1336.28 1084.87,1336.66 U3.D9@1084.87,1367.77 ; 1115.65,1383.6 1138.17,1383.6 v1(1154.19,1367.58)
  Top Layer w13: C54.2@746.2,1039.12 C48.2@746.2,997.35 759.43,1010.58 v1(812.19,1010.58) ; C57.2@746.2,1122.66 C50.2@746.2,1080.89 755.89,1090.58 v1(813.19,1090.58) ; C55.2@746.2,1206.2 C56.2@746.2,1164.43 789.34,1164.43 v1(802.19,1151.58) ; C49.2@746.2,1247.96 C35.2@746.2,1289.73 ; C53.2@746.2,1456.81 C43.2@746.2,1415.04 C36.2@746.2,1373.27 C42.2@746.2,1331.5 C35.2@746.2,1289.73 ; v1(800.19,1304.58) 777.19,1304.58 762.34,1289.73 C35.2@746.2,1289.73 ; v1(1034.19,1491.58) 1053.06,1472.71 U3.A8@1053.06,1462.66 ; U3.E9@1084.56,1336.66 1084.87,1336.66 1135.27,1336.66 1154.19,1355.58 v1(1154.19,1367.58)
  Mid-Layer 3 w23: v3(393.19,758.58) v3(393.19,786.58) 393.19,878.58 621.19,1106.58 ; v1(802.19,1151.58) 757.19,1106.58 ; v1(812.19,1010.58) 813.19,1011.58 v1(813.19,1090.58) 797.19,1106.58 757.19,1106.58 ; v1(848.19,1446.98) 848.19,1422.58 v1(811.19,1385.58) 773.19,1385.58 748.19,1360.58 748.19,1302.58 773.19,1277.58 ; v1(1397.19,1218.58) 1386.19,1229.58 1293.19,1229.58 1267.19,1203.58 1197.19,1203.58 1158.98,1241.79 v1(1121,1241.79) 1036.44,1241.79 v1(1004.94,1273.29) 938.48,1273.29 893.19,1318.58 814.19,1318.58 v1(800.19,1304.58) 773.19,1277.58 ; 621.19,1106.58 621.19,1228.58 670.19,1277.58 773.19,1277.58 ; 621.19,1106.58 757.19,1106.58
  Bottom Layer w8: v1(1397.19,1192.58) 1390.18,1199.59 C18.2@1382.16,1199.59 1397.19,1214.62 v1(1397.19,1218.58) 1397.19,1223.56 C20.2@1382.16,1238.59 1390.2,1238.59 v1(1397.19,1245.58)
  Bottom Layer w9: R10.2@786.19,1290.58 v1(800.19,1304.58) ; C34.2@786.2,1332.58 800.19,1318.59 800.19,1315.59 ; v1(1004.94,1273.29) 1022.18,1256.05 C41.2@1022.18,1253.58 ; C63.2@1062.2,1217.58 1075.19,1217.58 ; v1(1123.98,1021.32) 1135.24,1032.58 C30.2@1148.18,1032.58
  Bottom Layer w13: C46.2@785.18,1442.58 785.18,1403.58 C40.2@786.18,1402.58 794.19,1402.58 v1(811.19,1385.58) ; C38.2@786.2,984.58 C61.2@786.18,1021.58 ; C33.2@786.2,1136.58 C33.2@787.19,1136.58 ; v1(800.19,1304.58) 800.19,1315.59 C34.2@786.2,1329.58 786.2,1332.58 C64.2@786.2,1366.58 805.2,1385.58 v1(811.19,1385.58) ; v1(802.19,1151.58) C33.2@787.19,1136.58 ; v1(812.19,1010.58) 797.18,1010.58 C61.2@786.18,1021.58 ; v1(813.19,1090.58) 806.19,1097.58 C31.2@786.19,1097.58 ; v1(848.98,1383.19) 836.6,1395.58 821.19,1395.58 v1(811.19,1385.58) ; v1@1032.04,1493.73 v1(1034.19,1491.58) 1054.3,1491.58 C51.2@1056.46,1493.73 ; C47.2@1190.18,1303.58 C65.2@1190.18,1337.58 1196.19,1343.59 v1(1196.19,1363.58) ; C61.2@786.18,1021.58 C37.2@786.2,1059.58 C31.2@786.19,1097.58 ; C31.2@786.19,1097.58 786.19,1135.58 C33.2@787.19,1136.58
  Bottom Layer w15: C63.2@1062.2,1217.58 1069.46,1210.32 v1(1069.46,1194.11) ; 1075.19,1217.58 1099.4,1241.79 v1(1121,1241.79) 1144.98,1241.79 1151.19,1235.58 1151.19,1146.59 C52.2@1149.18,1144.58 C45.2@1149.18,1108.58 C39.2@1149.18,1070.58 C39.2@1148.18,1069.58 ; v1(1129.19,1057.58) 1136.18,1057.58 C39.2@1148.18,1069.58 ; C30.2@1148.18,1032.58 C39.2@1148.18,1069.58
  Bottom Layer w23: v1(848.19,1446.98) 848.19,1466.58 873.19,1491.58 v1(1034.19,1491.58) ; v1(1154.19,1367.58) 1164.19,1357.58 1190.19,1357.58 v1(1196.19,1363.58)
VD12D: C66.1 C67.1 C71.2 C102.2 C105.1 C106.1 C118.2 C120.1 L9.1 U5.6 U5.7 U5.12 U5.13 U5.31 | length 1197.7
  Top Layer w5: C105.1@1809.64,818.28 C67.1@1809.64,855.18 ; U5.31@2052.06,788.69 2052.06,766.71 v1(2059.19,759.58)
  Top Layer w7: C105.1@1809.64,818.28 C66.1@1809.64,781.38 1809.64,744.48 1811.54,742.58 v1(1841.19,742.58) 1867.96,742.58 C118.2@1872.66,737.88 ; C67.1@1809.64,855.18 C106.1@1809.64,892.08 C120.1@1809.64,928.98 1809.64,962.89 1842.78,962.89 L9.1@1859.92,980.03 ; v1(1992.19,1027.58) 2012.69,1007.08 U5.12@2012.69,985.54 U5.13@1993,985.54 ; U5.7@2101.27,936.33 U5.6@2101.27,916.64 2127.25,916.64 v1(2143.19,932.58)
  Mid-Layer 2 w7: v1(1841.19,742.58) 2042.19,742.58 v1(2059.19,759.58) 2113.9,759.58 2143.19,788.87 v1(2143.19,932.58) 2143.19,984.58 2117.54,1010.23 2009.54,1010.23 v1(1992.19,1027.58)
VDD33: C3.2 C26.2 C27.2 C28.2 C29.2 C68.2 C69.2 C70.2 C75.2 C76.2 C77.2 C81.2 C104.1 C107.2 C108.1 C116.2 C117.2 C124.1 D23.2 H1.1 H1.17 L4.2 L5.2 R16.1 R33.2 R48.2 R50.1 R51.1 R54.2 SIM1.4 U1.12 U2.D7 U2.D10 U2.E18 U2.F5 U2.J6 U2.M18 U4.C6 U4.E6 U4.F5 U4.J10 U4.K9 U4.M4 U4.N4 U4.P3 U4.P5 U5.3 U5.8 U5.11 U5.16 U5.17 U5.18 U5.30 | length 2356.1
  Top Layer w4: v1(1933.19,985.58) U5.16@1933.91,985.58 ; L5.2@2161.19,869.25 L5.2@2162.03,868.41
  Top Layer w5: SIM1.4@57.05,1569.97 96.8,1569.97 v1(97.19,1569.58) ; v1(988.83,394.29) R33.2@1009.82,394.28 ; D23.2@1646.99,522.58 D23.2@1649.95,522.58 ; C70.2@2125.27,1196.38 C108.1@2164.97,1196.38 C116.2@2204.68,1196.38 C69.2@2244.38,1196.38 C68.2@2284.08,1196.38 C104.1@2323.79,1196.38 C117.2@2363.49,1196.38 C107.2@2403.19,1196.38 C124.1@2441.72,1196.38
  Top Layer w6: v1(512.19,427.58) 512.19,406.3 C3.2@512.63,405.86 ; U4.P3@2265.14,1385.99 U4.N4@2245.46,1405.68 U4.P5@2265.13,1425.36
  Top Layer w7: U5.18@1904.42,936.33 U5.17@1904.42,956.01 1904.42,960.81 1929.15,985.54 U5.16@1933.95,985.54 ; R54.2@1921.32,690.54 R54.2@1922.32,690.54 v1(1955.19,690.58) ; v1(2031.19,1028.58) 2032.37,1027.4 U5.11@2032.37,985.54 ; U5.30@2032.37,788.69 2033.19,787.87 v1(2033.19,760.58) ; U5.3@2101.27,857.59 2129.7,857.59 2141.36,869.25 2161.19,869.25 v1(2161.19,955.58) 2160.76,956.01 U5.8@2101.27,956.01 ; v1(2130.19,751.58) 2147.19,751.58 2161.19,765.58 2161.19,784.94 L4.2@2162.03,785.78 ; C69.2@2244.38,1196.38 2244.38,1227.77 v1(2245.19,1228.58)
  Top Layer w8: v1(512.19,427.58) 520.61,436 U1.12@520.61,471.4 ; U2.E18@1566.12,1027.13 1566.12,1043.51 1576.36,1053.75 1586.19,1063.58 v1(1603.19,1063.58) ; v1(1580.19,1243.36) U2.D10@1591.71,1231.85 ; U4.C6@2048.61,1445.05 U4.E6@2087.97,1445.05 U4.F5@2107.67,1425.36 2107.67,1407.11 v1(2108.19,1406.58) ; U4.J10@2166.71,1523.8 U4.K9@2186.41,1504.11 2206.19,1484.32 v1(2206.19,1475.58) ; U4.M4@2225.78,1405.68 U4.N4@2245.46,1405.68 ; U4.P3@2265.14,1385.99 v1(2282.78,1385.99) ; v1@2283.19,1385.58 v1(2282.78,1385.99) ; C75.2@2437.34,1347.16 C76.2@2437.34,1385.85 ; C81.2@2437.34,1467.22 C77.2@2437.34,1426.53 C76.2@2437.34,1385.85 ; v1(2282.78,1385.99) 2437.19,1385.99 C76.2@2437.34,1385.85
  Top Layer w10: v1(186.19,1280.58) 187.19,1281.58 R16.1@210.19,1281.58 ; U2.M18@1386.98,1027.13 1399.19,1014.91 v1(1399.19,1014.58) ; v1(1452.19,1322.58) U2.J6@1463.76,1334.21 ; U2.F5@1540.53,1359.8 1540.53,1320.24 1565.19,1295.58 v1(1578.19,1295.58) v1@1584.19,1301.58 ; D23.2@1649.95,522.58 v1(1677.19,522.58) ; v1(2476.19,1787.58) R48.2@2476.19,1813.03 ; v1@1584.19,1301.58 1591.23,1308.62 U2.D7@1591.71,1308.62 1584.67,1301.58 v1@1584.19,1301.58
  Top Layer w12: C28.2@208.2,1241.58 208.2,1279.59 R16.1@210.19,1281.58
  Top Layer w18: 1576.36,1053.75 1567.19,1062.93 1567.19,1230.36 v1@1578.19,1241.36 ; v1(1578.19,1295.58) v1@1578.19,1241.36 ; v1(1580.19,1243.36) v1@1578.19,1241.36
  Mid-Layer 2 w10: v1(1399.19,1014.58) 1400.66,1013.11 1409.39,1013.11 1422.26,1000.24
  Mid-Layer 3 w10: v1(1399.19,1014.58) 1425.19,988.58
  Bottom Layer w8: v1(1603.19,1063.58) 1631.18,1091.57 C26.2@1631.18,1096.58 C29.2@1631.18,1135.58
  Bottom Layer w10: R51.1@2159.19,1325.58 2159.19,1323.58 v1(2181.19,1301.58) 2181.19,1305.58 R50.1@2201.19,1325.58
  Bottom Layer w12: C27.2@1545.19,1317.57 1552.24,1317.57 v1@1580.19,1289.63 ; v1(1578.19,1295.58) 1580.19,1293.58 v1@1580.19,1289.63 ; v1(1580.19,1243.36) v1@1580.19,1289.63
VDD_CPU: C8.1 C9.1 C24.2 C25.2 L2.2 U1.1 U2.H8 U2.H9 U2.J8 U2.J9 U2.J10 U2.J11 U2.L8 | length 457.6
  Top Layer w6: U1.1@567.81,589.6 567.81,608.2 601.19,641.58 695.5,641.58 L2.2@695.63,641.45
  Top Layer w8: U2.L8@1412.57,1283.03 1426.12,1296.58 1450.2,1296.58 U2.J8@1463.76,1283.03 v1(1476.55,1270.23) ; U2.J11@1463.76,1206.26 1463.76,1206.62 v1(1450.96,1219.42) 1451.33,1219.42 U2.J10@1463.76,1231.85 ; U2.H8@1489.35,1283.03 v1(1476.55,1270.23) ; U2.J10@1463.76,1231.85 v1(1476.43,1244.52) U2.H9@1489.35,1257.44 v1(1476.55,1270.23) ; U2.J10@1463.76,1231.85 1463.76,1232.03 v1(1450.96,1244.83) 1451.15,1244.83 U2.J9@1463.76,1257.44 v1(1476.55,1270.23)
  Bottom Layer w15: v1(1450.96,1219.42) 1450.96,1207.81 C24.2@1457.04,1201.73 ; C25.2@1451.2,1289.58 1457.2,1289.58 v1(1476.55,1270.23)
  other v3: 722.19,681.58 759.26,681.58 791.99,681.58 829.54,681.58
VDD_GPU: C4.1 C6.1 C21.2 C22.2 C23.2 L1.2 U1.16 U2.F8 U2.F9 U2.F10 U2.F11 U2.F12 U2.F13 U2.G8 U2.G9 U2.G10 U2.G11 U2.G12 | length 447.5
  Top Layer w6: U1.16@595.41,499 607.77,499 612.19,494.58 612.19,474.58 626.19,460.58 682.3,460.58 L1.2@696.63,446.25
  Top Layer w8: U2.G11@1513.65,1207.55 U2.G11@1514.94,1206.26 ; U2.F13@1540.53,1155.08 1539.69,1155.08 v1(1527.19,1167.58) ; U2.F12@1540.53,1180.67 1527.44,1167.58 v1(1527.19,1167.58) ; U2.F11@1540.53,1206.26 U2.G11@1514.94,1206.26 ; U2.F10@1540.53,1231.85 U2.G10@1516.92,1231.85 ; U2.F9@1540.53,1257.44 U2.G9@1517.05,1257.44 ; U2.F8@1540.53,1283.03 U2.G8@1514.94,1283.03 1514.94,1280.33 1513.94,1280.33 v1(1503.19,1269.58) 1513.94,1258.83 U2.G9@1514.94,1258.83 ; U2.G11@1514.94,1203.33 1516.4,1204.79 U2.G11@1514.94,1206.26 ; U2.G11@1514.94,1203.33 U2.G11@1514.94,1206.26 ; U2.G11@1514.94,1203.33 v1(1504.19,1192.58) 1514.94,1181.83 U2.G12@1514.94,1180.67 1527.19,1168.41 v1(1527.19,1167.58) ; U2.G11@1514.94,1206.26 1514.94,1208.83 1512.94,1208.83 v1(1503.19,1218.58) U2.G10@1514.94,1230.33 ; U2.G10@1514.94,1230.33 U2.G10@1514.94,1233.83 ; U2.G10@1514.94,1230.33 1516.46,1231.85 U2.G10@1516.92,1231.85 ; U2.G10@1514.94,1233.83 U2.G10@1516.92,1231.85 ; U2.G10@1514.94,1233.83 v1(1504.19,1244.58) U2.G9@1514.94,1255.33 ; U2.G9@1514.94,1255.33 U2.G9@1514.94,1258.83 ; U2.G9@1514.94,1255.33 U2.G9@1517.05,1257.44 ; U2.G9@1514.94,1258.83 1516.33,1257.44 U2.G9@1517.05,1257.44
  other v3: 688.19,416.58 728.19,416.58 766.19,416.58 803.19,416.58 837.19,416.58
WL_REG_ON: U2.B10 | length 85.6
  Top Layer w4: U2.B10@1642.89,1231.85 1657.62,1246.58 1701.19,1246.58 v1(1716.19,1231.58)
XI: C121.1 R53.2 U5.10 X4.3 | length 198.6
  Top Layer w5: R53.2@2016.19,1068.34 2017.72,1069.87 C121.1@2067.61,1069.87 2100.44,1069.87 X4.3@2107.19,1063.12 2100.73,1063.12 2052.06,1014.45 U5.10@2052.06,985.54
XO: C122.1 U5.9 X4.1 | length 262.7
  Top Layer w5: U5.9@2071.74,985.54 2071.74,1010.13 2103.19,1041.58 2177.35,1041.58 2185.19,1049.42 2185.19,1098.22 2180.29,1103.12 ; X4.1@2157.19,1103.12 2180.29,1103.12 ; C122.1@2207.62,1097.83 2202.34,1103.12 2180.29,1103.12
pads on no net: HDMIOUT.14 U1.10 U1.14 U2.A8 U2.B2 U2.B8 U2.B9 U2.C3 U2.C11 U2.C16 U2.D1 U2.D14 U2.F4 U2.G2 U2.L18 U2.N7 U2.N10 U2.P7 U2.P9 U2.P10 U2.P12 U2.R9 U2.R12 U2.T5 U2.T6 U2.T7 U2.T9 U2.T11 U2.T12 U2.U5 U2.U8 U2.U9 U2.U10 U2.U11 U2.U12 U2.V8 U2.V10 U4.A1 U4.A2 U4.A7 U4.A8 U4.A9 U4.A10 U4.A11 U4.A12 U4.A13 U4.A14 U4.B1 U4.B7 U4.B8 U4.B9 U4.B10 U4.B11 U4.B12 U4.B13 U4.B14 U4.C1 U4.C3 U4.C5 U4.C7 U4.C8 U4.C9 U4.C10 U4.C11 U4.C12 U4.C13 U4.C14 U4.D1 U4.D2 U4.D3 U4.D4 U4.D12 U4.D13 U4.D14 U4.E1 U4.E2 U4.E3 U4.E5 U4.E8 U4.E9 U4.E10 U4.E12 U4.E13 U4.E14 U4.F1 U4.F2 U4.F3 U4.F10 U4.F12 U4.F13 U4.F14 U4.G1 U4.G2 U4.G3 U4.G10 U4.G12 U4.G13 U4.G14 U4.H1 U4.H2 U4.H3 U4.H12 U4.H13 U4.H14 U4.J1 U4.J2 U4.J3 U4.J12 U4.J13 U4.J14 U4.K1 U4.K2 U4.K3 U4.K6 U4.K7 U4.K10 U4.K12 U4.K13 U4.K14 U4.L1 U4.L2 U4.L3 U4.L12 U4.L13 U4.L14 U4.M1 U4.M2 U4.M3 U4.M7 U4.M8 U4.M9 U4.M10 U4.M11 U4.M12 U4.M13 U4.M14 U4.N1 U4.N3 U4.N6 U4.N7 U4.N8 U4.N9 U4.N10 U4.N11 U4.N12 U4.N13 U4.N14 U4.P1 U4.P2 U4.P7 U4.P8 U4.P9 U4.P10 U4.P11 U4.P12 U4.P13 U4.P14 U5.32 USB1.A8 USB1.B8 USB2.A8 USB2.B8 USB3.A8 USB3.B8 USB4.A8 USB4.B8

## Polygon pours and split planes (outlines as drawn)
GND on Bottom Layer "Bottom Layer-GND 1" (solid, remove dead copper, pour order 4): 1155.96,1545.98 1745.96,1545.98 1745.96,910.78 1155.96,910.78
GND on Bottom Layer "Bottom Layer-GND" (solid, remove dead copper, pour order 1): -232.38,2393.65 2754.62,2393.65 2754.62,-176.35 -232.38,-176.35
GND on Mid-Layer 4 "Inner4-GND 1" (solid, remove dead copper, pour order 12): -184.31,2336.58 2802.69,2336.58 2802.69,-233.42 -184.31,-233.42
GND on Mid-Layer 4 "Inner4-GND" (solid, remove dead copper, pour order 10): 1155.19,1522.76 1745.19,1522.76 1745.19,887.56 1155.19,887.56
VBUS on Mid-Layer 4 "Inner4-PS 1" (solid, remove dead copper, pour order 8): 73.77,549 73.77,759.58 352.65,759.58 416.65,695.58 641.5,695.58 695.63,641.45 695.63,462.02 683.19,449.58 607,449.58 595.41,461.17 595.41,562 567.81,589.6 484.02,589.6 443.42,549
VBUS on Mid-Layer 4 "Inner4-PS" (solid, remove dead copper, pour order 5): 1130.54,140.58 320.19,140.58 73.34,387.43 73.34,1095.58 326.19,1095.58 326.19,451.58 445.19,332.58 1129.33,332.58 1167.19,295.58 1167.19,189.48
GND on Mid-Layer 4 "Inner4-GND 2" (solid, remove dead copper, pour order 13): 1423.19,986.58 1340.19,903.58 860.19,903.58 770.19,993.58 770.19,1421.58 893.19,1544.58 1327.19,1544.58 1423.19,1448.58
GND on Mid-Layer 1 "Inner1-GND 1" (solid, remove dead copper, pour order 15): 1155.96,1523.86 1745.96,1523.86 1745.96,888.66 1155.96,888.66
GND on Mid-Layer 1 "Inner1-GND" (solid, remove dead copper, pour order 14): -222.9,2382.93 2764.1,2382.93 2764.1,-187.07 -222.9,-187.07
VDD_GPU on Mid-Layer 1 "Inner1-VDD_GPU" (solid, remove dead copper, pour order 9): 670.19,363.51 823.12,363.51 911.19,451.58 1385.19,451.58 1842.19,908.58 1842.19,1188.58 1733.19,1297.58 1508.19,1297.58 1493.19,1282.58 1493.19,1180.58 1650.19,1023.58 1650.19,941.58 1300.46,591.85 777.46,591.85 639.19,453.58 639.19,394.51
VDD_CPU on Mid-Layer 1 "Inner1-VDD_CPU" (solid, remove dead copper, pour order 11): 1299.46,600.85 1642.19,943.58 1642.19,1021.58 1486.19,1177.58 1486.19,1278.58 1474.19,1290.58 1434.19,1290.58 1410.57,1266.96 1410.57,959.96 1174.19,723.58 724.19,723.58 697.19,696.58 697.19,637.58 733.92,600.85
GND on Top Layer "Top Layer-GND" (solid, remove dead copper, pour order 0): -239.81,2401.58 2747.19,2401.58 2747.19,-168.42 -239.81,-168.42
VDD33 on Mid-Layer 2 "Inner2-GND" (solid, remove dead copper, pour order 2): -211.11,2370.13 2775.89,2370.13 2775.89,-199.87 -211.11,-199.87
VDD33 on Mid-Layer 3 "Inner3-3V3" (solid, remove dead copper, pour order 3): -198.31,2355.95 2788.69,2355.95 2788.69,-214.05 -198.31,-214.05

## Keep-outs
Top Layer:
  region: 793.19,1559.26 1690.98,1559.26 1690.98,926.58 793.19,926.58
  region: 1923.81,363.29 1923.81,496.36 1899.59,520.58 1777.19,520.58 1534.19,763.58 1534.19,948.03 1539.19,953.03 1643.74,953.03 1643.74,829.03 1819.19,653.58 2072.46,653.58 2145.48,580.56 2145.48,368.38 2140.39,363.29
Mid-Layer 2:
  region: 820.69,1405.7 947.91,1532.92 1277.39,1532.92 1403.89,1406.42 1403.89,997.59 1290.54,884.24 932.69,884.24 820.69,996.24
Mid-Layer 3:
  region: 1412.69,1024.08 1308.69,920.08 918.69,920.08 771.69,1067.08 771.69,1397.08 918.69,1544.08 1308.69,1544.08 1412.69,1440.08
  region: 997.75,1370.99 1045.39,1323.35 1229.39,1323.35 1276.39,1370.35 1276.39,1436.35 1243.42,1469.32 1050.85,1469.32 997.75,1416.23
  region: 832.56,1007.21 903.19,936.58 1278.99,936.58 1359.19,1016.78 1359.19,1083.58 1265.22,1177.55 913.65,1177.55 832.56,1096.46
Bottom Layer:
  region: 868.66,1163.11 918.19,1113.58 918.19,1081.22 931.83,1067.58 931.83,1027.94 1026.83,932.94 1351.59,932.94 1369,950.35 1369,994.08 1342.87,1020.21 1135.56,1020.21 1012.66,1143.11 964.46,1143.11 897.28,1210.29 839.9,1210.29 825.19,1195.58 825.19,1172.58 834.66,1163.11
  region: 1022.4,1430.54 1255.04,1430.54 1277.57,1408.02 1277.57,1368.86 1254.57,1345.86 1023.72,1345.86 990.72,1378.86 990.72,1398.86
Keep-Out Layer:
  the board outline again, w10

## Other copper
Top Layer:
  region net VBUS: 579.61,510.8 615.97,510.8 625.19,501.58 625.19,477.58 630.19,472.58 650.36,472.58 654.63,476.85 654.63,497.14 633.19,518.58 579.19,518.58 579.19,511.22 579.61,510.8
  region net 1V8: 563.2,487.58 562.91,431.86 582.19,412.58 582.19,394.58 604.19,394.58 604.19,443.58 572.19,475.58 572.19,487.58 563.2,487.58
  region net VCC_DRAM: 480.19,708.5 480.19,804.58 390.19,804.58 376.19,790.58 376.19,708.5 480.19,708.5
  region net VDD_GPU: 662.19,466.58 662.19,413.58 675.19,400.58 845.19,400.58 859.19,414.58 859.19,466.58 662.19,466.58
  region net VDD_CPU: 662.19,621.58 859.19,621.58 859.19,681.2 841.31,699.08 698.69,699.08 662.19,662.58 662.19,621.58
  region net NetL1_1: 580.19,534.58 727.19,534.58 731.19,530.58 731.19,493.58 668.19,493.58 635.19,526.58 580.19,526.58 580.19,534.58
  region net NetL2_1: 579.61,550.2 621.81,550.2 658.19,586.58 658.19,595.58 731.19,595.58 731.19,547.3 726.19,542.3 579.61,542.3 579.61,550.2
  region net VBUS: 579.61,558.1 579.61,601 605.19,626.58 639.19,626.58 648.19,617.58 648.19,587.58 618.19,557.58 580.13,557.58 579.61,558.1
  region net VBUS: 548.11,573.8 548.11,662.5 574.19,688.58 574.19,724.58 665.19,724.58 665.19,690.58 625.19,650.58 596.19,650.58 556.19,610.58 556.19,573.58 548.33,573.58 548.11,573.8
  region net NetL3_1: 540.21,573.8 540.19,573.82 540.19,669.58 545.19,674.58 545.19,741.58 544.19,742.58 506.19,742.58 506.19,635.58 532.19,609.58 532.19,574.02 532.41,573.8 540.21,573.8

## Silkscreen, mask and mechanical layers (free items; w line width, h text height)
Top Overlay:
  text "GPIO" at 287.19,1873.58 h69
  text "Embedded Linux development board" at 968.01,1821.55 h70 r359.95
  text "Power" at 2396.82,1771.15 h30 r90
  text "by: aixiao@aixiao.me" at 975,1752.85 h57
  text "2023 v1.0" at 975,1668.35 h57
  text "eMMC" at 2477.45,1491.32 h69 r90
  text "TF Card" at 574.19,1320.58 h69 r90
  text "USB" at 23.19,1200.58 h69
  text "DRAM" at 914.19,853.48 h67.5
  text "USB" at 23.19,691.58 h69
  text "FAN" at 891.19,660.58 h69
  text "RJ45" at 2292.52,243.59 h69
  text "USB" at 332.19,37.58 h69 r90
  text "OTG" at 825.19,37.58 h69 r90
  text "Audio" at 1301.19,37.58 h69 r90
  text "HDMI" at 1645.19,37.58 h69 r90
Bottom Overlay:
  text "D7" at 97.19,1727.51 h45
  text "D6" at 95.99,1667.81 h45
  text "D5" at 97.19,1607.61 h45
  text "D4" at 98.39,1546.91 h45
  text "D3" at 97.19,1487.21 h45
  text "D2" at 97.19,1426.51 h45
  text "D13" at 223.83,1003.66 h45
  text "D14" at 223.83,960.16 h45
Mechanical 6:
  circle w8: c1627.97,1609.24 r39.37
  lines w6: 736.42,717.69 1720.67,717.69 1720.67,1701.94 736.42,1701.94 736.42,717.69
